VERSION 5.8 ;
BUSBITCHARS "[]" ;
DIVIDERCHAR "/" ;
UNITS
    DATABASE MICRONS 1000 ;
END UNITS

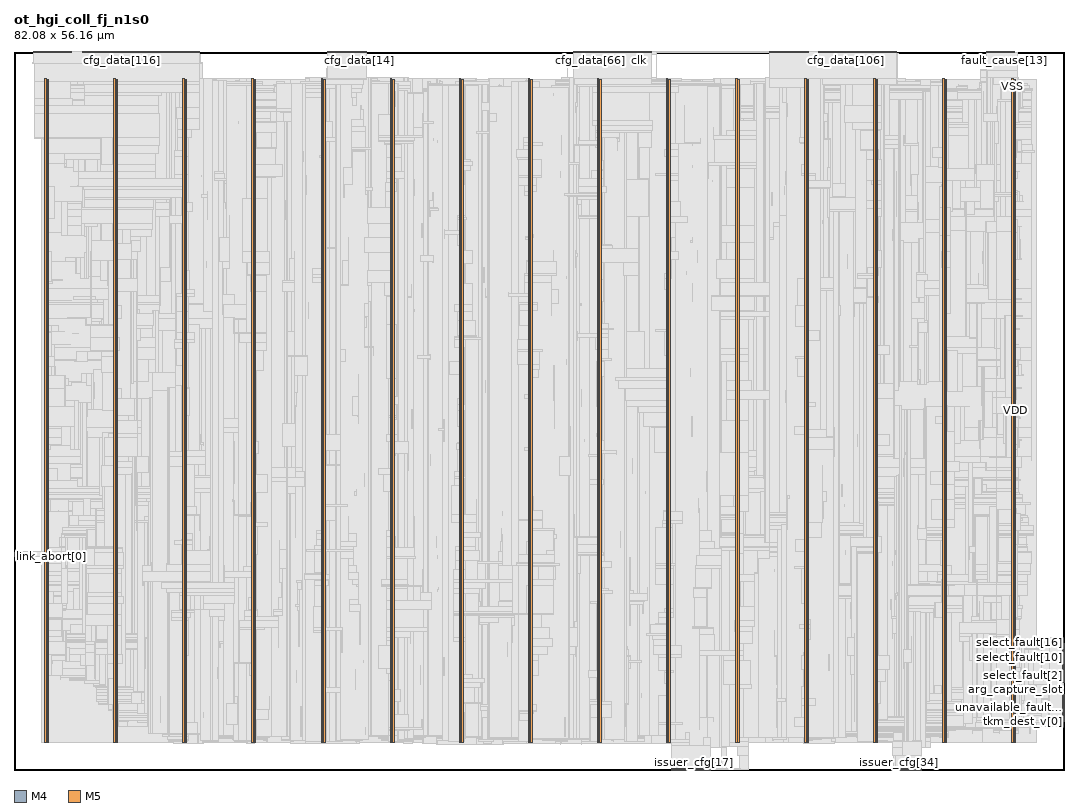
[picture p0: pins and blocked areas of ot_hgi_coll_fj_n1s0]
MACRO ot_hgi_coll_fj_n1s0
  FOREIGN ot_hgi_coll_fj_n1s0 0 0 ;
  CLASS BLOCK ;
  SIZE 82.08 BY 56.16 ;
  PIN arg_capture_slot
    DIRECTION INPUT ;
    USE SIGNAL ;
    PORT
      LAYER M4 ;
        RECT  81.996 6.864 82.08 6.888 ;
    END
  END arg_capture_slot
  PIN capture_fault[0]
    DIRECTION INPUT ;
    USE SIGNAL ;
    PORT
      LAYER M4 ;
        RECT  81.996 6.96 82.08 6.984 ;
    END
  END capture_fault[0]
  PIN capture_fault[1]
    DIRECTION INPUT ;
    USE SIGNAL ;
    PORT
      LAYER M4 ;
        RECT  81.996 7.056 82.08 7.08 ;
    END
  END capture_fault[1]
  PIN capture_fault[2]
    DIRECTION INPUT ;
    USE SIGNAL ;
    PORT
      LAYER M4 ;
        RECT  81.996 7.152 82.08 7.176 ;
    END
  END capture_fault[2]
  PIN capture_fault[3]
    DIRECTION INPUT ;
    USE SIGNAL ;
    PORT
      LAYER M4 ;
        RECT  81.996 7.248 82.08 7.272 ;
    END
  END capture_fault[3]
  PIN capture_fault[4]
    DIRECTION INPUT ;
    USE SIGNAL ;
    PORT
      LAYER M4 ;
        RECT  81.996 7.344 82.08 7.368 ;
    END
  END capture_fault[4]
  PIN capture_fault[5]
    DIRECTION INPUT ;
    USE SIGNAL ;
    PORT
      LAYER M4 ;
        RECT  81.996 7.44 82.08 7.464 ;
    END
  END capture_fault[5]
  PIN capture_fault[6]
    DIRECTION INPUT ;
    USE SIGNAL ;
    PORT
      LAYER M4 ;
        RECT  81.996 7.536 82.08 7.56 ;
    END
  END capture_fault[6]
  PIN capture_fault[7]
    DIRECTION INPUT ;
    USE SIGNAL ;
    PORT
      LAYER M4 ;
        RECT  81.996 7.632 82.08 7.656 ;
    END
  END capture_fault[7]
  PIN cfg_addr[0]
    DIRECTION INPUT ;
    USE SIGNAL ;
    PORT
      LAYER M5 ;
        RECT  24.528 56.076 24.552 56.16 ;
    END
  END cfg_addr[0]
  PIN cfg_addr[10]
    DIRECTION INPUT ;
    USE SIGNAL ;
    PORT
      LAYER M5 ;
        RECT  25.488 56.076 25.512 56.16 ;
    END
  END cfg_addr[10]
  PIN cfg_addr[11]
    DIRECTION INPUT ;
    USE SIGNAL ;
    PORT
      LAYER M5 ;
        RECT  25.584 56.076 25.608 56.16 ;
    END
  END cfg_addr[11]
  PIN cfg_addr[1]
    DIRECTION INPUT ;
    USE SIGNAL ;
    PORT
      LAYER M5 ;
        RECT  24.624 56.076 24.648 56.16 ;
    END
  END cfg_addr[1]
  PIN cfg_addr[2]
    DIRECTION INPUT ;
    USE SIGNAL ;
    PORT
      LAYER M5 ;
        RECT  24.72 56.076 24.744 56.16 ;
    END
  END cfg_addr[2]
  PIN cfg_addr[3]
    DIRECTION INPUT ;
    USE SIGNAL ;
    PORT
      LAYER M5 ;
        RECT  24.816 56.076 24.84 56.16 ;
    END
  END cfg_addr[3]
  PIN cfg_addr[4]
    DIRECTION INPUT ;
    USE SIGNAL ;
    PORT
      LAYER M5 ;
        RECT  24.912 56.076 24.936 56.16 ;
    END
  END cfg_addr[4]
  PIN cfg_addr[5]
    DIRECTION INPUT ;
    USE SIGNAL ;
    PORT
      LAYER M5 ;
        RECT  25.008 56.076 25.032 56.16 ;
    END
  END cfg_addr[5]
  PIN cfg_addr[6]
    DIRECTION INPUT ;
    USE SIGNAL ;
    PORT
      LAYER M5 ;
        RECT  25.104 56.076 25.128 56.16 ;
    END
  END cfg_addr[6]
  PIN cfg_addr[7]
    DIRECTION INPUT ;
    USE SIGNAL ;
    PORT
      LAYER M5 ;
        RECT  25.2 56.076 25.224 56.16 ;
    END
  END cfg_addr[7]
  PIN cfg_addr[8]
    DIRECTION INPUT ;
    USE SIGNAL ;
    PORT
      LAYER M5 ;
        RECT  25.296 56.076 25.32 56.16 ;
    END
  END cfg_addr[8]
  PIN cfg_addr[9]
    DIRECTION INPUT ;
    USE SIGNAL ;
    PORT
      LAYER M5 ;
        RECT  25.392 56.076 25.416 56.16 ;
    END
  END cfg_addr[9]
  PIN cfg_data[0]
    DIRECTION INPUT ;
    USE SIGNAL ;
    PORT
      LAYER M5 ;
        RECT  25.68 56.076 25.704 56.16 ;
    END
  END cfg_data[0]
  PIN cfg_data[100]
    DIRECTION INPUT ;
    USE SIGNAL ;
    PORT
      LAYER M5 ;
        RECT  64.464 56.076 64.488 56.16 ;
    END
  END cfg_data[100]
  PIN cfg_data[101]
    DIRECTION INPUT ;
    USE SIGNAL ;
    PORT
      LAYER M5 ;
        RECT  64.56 56.076 64.584 56.16 ;
    END
  END cfg_data[101]
  PIN cfg_data[102]
    DIRECTION INPUT ;
    USE SIGNAL ;
    PORT
      LAYER M5 ;
        RECT  64.656 56.076 64.68 56.16 ;
    END
  END cfg_data[102]
  PIN cfg_data[103]
    DIRECTION INPUT ;
    USE SIGNAL ;
    PORT
      LAYER M5 ;
        RECT  64.752 56.076 64.776 56.16 ;
    END
  END cfg_data[103]
  PIN cfg_data[104]
    DIRECTION INPUT ;
    USE SIGNAL ;
    PORT
      LAYER M5 ;
        RECT  64.848 56.076 64.872 56.16 ;
    END
  END cfg_data[104]
  PIN cfg_data[105]
    DIRECTION INPUT ;
    USE SIGNAL ;
    PORT
      LAYER M5 ;
        RECT  64.944 56.076 64.968 56.16 ;
    END
  END cfg_data[105]
  PIN cfg_data[106]
    DIRECTION INPUT ;
    USE SIGNAL ;
    PORT
      LAYER M5 ;
        RECT  65.04 56.076 65.064 56.16 ;
    END
  END cfg_data[106]
  PIN cfg_data[107]
    DIRECTION INPUT ;
    USE SIGNAL ;
    PORT
      LAYER M5 ;
        RECT  65.136 56.076 65.16 56.16 ;
    END
  END cfg_data[107]
  PIN cfg_data[108]
    DIRECTION INPUT ;
    USE SIGNAL ;
    PORT
      LAYER M5 ;
        RECT  65.232 56.076 65.256 56.16 ;
    END
  END cfg_data[108]
  PIN cfg_data[109]
    DIRECTION INPUT ;
    USE SIGNAL ;
    PORT
      LAYER M5 ;
        RECT  65.328 56.076 65.352 56.16 ;
    END
  END cfg_data[109]
  PIN cfg_data[10]
    DIRECTION INPUT ;
    USE SIGNAL ;
    PORT
      LAYER M5 ;
        RECT  26.64 56.076 26.664 56.16 ;
    END
  END cfg_data[10]
  PIN cfg_data[110]
    DIRECTION INPUT ;
    USE SIGNAL ;
    PORT
      LAYER M5 ;
        RECT  65.424 56.076 65.448 56.16 ;
    END
  END cfg_data[110]
  PIN cfg_data[111]
    DIRECTION INPUT ;
    USE SIGNAL ;
    PORT
      LAYER M5 ;
        RECT  65.52 56.076 65.544 56.16 ;
    END
  END cfg_data[111]
  PIN cfg_data[112]
    DIRECTION INPUT ;
    USE SIGNAL ;
    PORT
      LAYER M5 ;
        RECT  65.616 56.076 65.64 56.16 ;
    END
  END cfg_data[112]
  PIN cfg_data[113]
    DIRECTION INPUT ;
    USE SIGNAL ;
    PORT
      LAYER M5 ;
        RECT  65.712 56.076 65.736 56.16 ;
    END
  END cfg_data[113]
  PIN cfg_data[114]
    DIRECTION INPUT ;
    USE SIGNAL ;
    PORT
      LAYER M5 ;
        RECT  65.808 56.076 65.832 56.16 ;
    END
  END cfg_data[114]
  PIN cfg_data[115]
    DIRECTION INPUT ;
    USE SIGNAL ;
    PORT
      LAYER M5 ;
        RECT  65.904 56.076 65.928 56.16 ;
    END
  END cfg_data[115]
  PIN cfg_data[116]
    DIRECTION INPUT ;
    USE SIGNAL ;
    PORT
      LAYER M5 ;
        RECT  8.4 56.076 8.424 56.16 ;
    END
  END cfg_data[116]
  PIN cfg_data[117]
    DIRECTION INPUT ;
    USE SIGNAL ;
    PORT
      LAYER M5 ;
        RECT  8.496 56.076 8.52 56.16 ;
    END
  END cfg_data[117]
  PIN cfg_data[118]
    DIRECTION INPUT ;
    USE SIGNAL ;
    PORT
      LAYER M5 ;
        RECT  8.592 56.076 8.616 56.16 ;
    END
  END cfg_data[118]
  PIN cfg_data[119]
    DIRECTION INPUT ;
    USE SIGNAL ;
    PORT
      LAYER M5 ;
        RECT  8.688 56.076 8.712 56.16 ;
    END
  END cfg_data[119]
  PIN cfg_data[11]
    DIRECTION INPUT ;
    USE SIGNAL ;
    PORT
      LAYER M5 ;
        RECT  26.736 56.076 26.76 56.16 ;
    END
  END cfg_data[11]
  PIN cfg_data[120]
    DIRECTION INPUT ;
    USE SIGNAL ;
    PORT
      LAYER M5 ;
        RECT  8.784 56.076 8.808 56.16 ;
    END
  END cfg_data[120]
  PIN cfg_data[121]
    DIRECTION INPUT ;
    USE SIGNAL ;
    PORT
      LAYER M5 ;
        RECT  8.88 56.076 8.904 56.16 ;
    END
  END cfg_data[121]
  PIN cfg_data[122]
    DIRECTION INPUT ;
    USE SIGNAL ;
    PORT
      LAYER M5 ;
        RECT  8.976 56.076 9 56.16 ;
    END
  END cfg_data[122]
  PIN cfg_data[123]
    DIRECTION INPUT ;
    USE SIGNAL ;
    PORT
      LAYER M5 ;
        RECT  9.072 56.076 9.096 56.16 ;
    END
  END cfg_data[123]
  PIN cfg_data[124]
    DIRECTION INPUT ;
    USE SIGNAL ;
    PORT
      LAYER M5 ;
        RECT  9.168 56.076 9.192 56.16 ;
    END
  END cfg_data[124]
  PIN cfg_data[125]
    DIRECTION INPUT ;
    USE SIGNAL ;
    PORT
      LAYER M5 ;
        RECT  9.264 56.076 9.288 56.16 ;
    END
  END cfg_data[125]
  PIN cfg_data[126]
    DIRECTION INPUT ;
    USE SIGNAL ;
    PORT
      LAYER M5 ;
        RECT  9.36 56.076 9.384 56.16 ;
    END
  END cfg_data[126]
  PIN cfg_data[127]
    DIRECTION INPUT ;
    USE SIGNAL ;
    PORT
      LAYER M5 ;
        RECT  9.456 56.076 9.48 56.16 ;
    END
  END cfg_data[127]
  PIN cfg_data[128]
    DIRECTION INPUT ;
    USE SIGNAL ;
    PORT
      LAYER M5 ;
        RECT  9.552 56.076 9.576 56.16 ;
    END
  END cfg_data[128]
  PIN cfg_data[129]
    DIRECTION INPUT ;
    USE SIGNAL ;
    PORT
      LAYER M5 ;
        RECT  9.648 56.076 9.672 56.16 ;
    END
  END cfg_data[129]
  PIN cfg_data[12]
    DIRECTION INPUT ;
    USE SIGNAL ;
    PORT
      LAYER M5 ;
        RECT  26.832 56.076 26.856 56.16 ;
    END
  END cfg_data[12]
  PIN cfg_data[130]
    DIRECTION INPUT ;
    USE SIGNAL ;
    PORT
      LAYER M5 ;
        RECT  9.744 56.076 9.768 56.16 ;
    END
  END cfg_data[130]
  PIN cfg_data[131]
    DIRECTION INPUT ;
    USE SIGNAL ;
    PORT
      LAYER M5 ;
        RECT  9.84 56.076 9.864 56.16 ;
    END
  END cfg_data[131]
  PIN cfg_data[132]
    DIRECTION INPUT ;
    USE SIGNAL ;
    PORT
      LAYER M5 ;
        RECT  9.936 56.076 9.96 56.16 ;
    END
  END cfg_data[132]
  PIN cfg_data[133]
    DIRECTION INPUT ;
    USE SIGNAL ;
    PORT
      LAYER M5 ;
        RECT  10.032 56.076 10.056 56.16 ;
    END
  END cfg_data[133]
  PIN cfg_data[134]
    DIRECTION INPUT ;
    USE SIGNAL ;
    PORT
      LAYER M5 ;
        RECT  10.128 56.076 10.152 56.16 ;
    END
  END cfg_data[134]
  PIN cfg_data[135]
    DIRECTION INPUT ;
    USE SIGNAL ;
    PORT
      LAYER M5 ;
        RECT  10.224 56.076 10.248 56.16 ;
    END
  END cfg_data[135]
  PIN cfg_data[136]
    DIRECTION INPUT ;
    USE SIGNAL ;
    PORT
      LAYER M5 ;
        RECT  10.32 56.076 10.344 56.16 ;
    END
  END cfg_data[136]
  PIN cfg_data[137]
    DIRECTION INPUT ;
    USE SIGNAL ;
    PORT
      LAYER M5 ;
        RECT  10.416 56.076 10.44 56.16 ;
    END
  END cfg_data[137]
  PIN cfg_data[138]
    DIRECTION INPUT ;
    USE SIGNAL ;
    PORT
      LAYER M5 ;
        RECT  10.512 56.076 10.536 56.16 ;
    END
  END cfg_data[138]
  PIN cfg_data[139]
    DIRECTION INPUT ;
    USE SIGNAL ;
    PORT
      LAYER M5 ;
        RECT  10.608 56.076 10.632 56.16 ;
    END
  END cfg_data[139]
  PIN cfg_data[13]
    DIRECTION INPUT ;
    USE SIGNAL ;
    PORT
      LAYER M5 ;
        RECT  26.928 56.076 26.952 56.16 ;
    END
  END cfg_data[13]
  PIN cfg_data[140]
    DIRECTION INPUT ;
    USE SIGNAL ;
    PORT
      LAYER M5 ;
        RECT  10.704 56.076 10.728 56.16 ;
    END
  END cfg_data[140]
  PIN cfg_data[141]
    DIRECTION INPUT ;
    USE SIGNAL ;
    PORT
      LAYER M5 ;
        RECT  10.8 56.076 10.824 56.16 ;
    END
  END cfg_data[141]
  PIN cfg_data[142]
    DIRECTION INPUT ;
    USE SIGNAL ;
    PORT
      LAYER M5 ;
        RECT  10.896 56.076 10.92 56.16 ;
    END
  END cfg_data[142]
  PIN cfg_data[143]
    DIRECTION INPUT ;
    USE SIGNAL ;
    PORT
      LAYER M5 ;
        RECT  10.992 56.076 11.016 56.16 ;
    END
  END cfg_data[143]
  PIN cfg_data[144]
    DIRECTION INPUT ;
    USE SIGNAL ;
    PORT
      LAYER M5 ;
        RECT  11.088 56.076 11.112 56.16 ;
    END
  END cfg_data[144]
  PIN cfg_data[145]
    DIRECTION INPUT ;
    USE SIGNAL ;
    PORT
      LAYER M5 ;
        RECT  11.184 56.076 11.208 56.16 ;
    END
  END cfg_data[145]
  PIN cfg_data[146]
    DIRECTION INPUT ;
    USE SIGNAL ;
    PORT
      LAYER M5 ;
        RECT  11.28 56.076 11.304 56.16 ;
    END
  END cfg_data[146]
  PIN cfg_data[147]
    DIRECTION INPUT ;
    USE SIGNAL ;
    PORT
      LAYER M5 ;
        RECT  11.376 56.076 11.4 56.16 ;
    END
  END cfg_data[147]
  PIN cfg_data[148]
    DIRECTION INPUT ;
    USE SIGNAL ;
    PORT
      LAYER M5 ;
        RECT  1.488 56.076 1.512 56.16 ;
    END
  END cfg_data[148]
  PIN cfg_data[149]
    DIRECTION INPUT ;
    USE SIGNAL ;
    PORT
      LAYER M5 ;
        RECT  1.584 56.076 1.608 56.16 ;
    END
  END cfg_data[149]
  PIN cfg_data[14]
    DIRECTION INPUT ;
    USE SIGNAL ;
    PORT
      LAYER M5 ;
        RECT  27.024 56.076 27.048 56.16 ;
    END
  END cfg_data[14]
  PIN cfg_data[150]
    DIRECTION INPUT ;
    USE SIGNAL ;
    PORT
      LAYER M5 ;
        RECT  1.68 56.076 1.704 56.16 ;
    END
  END cfg_data[150]
  PIN cfg_data[151]
    DIRECTION INPUT ;
    USE SIGNAL ;
    PORT
      LAYER M5 ;
        RECT  1.776 56.076 1.8 56.16 ;
    END
  END cfg_data[151]
  PIN cfg_data[152]
    DIRECTION INPUT ;
    USE SIGNAL ;
    PORT
      LAYER M5 ;
        RECT  1.872 56.076 1.896 56.16 ;
    END
  END cfg_data[152]
  PIN cfg_data[153]
    DIRECTION INPUT ;
    USE SIGNAL ;
    PORT
      LAYER M5 ;
        RECT  1.968 56.076 1.992 56.16 ;
    END
  END cfg_data[153]
  PIN cfg_data[154]
    DIRECTION INPUT ;
    USE SIGNAL ;
    PORT
      LAYER M5 ;
        RECT  2.064 56.076 2.088 56.16 ;
    END
  END cfg_data[154]
  PIN cfg_data[155]
    DIRECTION INPUT ;
    USE SIGNAL ;
    PORT
      LAYER M5 ;
        RECT  2.16 56.076 2.184 56.16 ;
    END
  END cfg_data[155]
  PIN cfg_data[156]
    DIRECTION INPUT ;
    USE SIGNAL ;
    PORT
      LAYER M5 ;
        RECT  2.256 56.076 2.28 56.16 ;
    END
  END cfg_data[156]
  PIN cfg_data[157]
    DIRECTION INPUT ;
    USE SIGNAL ;
    PORT
      LAYER M5 ;
        RECT  2.352 56.076 2.376 56.16 ;
    END
  END cfg_data[157]
  PIN cfg_data[158]
    DIRECTION INPUT ;
    USE SIGNAL ;
    PORT
      LAYER M5 ;
        RECT  2.448 56.076 2.472 56.16 ;
    END
  END cfg_data[158]
  PIN cfg_data[159]
    DIRECTION INPUT ;
    USE SIGNAL ;
    PORT
      LAYER M5 ;
        RECT  2.544 56.076 2.568 56.16 ;
    END
  END cfg_data[159]
  PIN cfg_data[15]
    DIRECTION INPUT ;
    USE SIGNAL ;
    PORT
      LAYER M5 ;
        RECT  27.12 56.076 27.144 56.16 ;
    END
  END cfg_data[15]
  PIN cfg_data[160]
    DIRECTION INPUT ;
    USE SIGNAL ;
    PORT
      LAYER M5 ;
        RECT  2.64 56.076 2.664 56.16 ;
    END
  END cfg_data[160]
  PIN cfg_data[161]
    DIRECTION INPUT ;
    USE SIGNAL ;
    PORT
      LAYER M5 ;
        RECT  2.736 56.076 2.76 56.16 ;
    END
  END cfg_data[161]
  PIN cfg_data[162]
    DIRECTION INPUT ;
    USE SIGNAL ;
    PORT
      LAYER M5 ;
        RECT  2.832 56.076 2.856 56.16 ;
    END
  END cfg_data[162]
  PIN cfg_data[163]
    DIRECTION INPUT ;
    USE SIGNAL ;
    PORT
      LAYER M5 ;
        RECT  2.928 56.076 2.952 56.16 ;
    END
  END cfg_data[163]
  PIN cfg_data[164]
    DIRECTION INPUT ;
    USE SIGNAL ;
    PORT
      LAYER M5 ;
        RECT  3.024 56.076 3.048 56.16 ;
    END
  END cfg_data[164]
  PIN cfg_data[165]
    DIRECTION INPUT ;
    USE SIGNAL ;
    PORT
      LAYER M5 ;
        RECT  3.12 56.076 3.144 56.16 ;
    END
  END cfg_data[165]
  PIN cfg_data[166]
    DIRECTION INPUT ;
    USE SIGNAL ;
    PORT
      LAYER M5 ;
        RECT  3.216 56.076 3.24 56.16 ;
    END
  END cfg_data[166]
  PIN cfg_data[167]
    DIRECTION INPUT ;
    USE SIGNAL ;
    PORT
      LAYER M5 ;
        RECT  3.312 56.076 3.336 56.16 ;
    END
  END cfg_data[167]
  PIN cfg_data[168]
    DIRECTION INPUT ;
    USE SIGNAL ;
    PORT
      LAYER M5 ;
        RECT  3.408 56.076 3.432 56.16 ;
    END
  END cfg_data[168]
  PIN cfg_data[169]
    DIRECTION INPUT ;
    USE SIGNAL ;
    PORT
      LAYER M5 ;
        RECT  3.504 56.076 3.528 56.16 ;
    END
  END cfg_data[169]
  PIN cfg_data[16]
    DIRECTION INPUT ;
    USE SIGNAL ;
    PORT
      LAYER M5 ;
        RECT  27.216 56.076 27.24 56.16 ;
    END
  END cfg_data[16]
  PIN cfg_data[170]
    DIRECTION INPUT ;
    USE SIGNAL ;
    PORT
      LAYER M5 ;
        RECT  3.6 56.076 3.624 56.16 ;
    END
  END cfg_data[170]
  PIN cfg_data[171]
    DIRECTION INPUT ;
    USE SIGNAL ;
    PORT
      LAYER M5 ;
        RECT  3.696 56.076 3.72 56.16 ;
    END
  END cfg_data[171]
  PIN cfg_data[172]
    DIRECTION INPUT ;
    USE SIGNAL ;
    PORT
      LAYER M5 ;
        RECT  3.792 56.076 3.816 56.16 ;
    END
  END cfg_data[172]
  PIN cfg_data[173]
    DIRECTION INPUT ;
    USE SIGNAL ;
    PORT
      LAYER M5 ;
        RECT  3.888 56.076 3.912 56.16 ;
    END
  END cfg_data[173]
  PIN cfg_data[174]
    DIRECTION INPUT ;
    USE SIGNAL ;
    PORT
      LAYER M5 ;
        RECT  3.984 56.076 4.008 56.16 ;
    END
  END cfg_data[174]
  PIN cfg_data[175]
    DIRECTION INPUT ;
    USE SIGNAL ;
    PORT
      LAYER M5 ;
        RECT  4.08 56.076 4.104 56.16 ;
    END
  END cfg_data[175]
  PIN cfg_data[176]
    DIRECTION INPUT ;
    USE SIGNAL ;
    PORT
      LAYER M5 ;
        RECT  4.176 56.076 4.2 56.16 ;
    END
  END cfg_data[176]
  PIN cfg_data[177]
    DIRECTION INPUT ;
    USE SIGNAL ;
    PORT
      LAYER M5 ;
        RECT  4.272 56.076 4.296 56.16 ;
    END
  END cfg_data[177]
  PIN cfg_data[178]
    DIRECTION INPUT ;
    USE SIGNAL ;
    PORT
      LAYER M5 ;
        RECT  4.368 56.076 4.392 56.16 ;
    END
  END cfg_data[178]
  PIN cfg_data[179]
    DIRECTION INPUT ;
    USE SIGNAL ;
    PORT
      LAYER M5 ;
        RECT  4.464 56.076 4.488 56.16 ;
    END
  END cfg_data[179]
  PIN cfg_data[17]
    DIRECTION INPUT ;
    USE SIGNAL ;
    PORT
      LAYER M5 ;
        RECT  27.312 56.076 27.336 56.16 ;
    END
  END cfg_data[17]
  PIN cfg_data[180]
    DIRECTION INPUT ;
    USE SIGNAL ;
    PORT
      LAYER M5 ;
        RECT  59.088 56.076 59.112 56.16 ;
    END
  END cfg_data[180]
  PIN cfg_data[181]
    DIRECTION INPUT ;
    USE SIGNAL ;
    PORT
      LAYER M5 ;
        RECT  59.184 56.076 59.208 56.16 ;
    END
  END cfg_data[181]
  PIN cfg_data[182]
    DIRECTION INPUT ;
    USE SIGNAL ;
    PORT
      LAYER M5 ;
        RECT  59.28 56.076 59.304 56.16 ;
    END
  END cfg_data[182]
  PIN cfg_data[183]
    DIRECTION INPUT ;
    USE SIGNAL ;
    PORT
      LAYER M5 ;
        RECT  59.376 56.076 59.4 56.16 ;
    END
  END cfg_data[183]
  PIN cfg_data[184]
    DIRECTION INPUT ;
    USE SIGNAL ;
    PORT
      LAYER M5 ;
        RECT  59.472 56.076 59.496 56.16 ;
    END
  END cfg_data[184]
  PIN cfg_data[185]
    DIRECTION INPUT ;
    USE SIGNAL ;
    PORT
      LAYER M5 ;
        RECT  59.568 56.076 59.592 56.16 ;
    END
  END cfg_data[185]
  PIN cfg_data[186]
    DIRECTION INPUT ;
    USE SIGNAL ;
    PORT
      LAYER M5 ;
        RECT  59.664 56.076 59.688 56.16 ;
    END
  END cfg_data[186]
  PIN cfg_data[187]
    DIRECTION INPUT ;
    USE SIGNAL ;
    PORT
      LAYER M5 ;
        RECT  59.76 56.076 59.784 56.16 ;
    END
  END cfg_data[187]
  PIN cfg_data[188]
    DIRECTION INPUT ;
    USE SIGNAL ;
    PORT
      LAYER M5 ;
        RECT  59.856 56.076 59.88 56.16 ;
    END
  END cfg_data[188]
  PIN cfg_data[189]
    DIRECTION INPUT ;
    USE SIGNAL ;
    PORT
      LAYER M5 ;
        RECT  59.952 56.076 59.976 56.16 ;
    END
  END cfg_data[189]
  PIN cfg_data[18]
    DIRECTION INPUT ;
    USE SIGNAL ;
    PORT
      LAYER M5 ;
        RECT  27.408 56.076 27.432 56.16 ;
    END
  END cfg_data[18]
  PIN cfg_data[190]
    DIRECTION INPUT ;
    USE SIGNAL ;
    PORT
      LAYER M5 ;
        RECT  60.048 56.076 60.072 56.16 ;
    END
  END cfg_data[190]
  PIN cfg_data[191]
    DIRECTION INPUT ;
    USE SIGNAL ;
    PORT
      LAYER M5 ;
        RECT  60.144 56.076 60.168 56.16 ;
    END
  END cfg_data[191]
  PIN cfg_data[192]
    DIRECTION INPUT ;
    USE SIGNAL ;
    PORT
      LAYER M5 ;
        RECT  60.24 56.076 60.264 56.16 ;
    END
  END cfg_data[192]
  PIN cfg_data[193]
    DIRECTION INPUT ;
    USE SIGNAL ;
    PORT
      LAYER M5 ;
        RECT  60.336 56.076 60.36 56.16 ;
    END
  END cfg_data[193]
  PIN cfg_data[194]
    DIRECTION INPUT ;
    USE SIGNAL ;
    PORT
      LAYER M5 ;
        RECT  60.432 56.076 60.456 56.16 ;
    END
  END cfg_data[194]
  PIN cfg_data[195]
    DIRECTION INPUT ;
    USE SIGNAL ;
    PORT
      LAYER M5 ;
        RECT  60.528 56.076 60.552 56.16 ;
    END
  END cfg_data[195]
  PIN cfg_data[196]
    DIRECTION INPUT ;
    USE SIGNAL ;
    PORT
      LAYER M5 ;
        RECT  60.624 56.076 60.648 56.16 ;
    END
  END cfg_data[196]
  PIN cfg_data[197]
    DIRECTION INPUT ;
    USE SIGNAL ;
    PORT
      LAYER M5 ;
        RECT  60.72 56.076 60.744 56.16 ;
    END
  END cfg_data[197]
  PIN cfg_data[198]
    DIRECTION INPUT ;
    USE SIGNAL ;
    PORT
      LAYER M5 ;
        RECT  60.816 56.076 60.84 56.16 ;
    END
  END cfg_data[198]
  PIN cfg_data[199]
    DIRECTION INPUT ;
    USE SIGNAL ;
    PORT
      LAYER M5 ;
        RECT  60.912 56.076 60.936 56.16 ;
    END
  END cfg_data[199]
  PIN cfg_data[19]
    DIRECTION INPUT ;
    USE SIGNAL ;
    PORT
      LAYER M5 ;
        RECT  27.504 56.076 27.528 56.16 ;
    END
  END cfg_data[19]
  PIN cfg_data[1]
    DIRECTION INPUT ;
    USE SIGNAL ;
    PORT
      LAYER M5 ;
        RECT  25.776 56.076 25.8 56.16 ;
    END
  END cfg_data[1]
  PIN cfg_data[200]
    DIRECTION INPUT ;
    USE SIGNAL ;
    PORT
      LAYER M5 ;
        RECT  61.008 56.076 61.032 56.16 ;
    END
  END cfg_data[200]
  PIN cfg_data[201]
    DIRECTION INPUT ;
    USE SIGNAL ;
    PORT
      LAYER M5 ;
        RECT  61.104 56.076 61.128 56.16 ;
    END
  END cfg_data[201]
  PIN cfg_data[202]
    DIRECTION INPUT ;
    USE SIGNAL ;
    PORT
      LAYER M5 ;
        RECT  61.2 56.076 61.224 56.16 ;
    END
  END cfg_data[202]
  PIN cfg_data[203]
    DIRECTION INPUT ;
    USE SIGNAL ;
    PORT
      LAYER M5 ;
        RECT  61.296 56.076 61.32 56.16 ;
    END
  END cfg_data[203]
  PIN cfg_data[204]
    DIRECTION INPUT ;
    USE SIGNAL ;
    PORT
      LAYER M5 ;
        RECT  61.392 56.076 61.416 56.16 ;
    END
  END cfg_data[204]
  PIN cfg_data[205]
    DIRECTION INPUT ;
    USE SIGNAL ;
    PORT
      LAYER M5 ;
        RECT  61.488 56.076 61.512 56.16 ;
    END
  END cfg_data[205]
  PIN cfg_data[206]
    DIRECTION INPUT ;
    USE SIGNAL ;
    PORT
      LAYER M5 ;
        RECT  61.584 56.076 61.608 56.16 ;
    END
  END cfg_data[206]
  PIN cfg_data[207]
    DIRECTION INPUT ;
    USE SIGNAL ;
    PORT
      LAYER M5 ;
        RECT  61.68 56.076 61.704 56.16 ;
    END
  END cfg_data[207]
  PIN cfg_data[208]
    DIRECTION INPUT ;
    USE SIGNAL ;
    PORT
      LAYER M5 ;
        RECT  61.776 56.076 61.8 56.16 ;
    END
  END cfg_data[208]
  PIN cfg_data[209]
    DIRECTION INPUT ;
    USE SIGNAL ;
    PORT
      LAYER M5 ;
        RECT  61.872 56.076 61.896 56.16 ;
    END
  END cfg_data[209]
  PIN cfg_data[20]
    DIRECTION INPUT ;
    USE SIGNAL ;
    PORT
      LAYER M5 ;
        RECT  11.472 56.076 11.496 56.16 ;
    END
  END cfg_data[20]
  PIN cfg_data[210]
    DIRECTION INPUT ;
    USE SIGNAL ;
    PORT
      LAYER M5 ;
        RECT  61.968 56.076 61.992 56.16 ;
    END
  END cfg_data[210]
  PIN cfg_data[211]
    DIRECTION INPUT ;
    USE SIGNAL ;
    PORT
      LAYER M5 ;
        RECT  62.064 56.076 62.088 56.16 ;
    END
  END cfg_data[211]
  PIN cfg_data[212]
    DIRECTION INPUT ;
    USE SIGNAL ;
    PORT
      LAYER M5 ;
        RECT  66 56.076 66.024 56.16 ;
    END
  END cfg_data[212]
  PIN cfg_data[213]
    DIRECTION INPUT ;
    USE SIGNAL ;
    PORT
      LAYER M5 ;
        RECT  66.096 56.076 66.12 56.16 ;
    END
  END cfg_data[213]
  PIN cfg_data[214]
    DIRECTION INPUT ;
    USE SIGNAL ;
    PORT
      LAYER M5 ;
        RECT  66.192 56.076 66.216 56.16 ;
    END
  END cfg_data[214]
  PIN cfg_data[215]
    DIRECTION INPUT ;
    USE SIGNAL ;
    PORT
      LAYER M5 ;
        RECT  66.288 56.076 66.312 56.16 ;
    END
  END cfg_data[215]
  PIN cfg_data[216]
    DIRECTION INPUT ;
    USE SIGNAL ;
    PORT
      LAYER M5 ;
        RECT  66.384 56.076 66.408 56.16 ;
    END
  END cfg_data[216]
  PIN cfg_data[217]
    DIRECTION INPUT ;
    USE SIGNAL ;
    PORT
      LAYER M5 ;
        RECT  66.48 56.076 66.504 56.16 ;
    END
  END cfg_data[217]
  PIN cfg_data[218]
    DIRECTION INPUT ;
    USE SIGNAL ;
    PORT
      LAYER M5 ;
        RECT  66.576 56.076 66.6 56.16 ;
    END
  END cfg_data[218]
  PIN cfg_data[219]
    DIRECTION INPUT ;
    USE SIGNAL ;
    PORT
      LAYER M5 ;
        RECT  66.672 56.076 66.696 56.16 ;
    END
  END cfg_data[219]
  PIN cfg_data[21]
    DIRECTION INPUT ;
    USE SIGNAL ;
    PORT
      LAYER M5 ;
        RECT  11.568 56.076 11.592 56.16 ;
    END
  END cfg_data[21]
  PIN cfg_data[220]
    DIRECTION INPUT ;
    USE SIGNAL ;
    PORT
      LAYER M5 ;
        RECT  66.768 56.076 66.792 56.16 ;
    END
  END cfg_data[220]
  PIN cfg_data[221]
    DIRECTION INPUT ;
    USE SIGNAL ;
    PORT
      LAYER M5 ;
        RECT  66.864 56.076 66.888 56.16 ;
    END
  END cfg_data[221]
  PIN cfg_data[222]
    DIRECTION INPUT ;
    USE SIGNAL ;
    PORT
      LAYER M5 ;
        RECT  66.96 56.076 66.984 56.16 ;
    END
  END cfg_data[222]
  PIN cfg_data[223]
    DIRECTION INPUT ;
    USE SIGNAL ;
    PORT
      LAYER M5 ;
        RECT  67.056 56.076 67.08 56.16 ;
    END
  END cfg_data[223]
  PIN cfg_data[224]
    DIRECTION INPUT ;
    USE SIGNAL ;
    PORT
      LAYER M5 ;
        RECT  67.152 56.076 67.176 56.16 ;
    END
  END cfg_data[224]
  PIN cfg_data[225]
    DIRECTION INPUT ;
    USE SIGNAL ;
    PORT
      LAYER M5 ;
        RECT  67.248 56.076 67.272 56.16 ;
    END
  END cfg_data[225]
  PIN cfg_data[226]
    DIRECTION INPUT ;
    USE SIGNAL ;
    PORT
      LAYER M5 ;
        RECT  67.344 56.076 67.368 56.16 ;
    END
  END cfg_data[226]
  PIN cfg_data[227]
    DIRECTION INPUT ;
    USE SIGNAL ;
    PORT
      LAYER M5 ;
        RECT  67.44 56.076 67.464 56.16 ;
    END
  END cfg_data[227]
  PIN cfg_data[228]
    DIRECTION INPUT ;
    USE SIGNAL ;
    PORT
      LAYER M5 ;
        RECT  67.536 56.076 67.56 56.16 ;
    END
  END cfg_data[228]
  PIN cfg_data[229]
    DIRECTION INPUT ;
    USE SIGNAL ;
    PORT
      LAYER M5 ;
        RECT  67.632 56.076 67.656 56.16 ;
    END
  END cfg_data[229]
  PIN cfg_data[22]
    DIRECTION INPUT ;
    USE SIGNAL ;
    PORT
      LAYER M5 ;
        RECT  11.664 56.076 11.688 56.16 ;
    END
  END cfg_data[22]
  PIN cfg_data[230]
    DIRECTION INPUT ;
    USE SIGNAL ;
    PORT
      LAYER M5 ;
        RECT  67.728 56.076 67.752 56.16 ;
    END
  END cfg_data[230]
  PIN cfg_data[231]
    DIRECTION INPUT ;
    USE SIGNAL ;
    PORT
      LAYER M5 ;
        RECT  67.824 56.076 67.848 56.16 ;
    END
  END cfg_data[231]
  PIN cfg_data[232]
    DIRECTION INPUT ;
    USE SIGNAL ;
    PORT
      LAYER M5 ;
        RECT  67.92 56.076 67.944 56.16 ;
    END
  END cfg_data[232]
  PIN cfg_data[233]
    DIRECTION INPUT ;
    USE SIGNAL ;
    PORT
      LAYER M5 ;
        RECT  68.016 56.076 68.04 56.16 ;
    END
  END cfg_data[233]
  PIN cfg_data[234]
    DIRECTION INPUT ;
    USE SIGNAL ;
    PORT
      LAYER M5 ;
        RECT  68.112 56.076 68.136 56.16 ;
    END
  END cfg_data[234]
  PIN cfg_data[235]
    DIRECTION INPUT ;
    USE SIGNAL ;
    PORT
      LAYER M5 ;
        RECT  68.208 56.076 68.232 56.16 ;
    END
  END cfg_data[235]
  PIN cfg_data[236]
    DIRECTION INPUT ;
    USE SIGNAL ;
    PORT
      LAYER M5 ;
        RECT  68.304 56.076 68.328 56.16 ;
    END
  END cfg_data[236]
  PIN cfg_data[237]
    DIRECTION INPUT ;
    USE SIGNAL ;
    PORT
      LAYER M5 ;
        RECT  68.4 56.076 68.424 56.16 ;
    END
  END cfg_data[237]
  PIN cfg_data[238]
    DIRECTION INPUT ;
    USE SIGNAL ;
    PORT
      LAYER M5 ;
        RECT  68.496 56.076 68.52 56.16 ;
    END
  END cfg_data[238]
  PIN cfg_data[239]
    DIRECTION INPUT ;
    USE SIGNAL ;
    PORT
      LAYER M5 ;
        RECT  68.592 56.076 68.616 56.16 ;
    END
  END cfg_data[239]
  PIN cfg_data[23]
    DIRECTION INPUT ;
    USE SIGNAL ;
    PORT
      LAYER M5 ;
        RECT  11.76 56.076 11.784 56.16 ;
    END
  END cfg_data[23]
  PIN cfg_data[240]
    DIRECTION INPUT ;
    USE SIGNAL ;
    PORT
      LAYER M5 ;
        RECT  68.688 56.076 68.712 56.16 ;
    END
  END cfg_data[240]
  PIN cfg_data[241]
    DIRECTION INPUT ;
    USE SIGNAL ;
    PORT
      LAYER M5 ;
        RECT  68.784 56.076 68.808 56.16 ;
    END
  END cfg_data[241]
  PIN cfg_data[242]
    DIRECTION INPUT ;
    USE SIGNAL ;
    PORT
      LAYER M5 ;
        RECT  68.88 56.076 68.904 56.16 ;
    END
  END cfg_data[242]
  PIN cfg_data[243]
    DIRECTION INPUT ;
    USE SIGNAL ;
    PORT
      LAYER M5 ;
        RECT  68.976 56.076 69 56.16 ;
    END
  END cfg_data[243]
  PIN cfg_data[244]
    DIRECTION INPUT ;
    USE SIGNAL ;
    PORT
      LAYER M5 ;
        RECT  46.8 56.076 46.824 56.16 ;
    END
  END cfg_data[244]
  PIN cfg_data[245]
    DIRECTION INPUT ;
    USE SIGNAL ;
    PORT
      LAYER M5 ;
        RECT  46.896 56.076 46.92 56.16 ;
    END
  END cfg_data[245]
  PIN cfg_data[246]
    DIRECTION INPUT ;
    USE SIGNAL ;
    PORT
      LAYER M5 ;
        RECT  46.992 56.076 47.016 56.16 ;
    END
  END cfg_data[246]
  PIN cfg_data[247]
    DIRECTION INPUT ;
    USE SIGNAL ;
    PORT
      LAYER M5 ;
        RECT  47.088 56.076 47.112 56.16 ;
    END
  END cfg_data[247]
  PIN cfg_data[248]
    DIRECTION INPUT ;
    USE SIGNAL ;
    PORT
      LAYER M5 ;
        RECT  47.184 56.076 47.208 56.16 ;
    END
  END cfg_data[248]
  PIN cfg_data[249]
    DIRECTION INPUT ;
    USE SIGNAL ;
    PORT
      LAYER M5 ;
        RECT  47.28 56.076 47.304 56.16 ;
    END
  END cfg_data[249]
  PIN cfg_data[24]
    DIRECTION INPUT ;
    USE SIGNAL ;
    PORT
      LAYER M5 ;
        RECT  11.856 56.076 11.88 56.16 ;
    END
  END cfg_data[24]
  PIN cfg_data[250]
    DIRECTION INPUT ;
    USE SIGNAL ;
    PORT
      LAYER M5 ;
        RECT  47.376 56.076 47.4 56.16 ;
    END
  END cfg_data[250]
  PIN cfg_data[251]
    DIRECTION INPUT ;
    USE SIGNAL ;
    PORT
      LAYER M5 ;
        RECT  47.472 56.076 47.496 56.16 ;
    END
  END cfg_data[251]
  PIN cfg_data[252]
    DIRECTION INPUT ;
    USE SIGNAL ;
    PORT
      LAYER M5 ;
        RECT  47.568 56.076 47.592 56.16 ;
    END
  END cfg_data[252]
  PIN cfg_data[253]
    DIRECTION INPUT ;
    USE SIGNAL ;
    PORT
      LAYER M5 ;
        RECT  47.664 56.076 47.688 56.16 ;
    END
  END cfg_data[253]
  PIN cfg_data[254]
    DIRECTION INPUT ;
    USE SIGNAL ;
    PORT
      LAYER M5 ;
        RECT  47.76 56.076 47.784 56.16 ;
    END
  END cfg_data[254]
  PIN cfg_data[255]
    DIRECTION INPUT ;
    USE SIGNAL ;
    PORT
      LAYER M5 ;
        RECT  47.856 56.076 47.88 56.16 ;
    END
  END cfg_data[255]
  PIN cfg_data[25]
    DIRECTION INPUT ;
    USE SIGNAL ;
    PORT
      LAYER M5 ;
        RECT  11.952 56.076 11.976 56.16 ;
    END
  END cfg_data[25]
  PIN cfg_data[26]
    DIRECTION INPUT ;
    USE SIGNAL ;
    PORT
      LAYER M5 ;
        RECT  12.048 56.076 12.072 56.16 ;
    END
  END cfg_data[26]
  PIN cfg_data[27]
    DIRECTION INPUT ;
    USE SIGNAL ;
    PORT
      LAYER M5 ;
        RECT  12.144 56.076 12.168 56.16 ;
    END
  END cfg_data[27]
  PIN cfg_data[28]
    DIRECTION INPUT ;
    USE SIGNAL ;
    PORT
      LAYER M5 ;
        RECT  12.24 56.076 12.264 56.16 ;
    END
  END cfg_data[28]
  PIN cfg_data[29]
    DIRECTION INPUT ;
    USE SIGNAL ;
    PORT
      LAYER M5 ;
        RECT  12.336 56.076 12.36 56.16 ;
    END
  END cfg_data[29]
  PIN cfg_data[2]
    DIRECTION INPUT ;
    USE SIGNAL ;
    PORT
      LAYER M5 ;
        RECT  25.872 56.076 25.896 56.16 ;
    END
  END cfg_data[2]
  PIN cfg_data[30]
    DIRECTION INPUT ;
    USE SIGNAL ;
    PORT
      LAYER M5 ;
        RECT  12.432 56.076 12.456 56.16 ;
    END
  END cfg_data[30]
  PIN cfg_data[31]
    DIRECTION INPUT ;
    USE SIGNAL ;
    PORT
      LAYER M5 ;
        RECT  12.528 56.076 12.552 56.16 ;
    END
  END cfg_data[31]
  PIN cfg_data[32]
    DIRECTION INPUT ;
    USE SIGNAL ;
    PORT
      LAYER M5 ;
        RECT  12.624 56.076 12.648 56.16 ;
    END
  END cfg_data[32]
  PIN cfg_data[33]
    DIRECTION INPUT ;
    USE SIGNAL ;
    PORT
      LAYER M5 ;
        RECT  12.72 56.076 12.744 56.16 ;
    END
  END cfg_data[33]
  PIN cfg_data[34]
    DIRECTION INPUT ;
    USE SIGNAL ;
    PORT
      LAYER M5 ;
        RECT  12.816 56.076 12.84 56.16 ;
    END
  END cfg_data[34]
  PIN cfg_data[35]
    DIRECTION INPUT ;
    USE SIGNAL ;
    PORT
      LAYER M5 ;
        RECT  12.912 56.076 12.936 56.16 ;
    END
  END cfg_data[35]
  PIN cfg_data[36]
    DIRECTION INPUT ;
    USE SIGNAL ;
    PORT
      LAYER M5 ;
        RECT  13.008 56.076 13.032 56.16 ;
    END
  END cfg_data[36]
  PIN cfg_data[37]
    DIRECTION INPUT ;
    USE SIGNAL ;
    PORT
      LAYER M5 ;
        RECT  13.104 56.076 13.128 56.16 ;
    END
  END cfg_data[37]
  PIN cfg_data[38]
    DIRECTION INPUT ;
    USE SIGNAL ;
    PORT
      LAYER M5 ;
        RECT  13.2 56.076 13.224 56.16 ;
    END
  END cfg_data[38]
  PIN cfg_data[39]
    DIRECTION INPUT ;
    USE SIGNAL ;
    PORT
      LAYER M5 ;
        RECT  13.296 56.076 13.32 56.16 ;
    END
  END cfg_data[39]
  PIN cfg_data[3]
    DIRECTION INPUT ;
    USE SIGNAL ;
    PORT
      LAYER M5 ;
        RECT  25.968 56.076 25.992 56.16 ;
    END
  END cfg_data[3]
  PIN cfg_data[40]
    DIRECTION INPUT ;
    USE SIGNAL ;
    PORT
      LAYER M5 ;
        RECT  13.392 56.076 13.416 56.16 ;
    END
  END cfg_data[40]
  PIN cfg_data[41]
    DIRECTION INPUT ;
    USE SIGNAL ;
    PORT
      LAYER M5 ;
        RECT  13.488 56.076 13.512 56.16 ;
    END
  END cfg_data[41]
  PIN cfg_data[42]
    DIRECTION INPUT ;
    USE SIGNAL ;
    PORT
      LAYER M5 ;
        RECT  13.584 56.076 13.608 56.16 ;
    END
  END cfg_data[42]
  PIN cfg_data[43]
    DIRECTION INPUT ;
    USE SIGNAL ;
    PORT
      LAYER M5 ;
        RECT  13.68 56.076 13.704 56.16 ;
    END
  END cfg_data[43]
  PIN cfg_data[44]
    DIRECTION INPUT ;
    USE SIGNAL ;
    PORT
      LAYER M5 ;
        RECT  13.776 56.076 13.8 56.16 ;
    END
  END cfg_data[44]
  PIN cfg_data[45]
    DIRECTION INPUT ;
    USE SIGNAL ;
    PORT
      LAYER M5 ;
        RECT  13.872 56.076 13.896 56.16 ;
    END
  END cfg_data[45]
  PIN cfg_data[46]
    DIRECTION INPUT ;
    USE SIGNAL ;
    PORT
      LAYER M5 ;
        RECT  13.968 56.076 13.992 56.16 ;
    END
  END cfg_data[46]
  PIN cfg_data[47]
    DIRECTION INPUT ;
    USE SIGNAL ;
    PORT
      LAYER M5 ;
        RECT  14.064 56.076 14.088 56.16 ;
    END
  END cfg_data[47]
  PIN cfg_data[48]
    DIRECTION INPUT ;
    USE SIGNAL ;
    PORT
      LAYER M5 ;
        RECT  14.16 56.076 14.184 56.16 ;
    END
  END cfg_data[48]
  PIN cfg_data[49]
    DIRECTION INPUT ;
    USE SIGNAL ;
    PORT
      LAYER M5 ;
        RECT  14.256 56.076 14.28 56.16 ;
    END
  END cfg_data[49]
  PIN cfg_data[4]
    DIRECTION INPUT ;
    USE SIGNAL ;
    PORT
      LAYER M5 ;
        RECT  26.064 56.076 26.088 56.16 ;
    END
  END cfg_data[4]
  PIN cfg_data[50]
    DIRECTION INPUT ;
    USE SIGNAL ;
    PORT
      LAYER M5 ;
        RECT  14.352 56.076 14.376 56.16 ;
    END
  END cfg_data[50]
  PIN cfg_data[51]
    DIRECTION INPUT ;
    USE SIGNAL ;
    PORT
      LAYER M5 ;
        RECT  14.448 56.076 14.472 56.16 ;
    END
  END cfg_data[51]
  PIN cfg_data[52]
    DIRECTION INPUT ;
    USE SIGNAL ;
    PORT
      LAYER M5 ;
        RECT  43.728 56.076 43.752 56.16 ;
    END
  END cfg_data[52]
  PIN cfg_data[53]
    DIRECTION INPUT ;
    USE SIGNAL ;
    PORT
      LAYER M5 ;
        RECT  43.824 56.076 43.848 56.16 ;
    END
  END cfg_data[53]
  PIN cfg_data[54]
    DIRECTION INPUT ;
    USE SIGNAL ;
    PORT
      LAYER M5 ;
        RECT  43.92 56.076 43.944 56.16 ;
    END
  END cfg_data[54]
  PIN cfg_data[55]
    DIRECTION INPUT ;
    USE SIGNAL ;
    PORT
      LAYER M5 ;
        RECT  44.016 56.076 44.04 56.16 ;
    END
  END cfg_data[55]
  PIN cfg_data[56]
    DIRECTION INPUT ;
    USE SIGNAL ;
    PORT
      LAYER M5 ;
        RECT  44.112 56.076 44.136 56.16 ;
    END
  END cfg_data[56]
  PIN cfg_data[57]
    DIRECTION INPUT ;
    USE SIGNAL ;
    PORT
      LAYER M5 ;
        RECT  44.208 56.076 44.232 56.16 ;
    END
  END cfg_data[57]
  PIN cfg_data[58]
    DIRECTION INPUT ;
    USE SIGNAL ;
    PORT
      LAYER M5 ;
        RECT  44.304 56.076 44.328 56.16 ;
    END
  END cfg_data[58]
  PIN cfg_data[59]
    DIRECTION INPUT ;
    USE SIGNAL ;
    PORT
      LAYER M5 ;
        RECT  44.4 56.076 44.424 56.16 ;
    END
  END cfg_data[59]
  PIN cfg_data[5]
    DIRECTION INPUT ;
    USE SIGNAL ;
    PORT
      LAYER M5 ;
        RECT  26.16 56.076 26.184 56.16 ;
    END
  END cfg_data[5]
  PIN cfg_data[60]
    DIRECTION INPUT ;
    USE SIGNAL ;
    PORT
      LAYER M5 ;
        RECT  44.496 56.076 44.52 56.16 ;
    END
  END cfg_data[60]
  PIN cfg_data[61]
    DIRECTION INPUT ;
    USE SIGNAL ;
    PORT
      LAYER M5 ;
        RECT  44.592 56.076 44.616 56.16 ;
    END
  END cfg_data[61]
  PIN cfg_data[62]
    DIRECTION INPUT ;
    USE SIGNAL ;
    PORT
      LAYER M5 ;
        RECT  44.688 56.076 44.712 56.16 ;
    END
  END cfg_data[62]
  PIN cfg_data[63]
    DIRECTION INPUT ;
    USE SIGNAL ;
    PORT
      LAYER M5 ;
        RECT  44.784 56.076 44.808 56.16 ;
    END
  END cfg_data[63]
  PIN cfg_data[64]
    DIRECTION INPUT ;
    USE SIGNAL ;
    PORT
      LAYER M5 ;
        RECT  44.88 56.076 44.904 56.16 ;
    END
  END cfg_data[64]
  PIN cfg_data[65]
    DIRECTION INPUT ;
    USE SIGNAL ;
    PORT
      LAYER M5 ;
        RECT  44.976 56.076 45 56.16 ;
    END
  END cfg_data[65]
  PIN cfg_data[66]
    DIRECTION INPUT ;
    USE SIGNAL ;
    PORT
      LAYER M5 ;
        RECT  45.072 56.076 45.096 56.16 ;
    END
  END cfg_data[66]
  PIN cfg_data[67]
    DIRECTION INPUT ;
    USE SIGNAL ;
    PORT
      LAYER M5 ;
        RECT  45.168 56.076 45.192 56.16 ;
    END
  END cfg_data[67]
  PIN cfg_data[68]
    DIRECTION INPUT ;
    USE SIGNAL ;
    PORT
      LAYER M5 ;
        RECT  45.264 56.076 45.288 56.16 ;
    END
  END cfg_data[68]
  PIN cfg_data[69]
    DIRECTION INPUT ;
    USE SIGNAL ;
    PORT
      LAYER M5 ;
        RECT  45.36 56.076 45.384 56.16 ;
    END
  END cfg_data[69]
  PIN cfg_data[6]
    DIRECTION INPUT ;
    USE SIGNAL ;
    PORT
      LAYER M5 ;
        RECT  26.256 56.076 26.28 56.16 ;
    END
  END cfg_data[6]
  PIN cfg_data[70]
    DIRECTION INPUT ;
    USE SIGNAL ;
    PORT
      LAYER M5 ;
        RECT  45.456 56.076 45.48 56.16 ;
    END
  END cfg_data[70]
  PIN cfg_data[71]
    DIRECTION INPUT ;
    USE SIGNAL ;
    PORT
      LAYER M5 ;
        RECT  45.552 56.076 45.576 56.16 ;
    END
  END cfg_data[71]
  PIN cfg_data[72]
    DIRECTION INPUT ;
    USE SIGNAL ;
    PORT
      LAYER M5 ;
        RECT  45.648 56.076 45.672 56.16 ;
    END
  END cfg_data[72]
  PIN cfg_data[73]
    DIRECTION INPUT ;
    USE SIGNAL ;
    PORT
      LAYER M5 ;
        RECT  45.744 56.076 45.768 56.16 ;
    END
  END cfg_data[73]
  PIN cfg_data[74]
    DIRECTION INPUT ;
    USE SIGNAL ;
    PORT
      LAYER M5 ;
        RECT  45.84 56.076 45.864 56.16 ;
    END
  END cfg_data[74]
  PIN cfg_data[75]
    DIRECTION INPUT ;
    USE SIGNAL ;
    PORT
      LAYER M5 ;
        RECT  45.936 56.076 45.96 56.16 ;
    END
  END cfg_data[75]
  PIN cfg_data[76]
    DIRECTION INPUT ;
    USE SIGNAL ;
    PORT
      LAYER M5 ;
        RECT  46.032 56.076 46.056 56.16 ;
    END
  END cfg_data[76]
  PIN cfg_data[77]
    DIRECTION INPUT ;
    USE SIGNAL ;
    PORT
      LAYER M5 ;
        RECT  46.128 56.076 46.152 56.16 ;
    END
  END cfg_data[77]
  PIN cfg_data[78]
    DIRECTION INPUT ;
    USE SIGNAL ;
    PORT
      LAYER M5 ;
        RECT  46.224 56.076 46.248 56.16 ;
    END
  END cfg_data[78]
  PIN cfg_data[79]
    DIRECTION INPUT ;
    USE SIGNAL ;
    PORT
      LAYER M5 ;
        RECT  46.32 56.076 46.344 56.16 ;
    END
  END cfg_data[79]
  PIN cfg_data[7]
    DIRECTION INPUT ;
    USE SIGNAL ;
    PORT
      LAYER M5 ;
        RECT  26.352 56.076 26.376 56.16 ;
    END
  END cfg_data[7]
  PIN cfg_data[80]
    DIRECTION INPUT ;
    USE SIGNAL ;
    PORT
      LAYER M5 ;
        RECT  46.416 56.076 46.44 56.16 ;
    END
  END cfg_data[80]
  PIN cfg_data[81]
    DIRECTION INPUT ;
    USE SIGNAL ;
    PORT
      LAYER M5 ;
        RECT  46.512 56.076 46.536 56.16 ;
    END
  END cfg_data[81]
  PIN cfg_data[82]
    DIRECTION INPUT ;
    USE SIGNAL ;
    PORT
      LAYER M5 ;
        RECT  46.608 56.076 46.632 56.16 ;
    END
  END cfg_data[82]
  PIN cfg_data[83]
    DIRECTION INPUT ;
    USE SIGNAL ;
    PORT
      LAYER M5 ;
        RECT  46.704 56.076 46.728 56.16 ;
    END
  END cfg_data[83]
  PIN cfg_data[84]
    DIRECTION INPUT ;
    USE SIGNAL ;
    PORT
      LAYER M5 ;
        RECT  62.928 56.076 62.952 56.16 ;
    END
  END cfg_data[84]
  PIN cfg_data[85]
    DIRECTION INPUT ;
    USE SIGNAL ;
    PORT
      LAYER M5 ;
        RECT  63.024 56.076 63.048 56.16 ;
    END
  END cfg_data[85]
  PIN cfg_data[86]
    DIRECTION INPUT ;
    USE SIGNAL ;
    PORT
      LAYER M5 ;
        RECT  63.12 56.076 63.144 56.16 ;
    END
  END cfg_data[86]
  PIN cfg_data[87]
    DIRECTION INPUT ;
    USE SIGNAL ;
    PORT
      LAYER M5 ;
        RECT  63.216 56.076 63.24 56.16 ;
    END
  END cfg_data[87]
  PIN cfg_data[88]
    DIRECTION INPUT ;
    USE SIGNAL ;
    PORT
      LAYER M5 ;
        RECT  63.312 56.076 63.336 56.16 ;
    END
  END cfg_data[88]
  PIN cfg_data[89]
    DIRECTION INPUT ;
    USE SIGNAL ;
    PORT
      LAYER M5 ;
        RECT  63.408 56.076 63.432 56.16 ;
    END
  END cfg_data[89]
  PIN cfg_data[8]
    DIRECTION INPUT ;
    USE SIGNAL ;
    PORT
      LAYER M5 ;
        RECT  26.448 56.076 26.472 56.16 ;
    END
  END cfg_data[8]
  PIN cfg_data[90]
    DIRECTION INPUT ;
    USE SIGNAL ;
    PORT
      LAYER M5 ;
        RECT  63.504 56.076 63.528 56.16 ;
    END
  END cfg_data[90]
  PIN cfg_data[91]
    DIRECTION INPUT ;
    USE SIGNAL ;
    PORT
      LAYER M5 ;
        RECT  63.6 56.076 63.624 56.16 ;
    END
  END cfg_data[91]
  PIN cfg_data[92]
    DIRECTION INPUT ;
    USE SIGNAL ;
    PORT
      LAYER M5 ;
        RECT  63.696 56.076 63.72 56.16 ;
    END
  END cfg_data[92]
  PIN cfg_data[93]
    DIRECTION INPUT ;
    USE SIGNAL ;
    PORT
      LAYER M5 ;
        RECT  63.792 56.076 63.816 56.16 ;
    END
  END cfg_data[93]
  PIN cfg_data[94]
    DIRECTION INPUT ;
    USE SIGNAL ;
    PORT
      LAYER M5 ;
        RECT  63.888 56.076 63.912 56.16 ;
    END
  END cfg_data[94]
  PIN cfg_data[95]
    DIRECTION INPUT ;
    USE SIGNAL ;
    PORT
      LAYER M5 ;
        RECT  63.984 56.076 64.008 56.16 ;
    END
  END cfg_data[95]
  PIN cfg_data[96]
    DIRECTION INPUT ;
    USE SIGNAL ;
    PORT
      LAYER M5 ;
        RECT  64.08 56.076 64.104 56.16 ;
    END
  END cfg_data[96]
  PIN cfg_data[97]
    DIRECTION INPUT ;
    USE SIGNAL ;
    PORT
      LAYER M5 ;
        RECT  64.176 56.076 64.2 56.16 ;
    END
  END cfg_data[97]
  PIN cfg_data[98]
    DIRECTION INPUT ;
    USE SIGNAL ;
    PORT
      LAYER M5 ;
        RECT  64.272 56.076 64.296 56.16 ;
    END
  END cfg_data[98]
  PIN cfg_data[99]
    DIRECTION INPUT ;
    USE SIGNAL ;
    PORT
      LAYER M5 ;
        RECT  64.368 56.076 64.392 56.16 ;
    END
  END cfg_data[99]
  PIN cfg_data[9]
    DIRECTION INPUT ;
    USE SIGNAL ;
    PORT
      LAYER M5 ;
        RECT  26.544 56.076 26.568 56.16 ;
    END
  END cfg_data[9]
  PIN cfg_target[0]
    DIRECTION INPUT ;
    USE SIGNAL ;
    PORT
      LAYER M5 ;
        RECT  47.952 56.076 47.976 56.16 ;
    END
  END cfg_target[0]
  PIN cfg_target[1]
    DIRECTION INPUT ;
    USE SIGNAL ;
    PORT
      LAYER M5 ;
        RECT  48.048 56.076 48.072 56.16 ;
    END
  END cfg_target[1]
  PIN cfg_target[2]
    DIRECTION INPUT ;
    USE SIGNAL ;
    PORT
      LAYER M5 ;
        RECT  48.144 56.076 48.168 56.16 ;
    END
  END cfg_target[2]
  PIN cfg_target[3]
    DIRECTION INPUT ;
    USE SIGNAL ;
    PORT
      LAYER M5 ;
        RECT  48.24 56.076 48.264 56.16 ;
    END
  END cfg_target[3]
  PIN cfg_target[4]
    DIRECTION INPUT ;
    USE SIGNAL ;
    PORT
      LAYER M5 ;
        RECT  48.336 56.076 48.36 56.16 ;
    END
  END cfg_target[4]
  PIN cfg_target[5]
    DIRECTION INPUT ;
    USE SIGNAL ;
    PORT
      LAYER M5 ;
        RECT  48.432 56.076 48.456 56.16 ;
    END
  END cfg_target[5]
  PIN cfg_target[6]
    DIRECTION INPUT ;
    USE SIGNAL ;
    PORT
      LAYER M5 ;
        RECT  48.528 56.076 48.552 56.16 ;
    END
  END cfg_target[6]
  PIN cfg_target[7]
    DIRECTION INPUT ;
    USE SIGNAL ;
    PORT
      LAYER M5 ;
        RECT  48.624 56.076 48.648 56.16 ;
    END
  END cfg_target[7]
  PIN cfg_v
    DIRECTION INPUT ;
    USE SIGNAL ;
    PORT
      LAYER M5 ;
        RECT  48.72 56.076 48.744 56.16 ;
    END
  END cfg_v
  PIN clk
    DIRECTION INPUT ;
    USE SIGNAL ;
    PORT
      LAYER M5 ;
        RECT  48.816 56.076 48.84 56.16 ;
    END
  END clk
  PIN configured
    DIRECTION OUTPUT ;
    USE SIGNAL ;
    PORT
      LAYER M5 ;
        RECT  48.912 56.076 48.936 56.16 ;
    END
  END configured
  PIN desc_base[0]
    DIRECTION INPUT ;
    USE SIGNAL ;
    PORT
      LAYER M5 ;
        RECT  49.008 56.076 49.032 56.16 ;
    END
  END desc_base[0]
  PIN desc_base[10]
    DIRECTION INPUT ;
    USE SIGNAL ;
    PORT
      LAYER M5 ;
        RECT  5.424 56.076 5.448 56.16 ;
    END
  END desc_base[10]
  PIN desc_base[11]
    DIRECTION INPUT ;
    USE SIGNAL ;
    PORT
      LAYER M5 ;
        RECT  5.52 56.076 5.544 56.16 ;
    END
  END desc_base[11]
  PIN desc_base[1]
    DIRECTION INPUT ;
    USE SIGNAL ;
    PORT
      LAYER M5 ;
        RECT  49.104 56.076 49.128 56.16 ;
    END
  END desc_base[1]
  PIN desc_base[2]
    DIRECTION INPUT ;
    USE SIGNAL ;
    PORT
      LAYER M5 ;
        RECT  49.2 56.076 49.224 56.16 ;
    END
  END desc_base[2]
  PIN desc_base[3]
    DIRECTION INPUT ;
    USE SIGNAL ;
    PORT
      LAYER M5 ;
        RECT  49.296 56.076 49.32 56.16 ;
    END
  END desc_base[3]
  PIN desc_base[4]
    DIRECTION INPUT ;
    USE SIGNAL ;
    PORT
      LAYER M5 ;
        RECT  49.392 56.076 49.416 56.16 ;
    END
  END desc_base[4]
  PIN desc_base[5]
    DIRECTION INPUT ;
    USE SIGNAL ;
    PORT
      LAYER M5 ;
        RECT  49.488 56.076 49.512 56.16 ;
    END
  END desc_base[5]
  PIN desc_base[6]
    DIRECTION INPUT ;
    USE SIGNAL ;
    PORT
      LAYER M5 ;
        RECT  49.584 56.076 49.608 56.16 ;
    END
  END desc_base[6]
  PIN desc_base[7]
    DIRECTION INPUT ;
    USE SIGNAL ;
    PORT
      LAYER M5 ;
        RECT  49.68 56.076 49.704 56.16 ;
    END
  END desc_base[7]
  PIN desc_base[8]
    DIRECTION INPUT ;
    USE SIGNAL ;
    PORT
      LAYER M5 ;
        RECT  49.776 56.076 49.8 56.16 ;
    END
  END desc_base[8]
  PIN desc_base[9]
    DIRECTION INPUT ;
    USE SIGNAL ;
    PORT
      LAYER M5 ;
        RECT  5.328 56.076 5.352 56.16 ;
    END
  END desc_base[9]
  PIN desc_limit[0]
    DIRECTION INPUT ;
    USE SIGNAL ;
    PORT
      LAYER M5 ;
        RECT  5.616 56.076 5.64 56.16 ;
    END
  END desc_limit[0]
  PIN desc_limit[10]
    DIRECTION INPUT ;
    USE SIGNAL ;
    PORT
      LAYER M5 ;
        RECT  6.576 56.076 6.6 56.16 ;
    END
  END desc_limit[10]
  PIN desc_limit[11]
    DIRECTION INPUT ;
    USE SIGNAL ;
    PORT
      LAYER M5 ;
        RECT  6.672 56.076 6.696 56.16 ;
    END
  END desc_limit[11]
  PIN desc_limit[12]
    DIRECTION INPUT ;
    USE SIGNAL ;
    PORT
      LAYER M5 ;
        RECT  6.768 56.076 6.792 56.16 ;
    END
  END desc_limit[12]
  PIN desc_limit[1]
    DIRECTION INPUT ;
    USE SIGNAL ;
    PORT
      LAYER M5 ;
        RECT  5.712 56.076 5.736 56.16 ;
    END
  END desc_limit[1]
  PIN desc_limit[2]
    DIRECTION INPUT ;
    USE SIGNAL ;
    PORT
      LAYER M5 ;
        RECT  5.808 56.076 5.832 56.16 ;
    END
  END desc_limit[2]
  PIN desc_limit[3]
    DIRECTION INPUT ;
    USE SIGNAL ;
    PORT
      LAYER M5 ;
        RECT  5.904 56.076 5.928 56.16 ;
    END
  END desc_limit[3]
  PIN desc_limit[4]
    DIRECTION INPUT ;
    USE SIGNAL ;
    PORT
      LAYER M5 ;
        RECT  6 56.076 6.024 56.16 ;
    END
  END desc_limit[4]
  PIN desc_limit[5]
    DIRECTION INPUT ;
    USE SIGNAL ;
    PORT
      LAYER M5 ;
        RECT  6.096 56.076 6.12 56.16 ;
    END
  END desc_limit[5]
  PIN desc_limit[6]
    DIRECTION INPUT ;
    USE SIGNAL ;
    PORT
      LAYER M5 ;
        RECT  6.192 56.076 6.216 56.16 ;
    END
  END desc_limit[6]
  PIN desc_limit[7]
    DIRECTION INPUT ;
    USE SIGNAL ;
    PORT
      LAYER M5 ;
        RECT  6.288 56.076 6.312 56.16 ;
    END
  END desc_limit[7]
  PIN desc_limit[8]
    DIRECTION INPUT ;
    USE SIGNAL ;
    PORT
      LAYER M5 ;
        RECT  6.384 56.076 6.408 56.16 ;
    END
  END desc_limit[8]
  PIN desc_limit[9]
    DIRECTION INPUT ;
    USE SIGNAL ;
    PORT
      LAYER M5 ;
        RECT  6.48 56.076 6.504 56.16 ;
    END
  END desc_limit[9]
  PIN desc_loops[0]
    DIRECTION INPUT ;
    USE SIGNAL ;
    PORT
      LAYER M5 ;
        RECT  6.864 56.076 6.888 56.16 ;
    END
  END desc_loops[0]
  PIN desc_loops[10]
    DIRECTION INPUT ;
    USE SIGNAL ;
    PORT
      LAYER M5 ;
        RECT  7.824 56.076 7.848 56.16 ;
    END
  END desc_loops[10]
  PIN desc_loops[11]
    DIRECTION INPUT ;
    USE SIGNAL ;
    PORT
      LAYER M5 ;
        RECT  7.92 56.076 7.944 56.16 ;
    END
  END desc_loops[11]
  PIN desc_loops[12]
    DIRECTION INPUT ;
    USE SIGNAL ;
    PORT
      LAYER M5 ;
        RECT  8.016 56.076 8.04 56.16 ;
    END
  END desc_loops[12]
  PIN desc_loops[13]
    DIRECTION INPUT ;
    USE SIGNAL ;
    PORT
      LAYER M5 ;
        RECT  8.112 56.076 8.136 56.16 ;
    END
  END desc_loops[13]
  PIN desc_loops[14]
    DIRECTION INPUT ;
    USE SIGNAL ;
    PORT
      LAYER M5 ;
        RECT  8.208 56.076 8.232 56.16 ;
    END
  END desc_loops[14]
  PIN desc_loops[15]
    DIRECTION INPUT ;
    USE SIGNAL ;
    PORT
      LAYER M5 ;
        RECT  8.304 56.076 8.328 56.16 ;
    END
  END desc_loops[15]
  PIN desc_loops[1]
    DIRECTION INPUT ;
    USE SIGNAL ;
    PORT
      LAYER M5 ;
        RECT  6.96 56.076 6.984 56.16 ;
    END
  END desc_loops[1]
  PIN desc_loops[2]
    DIRECTION INPUT ;
    USE SIGNAL ;
    PORT
      LAYER M5 ;
        RECT  7.056 56.076 7.08 56.16 ;
    END
  END desc_loops[2]
  PIN desc_loops[3]
    DIRECTION INPUT ;
    USE SIGNAL ;
    PORT
      LAYER M5 ;
        RECT  7.152 56.076 7.176 56.16 ;
    END
  END desc_loops[3]
  PIN desc_loops[4]
    DIRECTION INPUT ;
    USE SIGNAL ;
    PORT
      LAYER M5 ;
        RECT  7.248 56.076 7.272 56.16 ;
    END
  END desc_loops[4]
  PIN desc_loops[5]
    DIRECTION INPUT ;
    USE SIGNAL ;
    PORT
      LAYER M5 ;
        RECT  7.344 56.076 7.368 56.16 ;
    END
  END desc_loops[5]
  PIN desc_loops[6]
    DIRECTION INPUT ;
    USE SIGNAL ;
    PORT
      LAYER M5 ;
        RECT  7.44 56.076 7.464 56.16 ;
    END
  END desc_loops[6]
  PIN desc_loops[7]
    DIRECTION INPUT ;
    USE SIGNAL ;
    PORT
      LAYER M5 ;
        RECT  7.536 56.076 7.56 56.16 ;
    END
  END desc_loops[7]
  PIN desc_loops[8]
    DIRECTION INPUT ;
    USE SIGNAL ;
    PORT
      LAYER M5 ;
        RECT  7.632 56.076 7.656 56.16 ;
    END
  END desc_loops[8]
  PIN desc_loops[9]
    DIRECTION INPUT ;
    USE SIGNAL ;
    PORT
      LAYER M5 ;
        RECT  7.728 56.076 7.752 56.16 ;
    END
  END desc_loops[9]
  PIN desc_v
    DIRECTION INPUT ;
    USE SIGNAL ;
    PORT
      LAYER M5 ;
        RECT  75.984 56.076 76.008 56.16 ;
    END
  END desc_v
  PIN fault
    DIRECTION OUTPUT ;
    USE SIGNAL ;
    PORT
      LAYER M5 ;
        RECT  76.08 56.076 76.104 56.16 ;
    END
  END fault
  PIN fault_cause[0]
    DIRECTION OUTPUT ;
    USE SIGNAL ;
    PORT
      LAYER M5 ;
        RECT  76.176 56.076 76.2 56.16 ;
    END
  END fault_cause[0]
  PIN fault_cause[10]
    DIRECTION OUTPUT ;
    USE SIGNAL ;
    PORT
      LAYER M5 ;
        RECT  77.136 56.076 77.16 56.16 ;
    END
  END fault_cause[10]
  PIN fault_cause[11]
    DIRECTION OUTPUT ;
    USE SIGNAL ;
    PORT
      LAYER M5 ;
        RECT  77.232 56.076 77.256 56.16 ;
    END
  END fault_cause[11]
  PIN fault_cause[12]
    DIRECTION OUTPUT ;
    USE SIGNAL ;
    PORT
      LAYER M5 ;
        RECT  77.328 56.076 77.352 56.16 ;
    END
  END fault_cause[12]
  PIN fault_cause[13]
    DIRECTION OUTPUT ;
    USE SIGNAL ;
    PORT
      LAYER M5 ;
        RECT  77.424 56.076 77.448 56.16 ;
    END
  END fault_cause[13]
  PIN fault_cause[14]
    DIRECTION OUTPUT ;
    USE SIGNAL ;
    PORT
      LAYER M5 ;
        RECT  77.52 56.076 77.544 56.16 ;
    END
  END fault_cause[14]
  PIN fault_cause[15]
    DIRECTION OUTPUT ;
    USE SIGNAL ;
    PORT
      LAYER M5 ;
        RECT  77.616 56.076 77.64 56.16 ;
    END
  END fault_cause[15]
  PIN fault_cause[1]
    DIRECTION OUTPUT ;
    USE SIGNAL ;
    PORT
      LAYER M5 ;
        RECT  76.272 56.076 76.296 56.16 ;
    END
  END fault_cause[1]
  PIN fault_cause[2]
    DIRECTION OUTPUT ;
    USE SIGNAL ;
    PORT
      LAYER M5 ;
        RECT  76.368 56.076 76.392 56.16 ;
    END
  END fault_cause[2]
  PIN fault_cause[3]
    DIRECTION OUTPUT ;
    USE SIGNAL ;
    PORT
      LAYER M5 ;
        RECT  76.464 56.076 76.488 56.16 ;
    END
  END fault_cause[3]
  PIN fault_cause[4]
    DIRECTION OUTPUT ;
    USE SIGNAL ;
    PORT
      LAYER M5 ;
        RECT  76.56 56.076 76.584 56.16 ;
    END
  END fault_cause[4]
  PIN fault_cause[5]
    DIRECTION OUTPUT ;
    USE SIGNAL ;
    PORT
      LAYER M5 ;
        RECT  76.656 56.076 76.68 56.16 ;
    END
  END fault_cause[5]
  PIN fault_cause[6]
    DIRECTION OUTPUT ;
    USE SIGNAL ;
    PORT
      LAYER M5 ;
        RECT  76.752 56.076 76.776 56.16 ;
    END
  END fault_cause[6]
  PIN fault_cause[7]
    DIRECTION OUTPUT ;
    USE SIGNAL ;
    PORT
      LAYER M5 ;
        RECT  76.848 56.076 76.872 56.16 ;
    END
  END fault_cause[7]
  PIN fault_cause[8]
    DIRECTION OUTPUT ;
    USE SIGNAL ;
    PORT
      LAYER M5 ;
        RECT  76.944 56.076 76.968 56.16 ;
    END
  END fault_cause[8]
  PIN fault_cause[9]
    DIRECTION OUTPUT ;
    USE SIGNAL ;
    PORT
      LAYER M5 ;
        RECT  77.04 56.076 77.064 56.16 ;
    END
  END fault_cause[9]
  PIN init_busy
    DIRECTION OUTPUT ;
    USE SIGNAL ;
    PORT
      LAYER M5 ;
        RECT  77.712 56.076 77.736 56.16 ;
    END
  END init_busy
  PIN issuer_busy
    DIRECTION INPUT ;
    USE SIGNAL ;
    PORT
      LAYER M5 ;
        RECT  51.408 0 51.432 0.084 ;
    END
  END issuer_busy
  PIN issuer_cfg[0]
    DIRECTION OUTPUT ;
    USE SIGNAL ;
    PORT
      LAYER M5 ;
        RECT  51.504 0 51.528 0.084 ;
    END
  END issuer_cfg[0]
  PIN issuer_cfg[10]
    DIRECTION OUTPUT ;
    USE SIGNAL ;
    PORT
      LAYER M5 ;
        RECT  52.464 0 52.488 0.084 ;
    END
  END issuer_cfg[10]
  PIN issuer_cfg[11]
    DIRECTION OUTPUT ;
    USE SIGNAL ;
    PORT
      LAYER M5 ;
        RECT  52.56 0 52.584 0.084 ;
    END
  END issuer_cfg[11]
  PIN issuer_cfg[12]
    DIRECTION OUTPUT ;
    USE SIGNAL ;
    PORT
      LAYER M5 ;
        RECT  52.656 0 52.68 0.084 ;
    END
  END issuer_cfg[12]
  PIN issuer_cfg[13]
    DIRECTION OUTPUT ;
    USE SIGNAL ;
    PORT
      LAYER M5 ;
        RECT  52.752 0 52.776 0.084 ;
    END
  END issuer_cfg[13]
  PIN issuer_cfg[14]
    DIRECTION OUTPUT ;
    USE SIGNAL ;
    PORT
      LAYER M5 ;
        RECT  52.848 0 52.872 0.084 ;
    END
  END issuer_cfg[14]
  PIN issuer_cfg[15]
    DIRECTION OUTPUT ;
    USE SIGNAL ;
    PORT
      LAYER M5 ;
        RECT  52.944 0 52.968 0.084 ;
    END
  END issuer_cfg[15]
  PIN issuer_cfg[16]
    DIRECTION OUTPUT ;
    USE SIGNAL ;
    PORT
      LAYER M5 ;
        RECT  53.04 0 53.064 0.084 ;
    END
  END issuer_cfg[16]
  PIN issuer_cfg[17]
    DIRECTION OUTPUT ;
    USE SIGNAL ;
    PORT
      LAYER M5 ;
        RECT  53.136 0 53.16 0.084 ;
    END
  END issuer_cfg[17]
  PIN issuer_cfg[18]
    DIRECTION OUTPUT ;
    USE SIGNAL ;
    PORT
      LAYER M5 ;
        RECT  53.232 0 53.256 0.084 ;
    END
  END issuer_cfg[18]
  PIN issuer_cfg[19]
    DIRECTION OUTPUT ;
    USE SIGNAL ;
    PORT
      LAYER M5 ;
        RECT  53.328 0 53.352 0.084 ;
    END
  END issuer_cfg[19]
  PIN issuer_cfg[1]
    DIRECTION OUTPUT ;
    USE SIGNAL ;
    PORT
      LAYER M5 ;
        RECT  51.6 0 51.624 0.084 ;
    END
  END issuer_cfg[1]
  PIN issuer_cfg[20]
    DIRECTION OUTPUT ;
    USE SIGNAL ;
    PORT
      LAYER M5 ;
        RECT  53.424 0 53.448 0.084 ;
    END
  END issuer_cfg[20]
  PIN issuer_cfg[21]
    DIRECTION OUTPUT ;
    USE SIGNAL ;
    PORT
      LAYER M5 ;
        RECT  53.52 0 53.544 0.084 ;
    END
  END issuer_cfg[21]
  PIN issuer_cfg[22]
    DIRECTION OUTPUT ;
    USE SIGNAL ;
    PORT
      LAYER M5 ;
        RECT  53.616 0 53.64 0.084 ;
    END
  END issuer_cfg[22]
  PIN issuer_cfg[23]
    DIRECTION OUTPUT ;
    USE SIGNAL ;
    PORT
      LAYER M5 ;
        RECT  53.712 0 53.736 0.084 ;
    END
  END issuer_cfg[23]
  PIN issuer_cfg[24]
    DIRECTION OUTPUT ;
    USE SIGNAL ;
    PORT
      LAYER M5 ;
        RECT  53.808 0 53.832 0.084 ;
    END
  END issuer_cfg[24]
  PIN issuer_cfg[25]
    DIRECTION OUTPUT ;
    USE SIGNAL ;
    PORT
      LAYER M5 ;
        RECT  53.904 0 53.928 0.084 ;
    END
  END issuer_cfg[25]
  PIN issuer_cfg[26]
    DIRECTION OUTPUT ;
    USE SIGNAL ;
    PORT
      LAYER M5 ;
        RECT  54 0 54.024 0.084 ;
    END
  END issuer_cfg[26]
  PIN issuer_cfg[27]
    DIRECTION OUTPUT ;
    USE SIGNAL ;
    PORT
      LAYER M5 ;
        RECT  54.096 0 54.12 0.084 ;
    END
  END issuer_cfg[27]
  PIN issuer_cfg[28]
    DIRECTION OUTPUT ;
    USE SIGNAL ;
    PORT
      LAYER M5 ;
        RECT  54.192 0 54.216 0.084 ;
    END
  END issuer_cfg[28]
  PIN issuer_cfg[29]
    DIRECTION OUTPUT ;
    USE SIGNAL ;
    PORT
      LAYER M5 ;
        RECT  54.288 0 54.312 0.084 ;
    END
  END issuer_cfg[29]
  PIN issuer_cfg[2]
    DIRECTION OUTPUT ;
    USE SIGNAL ;
    PORT
      LAYER M5 ;
        RECT  51.696 0 51.72 0.084 ;
    END
  END issuer_cfg[2]
  PIN issuer_cfg[30]
    DIRECTION OUTPUT ;
    USE SIGNAL ;
    PORT
      LAYER M5 ;
        RECT  54.384 0 54.408 0.084 ;
    END
  END issuer_cfg[30]
  PIN issuer_cfg[31]
    DIRECTION OUTPUT ;
    USE SIGNAL ;
    PORT
      LAYER M5 ;
        RECT  68.88 0 68.904 0.084 ;
    END
  END issuer_cfg[31]
  PIN issuer_cfg[32]
    DIRECTION OUTPUT ;
    USE SIGNAL ;
    PORT
      LAYER M5 ;
        RECT  68.976 0 69 0.084 ;
    END
  END issuer_cfg[32]
  PIN issuer_cfg[33]
    DIRECTION OUTPUT ;
    USE SIGNAL ;
    PORT
      LAYER M5 ;
        RECT  69.072 0 69.096 0.084 ;
    END
  END issuer_cfg[33]
  PIN issuer_cfg[34]
    DIRECTION OUTPUT ;
    USE SIGNAL ;
    PORT
      LAYER M5 ;
        RECT  69.168 0 69.192 0.084 ;
    END
  END issuer_cfg[34]
  PIN issuer_cfg[35]
    DIRECTION OUTPUT ;
    USE SIGNAL ;
    PORT
      LAYER M5 ;
        RECT  69.264 0 69.288 0.084 ;
    END
  END issuer_cfg[35]
  PIN issuer_cfg[36]
    DIRECTION OUTPUT ;
    USE SIGNAL ;
    PORT
      LAYER M5 ;
        RECT  69.36 0 69.384 0.084 ;
    END
  END issuer_cfg[36]
  PIN issuer_cfg[3]
    DIRECTION OUTPUT ;
    USE SIGNAL ;
    PORT
      LAYER M5 ;
        RECT  51.792 0 51.816 0.084 ;
    END
  END issuer_cfg[3]
  PIN issuer_cfg[4]
    DIRECTION OUTPUT ;
    USE SIGNAL ;
    PORT
      LAYER M5 ;
        RECT  51.888 0 51.912 0.084 ;
    END
  END issuer_cfg[4]
  PIN issuer_cfg[5]
    DIRECTION OUTPUT ;
    USE SIGNAL ;
    PORT
      LAYER M5 ;
        RECT  51.984 0 52.008 0.084 ;
    END
  END issuer_cfg[5]
  PIN issuer_cfg[6]
    DIRECTION OUTPUT ;
    USE SIGNAL ;
    PORT
      LAYER M5 ;
        RECT  52.08 0 52.104 0.084 ;
    END
  END issuer_cfg[6]
  PIN issuer_cfg[7]
    DIRECTION OUTPUT ;
    USE SIGNAL ;
    PORT
      LAYER M5 ;
        RECT  52.176 0 52.2 0.084 ;
    END
  END issuer_cfg[7]
  PIN issuer_cfg[8]
    DIRECTION OUTPUT ;
    USE SIGNAL ;
    PORT
      LAYER M5 ;
        RECT  52.272 0 52.296 0.084 ;
    END
  END issuer_cfg[8]
  PIN issuer_cfg[9]
    DIRECTION OUTPUT ;
    USE SIGNAL ;
    PORT
      LAYER M5 ;
        RECT  52.368 0 52.392 0.084 ;
    END
  END issuer_cfg[9]
  PIN issuer_fault
    DIRECTION INPUT ;
    USE SIGNAL ;
    PORT
      LAYER M5 ;
        RECT  69.456 0 69.48 0.084 ;
    END
  END issuer_fault
  PIN issuer_start
    DIRECTION OUTPUT ;
    USE SIGNAL ;
    PORT
      LAYER M5 ;
        RECT  69.552 0 69.576 0.084 ;
    END
  END issuer_start
  PIN issuer_start_pc[0]
    DIRECTION OUTPUT ;
    USE SIGNAL ;
    PORT
      LAYER M5 ;
        RECT  69.648 0 69.672 0.084 ;
    END
  END issuer_start_pc[0]
  PIN issuer_start_pc[1]
    DIRECTION OUTPUT ;
    USE SIGNAL ;
    PORT
      LAYER M5 ;
        RECT  69.744 0 69.768 0.084 ;
    END
  END issuer_start_pc[1]
  PIN issuer_start_pc[2]
    DIRECTION OUTPUT ;
    USE SIGNAL ;
    PORT
      LAYER M5 ;
        RECT  69.84 0 69.864 0.084 ;
    END
  END issuer_start_pc[2]
  PIN issuer_start_pc[3]
    DIRECTION OUTPUT ;
    USE SIGNAL ;
    PORT
      LAYER M5 ;
        RECT  69.936 0 69.96 0.084 ;
    END
  END issuer_start_pc[3]
  PIN issuer_start_pc[4]
    DIRECTION OUTPUT ;
    USE SIGNAL ;
    PORT
      LAYER M5 ;
        RECT  70.032 0 70.056 0.084 ;
    END
  END issuer_start_pc[4]
  PIN issuer_start_pc[5]
    DIRECTION OUTPUT ;
    USE SIGNAL ;
    PORT
      LAYER M5 ;
        RECT  70.128 0 70.152 0.084 ;
    END
  END issuer_start_pc[5]
  PIN issuer_uop_pc[0]
    DIRECTION INPUT ;
    USE SIGNAL ;
    PORT
      LAYER M5 ;
        RECT  70.224 0 70.248 0.084 ;
    END
  END issuer_uop_pc[0]
  PIN issuer_uop_pc[1]
    DIRECTION INPUT ;
    USE SIGNAL ;
    PORT
      LAYER M5 ;
        RECT  70.32 0 70.344 0.084 ;
    END
  END issuer_uop_pc[1]
  PIN issuer_uop_pc[2]
    DIRECTION INPUT ;
    USE SIGNAL ;
    PORT
      LAYER M5 ;
        RECT  70.416 0 70.44 0.084 ;
    END
  END issuer_uop_pc[2]
  PIN issuer_uop_pc[3]
    DIRECTION INPUT ;
    USE SIGNAL ;
    PORT
      LAYER M5 ;
        RECT  70.512 0 70.536 0.084 ;
    END
  END issuer_uop_pc[3]
  PIN issuer_uop_pc[4]
    DIRECTION INPUT ;
    USE SIGNAL ;
    PORT
      LAYER M5 ;
        RECT  70.608 0 70.632 0.084 ;
    END
  END issuer_uop_pc[4]
  PIN issuer_uop_pc[5]
    DIRECTION INPUT ;
    USE SIGNAL ;
    PORT
      LAYER M5 ;
        RECT  70.704 0 70.728 0.084 ;
    END
  END issuer_uop_pc[5]
  PIN issuer_uop_v
    DIRECTION INPUT ;
    USE SIGNAL ;
    PORT
      LAYER M5 ;
        RECT  70.8 0 70.824 0.084 ;
    END
  END issuer_uop_v
  PIN launch_v
    DIRECTION INPUT ;
    USE SIGNAL ;
    PORT
      LAYER M5 ;
        RECT  77.808 56.076 77.832 56.16 ;
    END
  END launch_v
  PIN link_abort[0]
    DIRECTION INPUT ;
    USE SIGNAL ;
    PORT
      LAYER M4 ;
        RECT  0 16.656 0.084 16.68 ;
    END
  END link_abort[0]
  PIN program_active
    DIRECTION INPUT ;
    USE SIGNAL ;
    PORT
      LAYER M5 ;
        RECT  70.896 0 70.92 0.084 ;
    END
  END program_active
  PIN program_fault
    DIRECTION OUTPUT ;
    USE SIGNAL ;
    PORT
      LAYER M5 ;
        RECT  77.904 56.076 77.928 56.16 ;
    END
  END program_fault
  PIN protocol_fault
    DIRECTION INPUT ;
    USE SIGNAL ;
    PORT
      LAYER M4 ;
        RECT  81.996 7.728 82.08 7.752 ;
    END
  END protocol_fault
  PIN qid[0]
    DIRECTION INPUT ;
    USE SIGNAL ;
    PORT
      LAYER M5 ;
        RECT  78 56.076 78.024 56.16 ;
    END
  END qid[0]
  PIN qid[1]
    DIRECTION INPUT ;
    USE SIGNAL ;
    PORT
      LAYER M5 ;
        RECT  78.096 56.076 78.12 56.16 ;
    END
  END qid[1]
  PIN reduce_fault
    DIRECTION INPUT ;
    USE SIGNAL ;
    PORT
      LAYER M4 ;
        RECT  0 16.752 0.084 16.776 ;
    END
  END reduce_fault
  PIN ring_fault
    DIRECTION INPUT ;
    USE SIGNAL ;
    PORT
      LAYER M4 ;
        RECT  0 16.848 0.084 16.872 ;
    END
  END ring_fault
  PIN rst_n
    DIRECTION INPUT ;
    USE SIGNAL ;
    PORT
      LAYER M5 ;
        RECT  78.192 56.076 78.216 56.16 ;
    END
  END rst_n
  PIN select_fault[0]
    DIRECTION INPUT ;
    USE SIGNAL ;
    PORT
      LAYER M4 ;
        RECT  81.996 7.824 82.08 7.848 ;
    END
  END select_fault[0]
  PIN select_fault[10]
    DIRECTION INPUT ;
    USE SIGNAL ;
    PORT
      LAYER M4 ;
        RECT  81.996 8.784 82.08 8.808 ;
    END
  END select_fault[10]
  PIN select_fault[11]
    DIRECTION INPUT ;
    USE SIGNAL ;
    PORT
      LAYER M4 ;
        RECT  81.996 8.88 82.08 8.904 ;
    END
  END select_fault[11]
  PIN select_fault[12]
    DIRECTION INPUT ;
    USE SIGNAL ;
    PORT
      LAYER M4 ;
        RECT  81.996 8.976 82.08 9 ;
    END
  END select_fault[12]
  PIN select_fault[13]
    DIRECTION INPUT ;
    USE SIGNAL ;
    PORT
      LAYER M4 ;
        RECT  81.996 9.072 82.08 9.096 ;
    END
  END select_fault[13]
  PIN select_fault[14]
    DIRECTION INPUT ;
    USE SIGNAL ;
    PORT
      LAYER M4 ;
        RECT  81.996 9.168 82.08 9.192 ;
    END
  END select_fault[14]
  PIN select_fault[15]
    DIRECTION INPUT ;
    USE SIGNAL ;
    PORT
      LAYER M4 ;
        RECT  81.996 9.264 82.08 9.288 ;
    END
  END select_fault[15]
  PIN select_fault[16]
    DIRECTION INPUT ;
    USE SIGNAL ;
    PORT
      LAYER M4 ;
        RECT  81.996 9.36 82.08 9.384 ;
    END
  END select_fault[16]
  PIN select_fault[17]
    DIRECTION INPUT ;
    USE SIGNAL ;
    PORT
      LAYER M4 ;
        RECT  81.996 9.456 82.08 9.48 ;
    END
  END select_fault[17]
  PIN select_fault[1]
    DIRECTION INPUT ;
    USE SIGNAL ;
    PORT
      LAYER M4 ;
        RECT  81.996 7.92 82.08 7.944 ;
    END
  END select_fault[1]
  PIN select_fault[2]
    DIRECTION INPUT ;
    USE SIGNAL ;
    PORT
      LAYER M4 ;
        RECT  81.996 8.016 82.08 8.04 ;
    END
  END select_fault[2]
  PIN select_fault[3]
    DIRECTION INPUT ;
    USE SIGNAL ;
    PORT
      LAYER M4 ;
        RECT  81.996 8.112 82.08 8.136 ;
    END
  END select_fault[3]
  PIN select_fault[4]
    DIRECTION INPUT ;
    USE SIGNAL ;
    PORT
      LAYER M4 ;
        RECT  81.996 8.208 82.08 8.232 ;
    END
  END select_fault[4]
  PIN select_fault[5]
    DIRECTION INPUT ;
    USE SIGNAL ;
    PORT
      LAYER M4 ;
        RECT  81.996 8.304 82.08 8.328 ;
    END
  END select_fault[5]
  PIN select_fault[6]
    DIRECTION INPUT ;
    USE SIGNAL ;
    PORT
      LAYER M4 ;
        RECT  81.996 8.4 82.08 8.424 ;
    END
  END select_fault[6]
  PIN select_fault[7]
    DIRECTION INPUT ;
    USE SIGNAL ;
    PORT
      LAYER M4 ;
        RECT  81.996 8.496 82.08 8.52 ;
    END
  END select_fault[7]
  PIN select_fault[8]
    DIRECTION INPUT ;
    USE SIGNAL ;
    PORT
      LAYER M4 ;
        RECT  81.996 8.592 82.08 8.616 ;
    END
  END select_fault[8]
  PIN select_fault[9]
    DIRECTION INPUT ;
    USE SIGNAL ;
    PORT
      LAYER M4 ;
        RECT  81.996 8.688 82.08 8.712 ;
    END
  END select_fault[9]
  PIN tkm_del_slot[0]
    DIRECTION INPUT ;
    USE SIGNAL ;
    PORT
      LAYER M4 ;
        RECT  81.996 9.552 82.08 9.576 ;
    END
  END tkm_del_slot[0]
  PIN tkm_del_slot[1]
    DIRECTION INPUT ;
    USE SIGNAL ;
    PORT
      LAYER M4 ;
        RECT  81.996 9.648 82.08 9.672 ;
    END
  END tkm_del_slot[1]
  PIN tkm_del_slot[2]
    DIRECTION INPUT ;
    USE SIGNAL ;
    PORT
      LAYER M4 ;
        RECT  81.996 9.744 82.08 9.768 ;
    END
  END tkm_del_slot[2]
  PIN tkm_del_slot[3]
    DIRECTION INPUT ;
    USE SIGNAL ;
    PORT
      LAYER M4 ;
        RECT  81.996 9.84 82.08 9.864 ;
    END
  END tkm_del_slot[3]
  PIN tkm_dest_v[0]
    DIRECTION INPUT ;
    USE SIGNAL ;
    PORT
      LAYER M4 ;
        RECT  81.996 3.792 82.08 3.816 ;
    END
  END tkm_dest_v[0]
  PIN tkm_dest_v[1]
    DIRECTION INPUT ;
    USE SIGNAL ;
    PORT
      LAYER M4 ;
        RECT  81.996 3.888 82.08 3.912 ;
    END
  END tkm_dest_v[1]
  PIN tkm_dest_v[2]
    DIRECTION INPUT ;
    USE SIGNAL ;
    PORT
      LAYER M4 ;
        RECT  81.996 3.984 82.08 4.008 ;
    END
  END tkm_dest_v[2]
  PIN tkm_dest_v[3]
    DIRECTION INPUT ;
    USE SIGNAL ;
    PORT
      LAYER M4 ;
        RECT  81.996 4.08 82.08 4.104 ;
    END
  END tkm_dest_v[3]
  PIN tkm_start
    DIRECTION INPUT ;
    USE SIGNAL ;
    PORT
      LAYER M4 ;
        RECT  81.996 4.176 82.08 4.2 ;
    END
  END tkm_start
  PIN unavailable_fault[0]
    DIRECTION INPUT ;
    USE SIGNAL ;
    PORT
      LAYER M4 ;
        RECT  81.996 4.272 82.08 4.296 ;
    END
  END unavailable_fault[0]
  PIN unavailable_fault[10]
    DIRECTION INPUT ;
    USE SIGNAL ;
    PORT
      LAYER M4 ;
        RECT  81.996 5.232 82.08 5.256 ;
    END
  END unavailable_fault[10]
  PIN unavailable_fault[11]
    DIRECTION INPUT ;
    USE SIGNAL ;
    PORT
      LAYER M4 ;
        RECT  81.996 5.328 82.08 5.352 ;
    END
  END unavailable_fault[11]
  PIN unavailable_fault[12]
    DIRECTION INPUT ;
    USE SIGNAL ;
    PORT
      LAYER M4 ;
        RECT  81.996 5.424 82.08 5.448 ;
    END
  END unavailable_fault[12]
  PIN unavailable_fault[13]
    DIRECTION INPUT ;
    USE SIGNAL ;
    PORT
      LAYER M4 ;
        RECT  81.996 5.52 82.08 5.544 ;
    END
  END unavailable_fault[13]
  PIN unavailable_fault[14]
    DIRECTION INPUT ;
    USE SIGNAL ;
    PORT
      LAYER M4 ;
        RECT  81.996 5.616 82.08 5.64 ;
    END
  END unavailable_fault[14]
  PIN unavailable_fault[15]
    DIRECTION INPUT ;
    USE SIGNAL ;
    PORT
      LAYER M4 ;
        RECT  81.996 5.712 82.08 5.736 ;
    END
  END unavailable_fault[15]
  PIN unavailable_fault[16]
    DIRECTION INPUT ;
    USE SIGNAL ;
    PORT
      LAYER M4 ;
        RECT  81.996 5.808 82.08 5.832 ;
    END
  END unavailable_fault[16]
  PIN unavailable_fault[17]
    DIRECTION INPUT ;
    USE SIGNAL ;
    PORT
      LAYER M4 ;
        RECT  81.996 5.904 82.08 5.928 ;
    END
  END unavailable_fault[17]
  PIN unavailable_fault[1]
    DIRECTION INPUT ;
    USE SIGNAL ;
    PORT
      LAYER M4 ;
        RECT  81.996 4.368 82.08 4.392 ;
    END
  END unavailable_fault[1]
  PIN unavailable_fault[2]
    DIRECTION INPUT ;
    USE SIGNAL ;
    PORT
      LAYER M4 ;
        RECT  81.996 4.464 82.08 4.488 ;
    END
  END unavailable_fault[2]
  PIN unavailable_fault[3]
    DIRECTION INPUT ;
    USE SIGNAL ;
    PORT
      LAYER M4 ;
        RECT  81.996 4.56 82.08 4.584 ;
    END
  END unavailable_fault[3]
  PIN unavailable_fault[4]
    DIRECTION INPUT ;
    USE SIGNAL ;
    PORT
      LAYER M4 ;
        RECT  81.996 4.656 82.08 4.68 ;
    END
  END unavailable_fault[4]
  PIN unavailable_fault[5]
    DIRECTION INPUT ;
    USE SIGNAL ;
    PORT
      LAYER M4 ;
        RECT  81.996 4.752 82.08 4.776 ;
    END
  END unavailable_fault[5]
  PIN unavailable_fault[6]
    DIRECTION INPUT ;
    USE SIGNAL ;
    PORT
      LAYER M4 ;
        RECT  81.996 4.848 82.08 4.872 ;
    END
  END unavailable_fault[6]
  PIN unavailable_fault[7]
    DIRECTION INPUT ;
    USE SIGNAL ;
    PORT
      LAYER M4 ;
        RECT  81.996 4.944 82.08 4.968 ;
    END
  END unavailable_fault[7]
  PIN unavailable_fault[8]
    DIRECTION INPUT ;
    USE SIGNAL ;
    PORT
      LAYER M4 ;
        RECT  81.996 5.04 82.08 5.064 ;
    END
  END unavailable_fault[8]
  PIN unavailable_fault[9]
    DIRECTION INPUT ;
    USE SIGNAL ;
    PORT
      LAYER M4 ;
        RECT  81.996 5.136 82.08 5.16 ;
    END
  END unavailable_fault[9]
  PIN writer_fault
    DIRECTION INPUT ;
    USE SIGNAL ;
    PORT
      LAYER M4 ;
        RECT  0 16.944 0.084 16.968 ;
    END
  END writer_fault
  PIN VDD
    DIRECTION INOUT ;
    USE POWER ;
    PORT
      LAYER M5 ;
        RECT  78.192 2.151 78.312 54.009 ;
        RECT  72.792 2.151 72.912 54.009 ;
        RECT  67.392 2.151 67.512 54.009 ;
        RECT  61.992 2.151 62.112 54.009 ;
        RECT  56.592 2.151 56.712 54.009 ;
        RECT  51.192 2.151 51.312 54.009 ;
        RECT  45.792 2.151 45.912 54.009 ;
        RECT  40.392 2.151 40.512 54.009 ;
        RECT  34.992 2.151 35.112 54.009 ;
        RECT  29.592 2.151 29.712 54.009 ;
        RECT  24.192 2.151 24.312 54.009 ;
        RECT  18.792 2.151 18.912 54.009 ;
        RECT  13.392 2.151 13.512 54.009 ;
        RECT  7.992 2.151 8.112 54.009 ;
        RECT  2.592 2.151 2.712 54.009 ;
    END
  END VDD
  PIN VSS
    DIRECTION INOUT ;
    USE GROUND ;
    PORT
      LAYER M5 ;
        RECT  78 2.137 78.12 54.023 ;
        RECT  72.6 2.137 72.72 54.023 ;
        RECT  67.2 2.137 67.32 54.023 ;
        RECT  61.8 2.137 61.92 54.023 ;
        RECT  56.4 2.137 56.52 54.023 ;
        RECT  51 2.137 51.12 54.023 ;
        RECT  45.6 2.137 45.72 54.023 ;
        RECT  40.2 2.137 40.32 54.023 ;
        RECT  34.8 2.137 34.92 54.023 ;
        RECT  29.4 2.137 29.52 54.023 ;
        RECT  24 2.137 24.12 54.023 ;
        RECT  18.6 2.137 18.72 54.023 ;
        RECT  13.2 2.137 13.32 54.023 ;
        RECT  7.8 2.137 7.92 54.023 ;
        RECT  2.4 2.137 2.52 54.023 ;
    END
  END VSS
  OBS
    LAYER RVTN ;
     RECT  2.16 2.16 79.92 2.295 ;
     RECT  2.16 2.565 79.92 2.835 ;
     RECT  2.16 3.105 79.92 3.375 ;
     RECT  2.16 3.645 79.92 3.915 ;
     RECT  2.16 4.185 79.92 4.455 ;
     RECT  2.16 4.725 79.92 4.995 ;
     RECT  2.16 5.265 79.92 5.535 ;
     RECT  2.16 5.805 79.92 6.075 ;
     RECT  2.16 6.345 79.92 6.615 ;
     RECT  2.16 6.885 79.92 7.155 ;
     RECT  2.16 7.425 79.92 7.695 ;
     RECT  2.16 7.965 79.92 8.235 ;
     RECT  2.16 8.505 79.92 8.775 ;
     RECT  2.16 9.045 79.92 9.315 ;
     RECT  2.16 9.585 79.92 9.855 ;
     RECT  2.16 10.125 79.92 10.395 ;
     RECT  2.16 10.665 79.92 10.935 ;
     RECT  2.16 11.205 79.92 11.475 ;
     RECT  2.16 11.745 79.92 12.015 ;
     RECT  2.16 12.285 79.92 12.555 ;
     RECT  2.16 12.825 79.92 13.095 ;
     RECT  2.16 13.365 79.92 13.635 ;
     RECT  2.16 13.905 79.92 14.175 ;
     RECT  2.16 14.445 79.92 14.715 ;
     RECT  2.16 14.985 79.92 15.255 ;
     RECT  2.16 15.525 79.92 15.795 ;
     RECT  2.16 16.065 79.92 16.335 ;
     RECT  2.16 16.605 79.92 16.875 ;
     RECT  2.16 17.145 79.92 17.415 ;
     RECT  2.16 17.685 79.92 17.955 ;
     RECT  2.16 18.225 79.92 18.495 ;
     RECT  2.16 18.765 79.92 19.035 ;
     RECT  2.16 19.305 79.92 19.575 ;
     RECT  2.16 19.845 79.92 20.115 ;
     RECT  2.16 20.385 79.92 20.655 ;
     RECT  2.16 20.925 79.92 21.195 ;
     RECT  2.16 21.465 79.92 21.735 ;
     RECT  2.16 22.005 79.92 22.275 ;
     RECT  2.16 22.545 79.92 22.815 ;
     RECT  2.16 23.085 79.92 23.355 ;
     RECT  2.16 23.625 79.92 23.895 ;
     RECT  2.16 24.165 79.92 24.435 ;
     RECT  2.16 24.705 79.92 24.975 ;
     RECT  2.16 25.245 79.92 25.515 ;
     RECT  2.16 25.785 79.92 26.055 ;
     RECT  2.16 26.325 79.92 26.595 ;
     RECT  2.16 26.865 79.92 27.135 ;
     RECT  2.16 27.405 79.92 27.675 ;
     RECT  2.16 27.945 79.92 28.215 ;
     RECT  2.16 28.485 79.92 28.755 ;
     RECT  2.16 29.025 79.92 29.295 ;
     RECT  2.16 29.565 79.92 29.835 ;
     RECT  2.16 30.105 79.92 30.375 ;
     RECT  2.16 30.645 79.92 30.915 ;
     RECT  2.16 31.185 79.92 31.455 ;
     RECT  2.16 31.725 79.92 31.995 ;
     RECT  2.16 32.265 79.92 32.535 ;
     RECT  2.16 32.805 79.92 33.075 ;
     RECT  2.16 33.345 79.92 33.615 ;
     RECT  2.16 33.885 79.92 34.155 ;
     RECT  2.16 34.425 79.92 34.695 ;
     RECT  2.16 34.965 79.92 35.235 ;
     RECT  2.16 35.505 79.92 35.775 ;
     RECT  2.16 36.045 79.92 36.315 ;
     RECT  2.16 36.585 79.92 36.855 ;
     RECT  2.16 37.125 79.92 37.395 ;
     RECT  2.16 37.665 79.92 37.935 ;
     RECT  2.16 38.205 79.92 38.475 ;
     RECT  2.16 38.745 79.92 39.015 ;
     RECT  2.16 39.285 79.92 39.555 ;
     RECT  2.16 39.825 79.92 40.095 ;
     RECT  2.16 40.365 79.92 40.635 ;
     RECT  2.16 40.905 79.92 41.175 ;
     RECT  2.16 41.445 79.92 41.715 ;
     RECT  2.16 41.985 79.92 42.255 ;
     RECT  2.16 42.525 79.92 42.795 ;
     RECT  2.16 43.065 79.92 43.335 ;
     RECT  2.16 43.605 79.92 43.875 ;
     RECT  2.16 44.145 79.92 44.415 ;
     RECT  2.16 44.685 79.92 44.955 ;
     RECT  2.16 45.225 79.92 45.495 ;
     RECT  2.16 45.765 79.92 46.035 ;
     RECT  2.16 46.305 79.92 46.575 ;
     RECT  2.16 46.845 79.92 47.115 ;
     RECT  2.16 47.385 79.92 47.655 ;
     RECT  2.16 47.925 79.92 48.195 ;
     RECT  2.16 48.465 79.92 48.735 ;
     RECT  2.16 49.005 79.92 49.275 ;
     RECT  2.16 49.545 79.92 49.815 ;
     RECT  2.16 50.085 79.92 50.355 ;
     RECT  2.16 50.625 79.92 50.895 ;
     RECT  2.16 51.165 79.92 51.435 ;
     RECT  2.16 51.705 79.92 51.975 ;
     RECT  2.16 52.245 79.92 52.515 ;
     RECT  2.16 52.785 79.92 53.055 ;
     RECT  2.16 53.325 79.92 53.595 ;
     RECT  2.16 53.865 79.92 54 ;
    LAYER RVTP ;
     RECT  2.16 2.295 79.92 2.565 ;
     RECT  2.16 2.835 79.92 3.105 ;
     RECT  2.16 3.375 79.92 3.645 ;
     RECT  2.16 3.915 79.92 4.185 ;
     RECT  2.16 4.455 79.92 4.725 ;
     RECT  2.16 4.995 79.92 5.265 ;
     RECT  2.16 5.535 79.92 5.805 ;
     RECT  2.16 6.075 79.92 6.345 ;
     RECT  2.16 6.615 79.92 6.885 ;
     RECT  2.16 7.155 79.92 7.425 ;
     RECT  2.16 7.695 79.92 7.965 ;
     RECT  2.16 8.235 79.92 8.505 ;
     RECT  2.16 8.775 79.92 9.045 ;
     RECT  2.16 9.315 79.92 9.585 ;
     RECT  2.16 9.855 79.92 10.125 ;
     RECT  2.16 10.395 79.92 10.665 ;
     RECT  2.16 10.935 79.92 11.205 ;
     RECT  2.16 11.475 79.92 11.745 ;
     RECT  2.16 12.015 79.92 12.285 ;
     RECT  2.16 12.555 79.92 12.825 ;
     RECT  2.16 13.095 79.92 13.365 ;
     RECT  2.16 13.635 79.92 13.905 ;
     RECT  2.16 14.175 79.92 14.445 ;
     RECT  2.16 14.715 79.92 14.985 ;
     RECT  2.16 15.255 79.92 15.525 ;
     RECT  2.16 15.795 79.92 16.065 ;
     RECT  2.16 16.335 79.92 16.605 ;
     RECT  2.16 16.875 79.92 17.145 ;
     RECT  2.16 17.415 79.92 17.685 ;
     RECT  2.16 17.955 79.92 18.225 ;
     RECT  2.16 18.495 79.92 18.765 ;
     RECT  2.16 19.035 79.92 19.305 ;
     RECT  2.16 19.575 79.92 19.845 ;
     RECT  2.16 20.115 79.92 20.385 ;
     RECT  2.16 20.655 79.92 20.925 ;
     RECT  2.16 21.195 79.92 21.465 ;
     RECT  2.16 21.735 79.92 22.005 ;
     RECT  2.16 22.275 79.92 22.545 ;
     RECT  2.16 22.815 79.92 23.085 ;
     RECT  2.16 23.355 79.92 23.625 ;
     RECT  2.16 23.895 79.92 24.165 ;
     RECT  2.16 24.435 79.92 24.705 ;
     RECT  2.16 24.975 79.92 25.245 ;
     RECT  2.16 25.515 79.92 25.785 ;
     RECT  2.16 26.055 79.92 26.325 ;
     RECT  2.16 26.595 79.92 26.865 ;
     RECT  2.16 27.135 79.92 27.405 ;
     RECT  2.16 27.675 79.92 27.945 ;
     RECT  2.16 28.215 79.92 28.485 ;
     RECT  2.16 28.755 79.92 29.025 ;
     RECT  2.16 29.295 79.92 29.565 ;
     RECT  2.16 29.835 79.92 30.105 ;
     RECT  2.16 30.375 79.92 30.645 ;
     RECT  2.16 30.915 79.92 31.185 ;
     RECT  2.16 31.455 79.92 31.725 ;
     RECT  2.16 31.995 79.92 32.265 ;
     RECT  2.16 32.535 79.92 32.805 ;
     RECT  2.16 33.075 79.92 33.345 ;
     RECT  2.16 33.615 79.92 33.885 ;
     RECT  2.16 34.155 79.92 34.425 ;
     RECT  2.16 34.695 79.92 34.965 ;
     RECT  2.16 35.235 79.92 35.505 ;
     RECT  2.16 35.775 79.92 36.045 ;
     RECT  2.16 36.315 79.92 36.585 ;
     RECT  2.16 36.855 79.92 37.125 ;
     RECT  2.16 37.395 79.92 37.665 ;
     RECT  2.16 37.935 79.92 38.205 ;
     RECT  2.16 38.475 79.92 38.745 ;
     RECT  2.16 39.015 79.92 39.285 ;
     RECT  2.16 39.555 79.92 39.825 ;
     RECT  2.16 40.095 79.92 40.365 ;
     RECT  2.16 40.635 79.92 40.905 ;
     RECT  2.16 41.175 79.92 41.445 ;
     RECT  2.16 41.715 79.92 41.985 ;
     RECT  2.16 42.255 79.92 42.525 ;
     RECT  2.16 42.795 79.92 43.065 ;
     RECT  2.16 43.335 79.92 43.605 ;
     RECT  2.16 43.875 79.92 44.145 ;
     RECT  2.16 44.415 79.92 44.685 ;
     RECT  2.16 44.955 79.92 45.225 ;
     RECT  2.16 45.495 79.92 45.765 ;
     RECT  2.16 46.035 79.92 46.305 ;
     RECT  2.16 46.575 79.92 46.845 ;
     RECT  2.16 47.115 79.92 47.385 ;
     RECT  2.16 47.655 79.92 47.925 ;
     RECT  2.16 48.195 79.92 48.465 ;
     RECT  2.16 48.735 79.92 49.005 ;
     RECT  2.16 49.275 79.92 49.545 ;
     RECT  2.16 49.815 79.92 50.085 ;
     RECT  2.16 50.355 79.92 50.625 ;
     RECT  2.16 50.895 79.92 51.165 ;
     RECT  2.16 51.435 79.92 51.705 ;
     RECT  2.16 51.975 79.92 52.245 ;
     RECT  2.16 52.515 79.92 52.785 ;
     RECT  2.16 53.055 79.92 53.325 ;
     RECT  2.16 53.595 79.92 53.865 ;
    LAYER M1 ;
     RECT  2.16 2.151 79.92 54.009 ;
    LAYER M2 ;
     RECT  2.16 2.151 12.451 54.009 ;
     RECT  12.451 2.106 13.351 54.009 ;
     RECT  13.351 2.106 14.359 54.054 ;
     RECT  14.359 2.106 14.459 54.702 ;
     RECT  14.459 2.106 14.783 54.054 ;
     RECT  14.783 2.151 18.211 54.054 ;
     RECT  18.211 2.106 18.563 54.054 ;
     RECT  18.563 2.106 18.779 54.009 ;
     RECT  18.779 2.151 21.595 54.009 ;
     RECT  21.595 2.106 22.819 54.009 ;
     RECT  22.819 2.106 27.023 54.126 ;
     RECT  27.023 2.151 30.451 54.126 ;
     RECT  30.451 2.106 30.803 54.126 ;
     RECT  30.803 2.106 31.163 54.054 ;
     RECT  31.163 2.151 31.963 54.054 ;
     RECT  31.963 2.106 33.043 54.054 ;
     RECT  33.043 2.034 33.079 54.054 ;
     RECT  33.079 1.962 36.131 54.054 ;
     RECT  36.131 1.962 37.111 54.009 ;
     RECT  37.111 1.962 38.291 54.054 ;
     RECT  38.291 2.034 40.091 54.054 ;
     RECT  40.091 2.034 42.719 54.009 ;
     RECT  42.719 2.07 42.763 54.009 ;
     RECT  42.763 2.07 44.347 54.126 ;
     RECT  44.347 2.034 49.847 54.126 ;
     RECT  49.847 2.034 52.187 54.054 ;
     RECT  53.635 0.036 53.743 0.054 ;
     RECT  52.187 2.034 53.843 54.009 ;
     RECT  53.843 2.07 54.715 54.009 ;
     RECT  54.715 2.07 55.247 54.054 ;
     RECT  53.743 0.036 55.715 0.549 ;
     RECT  55.247 2.106 56.615 54.054 ;
     RECT  55.715 0.036 56.759 0.054 ;
     RECT  56.551 1.152 56.759 1.17 ;
     RECT  56.615 2.151 58.711 54.054 ;
     RECT  58.711 2.151 60.179 54.126 ;
     RECT  60.179 2.151 60.539 54.054 ;
     RECT  60.539 2.151 61.735 54.009 ;
     RECT  61.735 2.106 64.139 54.009 ;
     RECT  64.139 2.151 68.575 54.009 ;
     RECT  68.575 2.151 69.683 54.054 ;
     RECT  69.683 2.151 75.703 54.009 ;
     RECT  75.703 2.151 78.179 54.054 ;
     RECT  78.179 2.151 79.92 54.009 ;
     RECT  79.92 3.384 80.915 10.35 ;
     RECT  80.915 7.902 80.951 10.35 ;
     RECT  80.915 3.384 80.987 7.146 ;
     RECT  80.987 3.384 81.491 6.102 ;
     RECT  80.987 7.128 81.491 7.146 ;
     RECT  80.951 8.046 81.491 10.35 ;
     RECT  81.491 3.96 81.527 6.102 ;
     RECT  81.491 8.046 81.527 8.298 ;
     RECT  81.491 9.09 81.527 10.35 ;
     RECT  81.527 4.122 81.563 5.562 ;
     RECT  81.527 8.046 81.563 8.064 ;
     RECT  81.563 4.122 81.599 4.14 ;
     RECT  81.563 5.004 81.995 5.562 ;
     RECT  81.527 10.332 81.995 10.35 ;
    LAYER M3 ;
     RECT  56.736 0.031 56.754 0.043 ;
     RECT  53.64 0.031 53.658 0.091 ;
     RECT  53.316 0.091 53.73 0.139 ;
     RECT  69.012 0.091 69.858 0.139 ;
     RECT  70.776 0.091 70.794 0.139 ;
     RECT  53.316 0.139 54.054 0.203 ;
     RECT  52.02 0.091 52.506 0.523 ;
     RECT  55.296 0.175 55.314 0.526 ;
     RECT  68.796 0.139 69.966 1.099 ;
     RECT  51.588 0.523 52.506 1.147 ;
     RECT  56.736 0.043 57.402 1.147 ;
     RECT  51.408 1.147 52.506 1.723 ;
     RECT  53.316 0.203 53.802 1.723 ;
     RECT  55.296 0.526 55.71 1.723 ;
     RECT  70.776 0.139 70.938 1.723 ;
     RECT  51.408 1.723 53.802 1.771 ;
     RECT  68.688 1.099 69.966 1.771 ;
     RECT  70.776 1.723 71.622 1.771 ;
     RECT  55.26 1.723 55.71 1.819 ;
     RECT  55.152 1.819 55.71 1.867 ;
     RECT  56.556 1.147 57.402 1.867 ;
     RECT  33.084 1.957 33.102 2.029 ;
     RECT  36.828 2.029 37.314 2.065 ;
     RECT  38.268 1.957 38.286 2.065 ;
     RECT  42.696 2.029 42.714 2.065 ;
     RECT  51.408 1.771 54.126 2.143 ;
     RECT  61.74 2.101 61.758 2.143 ;
     RECT  12.456 2.101 12.474 2.191 ;
     RECT  13.215 2.143 13.305 2.191 ;
     RECT  24.015 2.143 24.105 2.191 ;
     RECT  34.815 2.143 34.905 2.191 ;
     RECT  38.196 2.065 38.286 2.191 ;
     RECT  44.352 2.029 44.37 2.191 ;
     RECT  45.615 2.143 45.705 2.191 ;
     RECT  51.015 2.143 54.126 2.191 ;
     RECT  55.152 1.867 57.402 2.191 ;
     RECT  64.116 2.101 64.134 2.191 ;
     RECT  67.215 2.143 67.305 2.191 ;
     RECT  12.456 2.191 13.305 2.227 ;
     RECT  14.76 2.101 14.778 2.227 ;
     RECT  15.948 2.191 15.966 2.227 ;
     RECT  29.415 2.143 29.505 2.227 ;
     RECT  30.456 2.101 31.158 2.227 ;
     RECT  34.488 2.191 34.905 2.227 ;
     RECT  36.684 2.065 37.314 2.227 ;
     RECT  40.215 2.143 40.305 2.227 ;
     RECT  42.336 2.065 42.714 2.227 ;
     RECT  44.352 2.191 45.705 2.227 ;
     RECT  49.032 2.191 49.05 2.227 ;
     RECT  63.936 2.191 64.134 2.227 ;
     RECT  66.24 2.191 66.258 2.227 ;
     RECT  67.215 2.191 67.95 2.227 ;
     RECT  34.488 2.227 34.974 2.251 ;
     RECT  38.196 2.191 38.79 2.251 ;
     RECT  39.996 2.227 40.305 2.251 ;
     RECT  49.032 2.227 49.302 2.251 ;
     RECT  66.24 2.227 67.95 2.251 ;
     RECT  68.688 1.771 71.622 2.251 ;
     RECT  17.244 2.227 17.262 2.263 ;
     RECT  18.216 2.101 18.774 2.263 ;
     RECT  21.6 2.101 21.618 2.263 ;
     RECT  26.784 2.101 27.018 2.263 ;
     RECT  36.324 2.227 37.314 2.263 ;
     RECT  42.336 2.227 43.074 2.263 ;
     RECT  61.74 2.143 61.905 2.263 ;
     RECT  12.06 2.227 13.554 2.299 ;
     RECT  14.76 2.227 15.966 2.299 ;
     RECT  17.244 2.263 18.774 2.299 ;
     RECT  21.6 2.263 21.834 2.299 ;
     RECT  22.824 2.251 22.842 2.299 ;
     RECT  26.712 2.263 27.018 2.299 ;
     RECT  29.415 2.227 31.23 2.299 ;
     RECT  33.048 2.029 33.102 2.299 ;
     RECT  33.984 2.251 34.974 2.299 ;
     RECT  42.336 2.263 43.29 2.299 ;
     RECT  19.764 2.191 19.782 2.335 ;
     RECT  24.015 2.191 25.65 2.335 ;
     RECT  26.712 2.299 27.27 2.335 ;
     RECT  33.048 2.299 35.118 2.335 ;
     RECT  46.836 2.263 46.854 2.335 ;
     RECT  61.74 2.263 61.974 2.335 ;
     RECT  20.916 2.299 23.094 2.347 ;
     RECT  24.015 2.335 27.27 2.347 ;
     RECT  44.352 2.227 45.774 2.347 ;
     RECT  46.692 2.335 46.854 2.347 ;
     RECT  12.06 2.299 13.626 2.371 ;
     RECT  17.136 2.299 18.774 2.371 ;
     RECT  28.728 2.299 31.23 2.371 ;
     RECT  31.968 2.101 31.986 2.371 ;
     RECT  36.324 2.263 37.458 2.371 ;
     RECT  38.196 2.251 40.305 2.371 ;
     RECT  41.292 2.299 43.29 2.371 ;
     RECT  44.352 2.347 46.854 2.371 ;
     RECT  47.736 2.251 47.754 2.371 ;
     RECT  59.328 2.335 59.346 2.371 ;
     RECT  61.74 2.335 62.442 2.371 ;
     RECT  2.415 2.143 2.505 2.413 ;
     RECT  7.815 2.143 7.905 2.413 ;
     RECT  17.064 2.371 18.774 2.413 ;
     RECT  19.512 2.335 19.782 2.413 ;
     RECT  72.615 2.143 72.705 2.413 ;
     RECT  78.015 2.143 78.105 2.413 ;
     RECT  14.616 2.299 16.002 2.461 ;
     RECT  17.064 2.413 19.782 2.461 ;
     RECT  33.048 2.335 35.19 2.461 ;
     RECT  36.324 2.371 47.754 2.461 ;
     RECT  48.672 2.251 49.302 2.461 ;
     RECT  61.704 2.371 63.09 2.461 ;
     RECT  63.936 2.227 64.206 2.461 ;
     RECT  28.728 2.371 31.986 2.497 ;
     RECT  61.704 2.461 64.206 2.533 ;
     RECT  14.616 2.461 19.782 2.569 ;
     RECT  28.476 2.497 31.986 2.569 ;
     RECT  33.048 2.461 35.262 2.569 ;
     RECT  36.216 2.461 49.302 2.569 ;
     RECT  61.704 2.533 65.07 2.569 ;
     RECT  65.952 2.251 71.622 2.569 ;
     RECT  72.615 2.413 72.897 2.569 ;
     RECT  20.916 2.347 27.738 2.587 ;
     RECT  11.988 2.371 13.626 2.605 ;
     RECT  61.56 2.569 65.07 2.605 ;
     RECT  14.616 2.569 19.962 2.641 ;
     RECT  20.772 2.587 27.738 2.641 ;
     RECT  28.476 2.569 32.202 2.641 ;
     RECT  33.048 2.569 49.302 2.641 ;
     RECT  59.328 2.371 60.354 2.641 ;
     RECT  61.236 2.605 65.07 2.641 ;
     RECT  65.88 2.569 71.622 2.641 ;
     RECT  72.36 2.569 73.062 2.641 ;
     RECT  14.616 2.641 20.034 2.683 ;
     RECT  20.772 2.641 49.302 2.683 ;
     RECT  59.328 2.641 73.062 2.731 ;
     RECT  11.592 2.605 13.626 2.803 ;
     RECT  14.616 2.683 49.302 2.803 ;
     RECT  58.464 2.731 58.482 2.803 ;
     RECT  59.22 2.731 73.062 2.803 ;
     RECT  11.592 2.803 49.302 2.839 ;
     RECT  58.464 2.803 73.062 2.839 ;
     RECT  51.015 2.191 57.402 2.875 ;
     RECT  58.32 2.839 73.062 2.875 ;
     RECT  78.015 2.413 78.297 2.875 ;
     RECT  77.04 2.875 77.058 2.911 ;
     RECT  51.015 2.875 73.062 3.001 ;
     RECT  50.976 3.001 73.062 3.073 ;
     RECT  11.592 2.839 49.41 3.109 ;
     RECT  74.916 2.839 74.934 3.109 ;
     RECT  76.572 2.911 77.058 3.109 ;
     RECT  78.015 2.875 78.498 3.109 ;
     RECT  50.976 3.073 73.566 3.145 ;
     RECT  10.512 2.827 10.53 3.181 ;
     RECT  11.304 3.109 49.41 3.181 ;
     RECT  50.976 3.145 73.746 3.181 ;
     RECT  74.916 3.109 75.726 3.181 ;
     RECT  76.572 3.109 78.498 3.181 ;
     RECT  50.256 3.181 75.726 3.271 ;
     RECT  76.536 3.181 78.498 3.271 ;
     RECT  50.256 3.271 78.498 3.299 ;
     RECT  10.512 3.181 49.482 3.307 ;
     RECT  50.256 3.299 74.358 3.307 ;
     RECT  75.132 3.299 78.498 3.307 ;
     RECT  79.416 2.839 79.434 3.307 ;
     RECT  7.815 2.413 8.097 3.403 ;
     RECT  7.815 3.403 8.766 3.415 ;
     RECT  10.512 3.307 74.358 3.436 ;
     RECT  81.468 3.379 81.486 3.577 ;
     RECT  80.964 3.577 81.486 3.649 ;
     RECT  75.132 3.307 79.434 3.713 ;
     RECT  10.476 3.436 74.358 3.721 ;
     RECT  75.276 3.713 79.434 3.721 ;
     RECT  80.352 3.649 81.486 3.721 ;
     RECT  7.815 3.415 8.91 3.811 ;
     RECT  7.815 3.811 8.946 3.883 ;
     RECT  9.684 3.721 74.358 3.883 ;
     RECT  75.276 3.721 81.486 3.883 ;
     RECT  75.276 3.883 81.522 4.075 ;
     RECT  7.815 3.883 74.358 4.117 ;
     RECT  7.815 4.117 74.466 4.225 ;
     RECT  75.276 4.075 81.918 4.379 ;
     RECT  79.704 4.379 81.918 4.397 ;
     RECT  7.74 4.225 74.466 4.507 ;
     RECT  7.74 4.507 74.538 4.531 ;
     RECT  75.276 4.379 78.75 4.531 ;
     RECT  7.74 4.531 78.75 4.657 ;
     RECT  7.416 4.657 78.75 4.721 ;
     RECT  79.704 4.397 80.37 4.757 ;
     RECT  81.432 4.397 81.918 4.843 ;
     RECT  80.352 4.757 80.37 5.131 ;
     RECT  81.432 4.843 81.99 5.131 ;
     RECT  6.588 5.131 6.606 5.161 ;
     RECT  7.416 4.721 9.162 5.161 ;
     RECT  9.972 4.721 78.75 5.161 ;
     RECT  6.588 5.161 9.162 5.341 ;
     RECT  9.972 5.161 78.894 5.431 ;
     RECT  6.444 5.341 9.162 5.495 ;
     RECT  80.352 5.131 81.99 5.503 ;
     RECT  80.316 5.503 81.99 5.549 ;
     RECT  80.352 5.549 81.99 5.567 ;
     RECT  80.352 5.567 81.918 5.603 ;
     RECT  80.892 5.603 81.918 5.645 ;
     RECT  6.48 5.495 9.162 5.845 ;
     RECT  6.48 5.845 9.198 6.043 ;
     RECT  9.972 5.431 78.966 6.043 ;
     RECT  80.892 5.645 81.522 6.107 ;
     RECT  6.48 6.043 79.326 6.269 ;
     RECT  6.48 6.269 78.75 6.421 ;
     RECT  6.408 6.421 78.75 6.511 ;
     RECT  6.228 6.511 78.75 6.583 ;
     RECT  79.704 6.583 79.866 6.691 ;
     RECT  80.892 6.107 80.982 6.691 ;
     RECT  6.192 6.583 78.75 6.781 ;
     RECT  5.508 6.781 78.75 7.051 ;
     RECT  79.704 6.691 80.982 7.051 ;
     RECT  4.356 7.003 4.374 7.087 ;
     RECT  5.508 7.051 80.982 7.087 ;
     RECT  4.356 7.087 80.982 7.123 ;
     RECT  3.6 7.087 3.618 7.195 ;
     RECT  4.356 7.123 81.486 7.195 ;
     RECT  3.6 7.195 81.486 7.421 ;
     RECT  3.78 7.421 81.486 7.949 ;
     RECT  80.892 7.949 81.486 8.041 ;
     RECT  2.415 2.413 2.697 8.155 ;
     RECT  2.415 8.155 2.862 8.311 ;
     RECT  80.892 8.041 81.558 8.429 ;
     RECT  2.415 8.311 3.006 8.581 ;
     RECT  3.78 7.949 79.866 8.581 ;
     RECT  80.892 8.429 81.522 8.683 ;
     RECT  2.415 8.581 79.866 8.971 ;
     RECT  80.676 8.683 81.522 8.971 ;
     RECT  2.415 8.971 81.522 9.509 ;
     RECT  79.848 9.509 81.522 9.547 ;
     RECT  79.848 9.547 81.99 9.815 ;
     RECT  79.848 9.815 80.37 9.869 ;
     RECT  2.415 9.509 78.966 9.959 ;
     RECT  2.415 9.959 78.786 10.049 ;
     RECT  79.848 9.869 79.866 10.049 ;
     RECT  2.415 10.049 78.75 10.157 ;
     RECT  2.415 10.157 78.714 10.193 ;
     RECT  81.504 9.815 81.99 10.193 ;
     RECT  2.415 10.193 78.606 10.201 ;
     RECT  2.376 10.201 78.606 10.319 ;
     RECT  81.972 10.193 81.99 10.355 ;
     RECT  2.376 10.319 78.57 10.589 ;
     RECT  2.415 10.589 78.57 11.785 ;
     RECT  2.415 11.785 78.678 11.821 ;
     RECT  2.415 11.821 78.75 12.631 ;
     RECT  2.415 12.631 78.858 12.821 ;
     RECT  2.415 12.821 78.606 13.559 ;
     RECT  2.415 13.559 73.206 13.661 ;
     RECT  74.268 13.559 78.606 13.675 ;
     RECT  2.415 13.661 73.062 14.413 ;
     RECT  2.415 14.413 73.494 14.485 ;
     RECT  74.268 13.675 79.254 14.485 ;
     RECT  2.415 14.485 79.254 14.717 ;
     RECT  72.18 14.717 79.254 15.259 ;
     RECT  2.415 14.717 71.442 15.493 ;
     RECT  72.18 15.259 79.47 15.493 ;
     RECT  2.415 15.493 79.47 16.141 ;
     RECT  0.324 16.747 0.342 16.843 ;
     RECT  0.108 16.843 0.342 16.877 ;
     RECT  2.415 16.141 79.578 17.035 ;
     RECT  0.108 16.877 0.126 17.069 ;
     RECT  2.304 17.035 79.578 17.069 ;
     RECT  2.304 17.069 79.254 17.105 ;
     RECT  2.415 17.105 79.254 17.375 ;
     RECT  3.528 17.375 79.254 17.447 ;
     RECT  3.528 17.447 79.182 18.149 ;
     RECT  3.708 18.149 79.182 18.301 ;
     RECT  3.708 18.301 79.722 18.419 ;
     RECT  3.708 18.419 79.686 18.455 ;
     RECT  3.816 18.455 79.686 18.725 ;
     RECT  3.816 18.725 15.246 18.959 ;
     RECT  4.284 18.959 15.246 19.103 ;
     RECT  16.056 18.725 79.686 19.103 ;
     RECT  16.056 19.103 79.326 19.337 ;
     RECT  5.076 19.103 15.246 19.471 ;
     RECT  16.056 19.337 16.146 19.471 ;
     RECT  5.076 19.471 16.146 19.499 ;
     RECT  17.1 19.337 79.326 19.769 ;
     RECT  10.188 19.499 16.146 19.841 ;
     RECT  17.1 19.769 79.218 19.913 ;
     RECT  4.284 19.103 4.302 19.915 ;
     RECT  5.076 19.499 9.378 19.915 ;
     RECT  17.1 19.913 79.074 19.949 ;
     RECT  17.1 19.949 37.278 20.155 ;
     RECT  2.415 17.375 2.697 20.191 ;
     RECT  2.415 20.191 3.51 20.237 ;
     RECT  10.476 19.841 16.146 20.251 ;
     RECT  4.284 19.915 9.378 20.281 ;
     RECT  3.492 20.237 3.51 20.309 ;
     RECT  17.064 20.155 37.278 20.381 ;
     RECT  10.476 20.251 16.29 20.395 ;
     RECT  17.064 20.381 19.098 20.395 ;
     RECT  10.476 20.395 19.098 20.453 ;
     RECT  19.836 20.381 37.278 20.489 ;
     RECT  10.476 20.453 13.914 20.731 ;
     RECT  29.232 20.489 37.278 20.731 ;
     RECT  38.16 19.949 79.074 20.731 ;
     RECT  29.232 20.731 79.47 20.921 ;
     RECT  4.284 20.281 9.45 20.971 ;
     RECT  10.404 20.731 13.914 21.001 ;
     RECT  2.415 20.237 2.697 21.115 ;
     RECT  2.415 21.115 2.826 21.127 ;
     RECT  4.284 20.971 9.558 21.127 ;
     RECT  29.232 20.921 78.822 21.211 ;
     RECT  2.415 21.127 9.558 21.235 ;
     RECT  10.368 21.001 13.914 21.235 ;
     RECT  19.836 20.489 28.278 21.235 ;
     RECT  29.088 21.211 78.822 21.235 ;
     RECT  14.652 20.453 19.098 21.271 ;
     RECT  19.836 21.235 78.822 21.271 ;
     RECT  2.415 21.235 13.914 21.505 ;
     RECT  14.652 21.271 78.822 21.505 ;
     RECT  2.415 21.505 78.822 21.569 ;
     RECT  2.415 21.569 78.57 21.695 ;
     RECT  2.415 21.695 78.534 22.001 ;
     RECT  61.668 22.001 78.534 22.621 ;
     RECT  61.668 22.621 78.642 22.739 ;
     RECT  61.668 22.739 78.534 22.883 ;
     RECT  2.415 22.001 60.822 22.891 ;
     RECT  61.668 22.883 78.498 22.891 ;
     RECT  2.415 22.891 78.498 23.665 ;
     RECT  2.415 23.665 78.786 24.511 ;
     RECT  79.524 24.205 79.542 24.511 ;
     RECT  2.415 24.511 79.542 25.979 ;
     RECT  2.415 25.979 69.93 26.779 ;
     RECT  70.668 25.979 79.542 26.779 ;
     RECT  2.415 26.779 79.542 32.027 ;
     RECT  2.415 32.027 78.678 32.099 ;
     RECT  2.415 32.099 78.642 33.043 ;
     RECT  79.524 32.027 79.542 33.043 ;
     RECT  2.415 33.043 79.542 35.303 ;
     RECT  2.415 35.303 51.297 36.391 ;
     RECT  2.376 36.391 51.297 36.553 ;
     RECT  52.164 35.303 79.542 36.553 ;
     RECT  2.376 36.553 79.542 37.625 ;
     RECT  2.415 37.625 79.542 43.303 ;
     RECT  2.376 43.303 79.542 43.799 ;
     RECT  2.415 43.799 79.542 47.417 ;
     RECT  2.415 47.417 78.75 48.271 ;
     RECT  79.524 47.417 79.542 48.271 ;
     RECT  2.415 48.271 79.794 48.389 ;
     RECT  2.415 48.389 79.614 48.929 ;
     RECT  2.415 48.929 79.542 49.315 ;
     RECT  2.34 49.315 79.542 50.251 ;
     RECT  2.304 50.251 79.542 50.431 ;
     RECT  2.304 50.431 79.578 50.657 ;
     RECT  21.06 50.657 79.578 50.693 ;
     RECT  2.304 50.657 20.07 50.935 ;
     RECT  21.06 50.693 79.542 51.359 ;
     RECT  21.06 51.359 79.506 51.403 ;
     RECT  2.268 50.935 20.07 51.475 ;
     RECT  20.808 51.403 79.506 51.475 ;
     RECT  2.268 51.475 79.506 51.739 ;
     RECT  2.232 51.739 79.506 51.899 ;
     RECT  2.304 51.899 79.506 52.321 ;
     RECT  2.304 52.321 79.578 52.439 ;
     RECT  2.34 52.439 79.578 52.979 ;
     RECT  31.896 52.979 79.578 53.131 ;
     RECT  31.896 53.131 79.614 53.159 ;
     RECT  2.34 52.979 31.014 53.249 ;
     RECT  31.896 53.159 74.538 53.249 ;
     RECT  75.312 53.159 79.614 53.249 ;
     RECT  31.896 53.249 37.134 53.285 ;
     RECT  42.048 53.249 74.538 53.285 ;
     RECT  75.312 53.249 79.398 53.285 ;
     RECT  2.34 53.249 21.15 53.293 ;
     RECT  73.656 53.285 74.538 53.429 ;
     RECT  2.268 53.293 21.15 53.519 ;
     RECT  22.212 53.249 31.014 53.519 ;
     RECT  37.872 53.249 38.07 53.519 ;
     RECT  42.048 53.285 72.897 53.519 ;
     RECT  73.836 53.429 74.538 53.519 ;
     RECT  75.456 53.285 79.398 53.519 ;
     RECT  2.268 53.519 19.422 53.527 ;
     RECT  32.4 53.285 37.134 53.549 ;
     RECT  20.268 53.519 21.15 53.555 ;
     RECT  37.944 53.519 37.962 53.555 ;
     RECT  42.3 53.519 70.83 53.555 ;
     RECT  73.836 53.519 73.854 53.555 ;
     RECT  56.415 53.555 70.83 53.597 ;
     RECT  42.3 53.555 55.278 53.627 ;
     RECT  42.3 53.627 55.242 53.663 ;
     RECT  2.232 53.527 19.422 53.693 ;
     RECT  32.4 53.549 33.462 53.699 ;
     RECT  75.492 53.519 79.254 53.699 ;
     RECT  75.492 53.699 78.858 53.741 ;
     RECT  56.415 53.597 56.697 53.747 ;
     RECT  71.64 53.519 72.897 53.747 ;
     RECT  2.304 53.693 19.422 53.789 ;
     RECT  20.52 53.555 21.15 53.789 ;
     RECT  22.392 53.519 30.978 53.789 ;
     RECT  32.4 53.699 32.562 53.789 ;
     RECT  33.3 53.699 33.462 53.789 ;
     RECT  34.488 53.549 37.134 53.789 ;
     RECT  38.88 53.249 41.058 53.789 ;
     RECT  42.3 53.663 54.738 53.789 ;
     RECT  75.528 53.741 78.858 53.789 ;
     RECT  11.34 53.789 15.822 53.795 ;
     RECT  32.4 53.789 32.418 53.795 ;
     RECT  38.88 53.789 38.898 53.795 ;
     RECT  17.352 53.789 19.062 53.825 ;
     RECT  20.52 53.789 20.646 53.825 ;
     RECT  29.415 53.789 30.798 53.825 ;
     RECT  34.488 53.789 36.126 53.825 ;
     RECT  39.924 53.789 40.305 53.825 ;
     RECT  42.3 53.789 53.658 53.825 ;
     RECT  57.564 53.597 70.83 53.825 ;
     RECT  71.64 53.747 72.705 53.825 ;
     RECT  75.528 53.789 78.642 53.825 ;
     RECT  42.3 53.825 52.182 53.861 ;
     RECT  56.415 53.747 56.574 53.861 ;
     RECT  2.304 53.789 3.438 53.897 ;
     RECT  11.592 53.795 15.822 53.897 ;
     RECT  42.768 53.861 52.182 53.897 ;
     RECT  52.992 53.825 53.658 53.897 ;
     RECT  57.564 53.825 57.582 53.897 ;
     RECT  70.452 53.825 70.83 53.897 ;
     RECT  71.64 53.825 71.658 53.897 ;
     RECT  72.396 53.825 72.705 53.897 ;
     RECT  12.708 53.897 15.822 53.933 ;
     RECT  16.56 53.789 16.578 53.933 ;
     RECT  17.352 53.825 17.622 53.933 ;
     RECT  24.015 53.789 28.566 53.933 ;
     RECT  29.415 53.825 29.79 53.933 ;
     RECT  33.3 53.789 33.318 53.933 ;
     RECT  34.815 53.825 36.126 53.933 ;
     RECT  39.996 53.825 40.305 53.933 ;
     RECT  48.924 53.897 52.182 53.933 ;
     RECT  52.992 53.897 53.01 53.933 ;
     RECT  15.48 53.933 15.822 53.939 ;
     RECT  17.604 53.933 17.622 53.969 ;
     RECT  29.415 53.933 29.574 53.969 ;
     RECT  42.768 53.897 48.006 53.969 ;
     RECT  48.924 53.933 51.105 53.969 ;
     RECT  70.632 53.897 70.65 53.969 ;
     RECT  4.212 53.789 10.386 53.981 ;
     RECT  12.708 53.933 14.706 53.981 ;
     RECT  18.54 53.825 18.705 54.017 ;
     RECT  24.015 53.933 28.422 54.017 ;
     RECT  29.415 53.969 29.505 54.017 ;
     RECT  34.815 53.933 34.905 54.017 ;
     RECT  40.068 53.933 40.305 54.017 ;
     RECT  51.015 53.969 51.105 54.017 ;
     RECT  56.415 53.861 56.505 54.017 ;
     RECT  72.615 53.897 72.705 54.017 ;
     RECT  15.48 53.939 15.498 54.029 ;
     RECT  12.708 53.981 13.374 54.059 ;
     RECT  18.54 54.017 18.558 54.059 ;
     RECT  22.824 53.789 23.094 54.059 ;
     RECT  24.444 54.017 28.422 54.059 ;
     RECT  36.108 53.933 36.126 54.059 ;
     RECT  37.116 53.789 37.134 54.059 ;
     RECT  40.068 54.017 40.086 54.059 ;
     RECT  52.164 53.933 52.182 54.059 ;
     RECT  54.72 53.789 54.738 54.059 ;
     RECT  58.716 53.825 69.678 54.059 ;
     RECT  5.004 53.981 9.45 54.077 ;
     RECT  44.244 53.969 47.61 54.095 ;
     RECT  5.652 54.077 5.886 54.125 ;
     RECT  6.768 54.077 9.45 54.125 ;
     RECT  24.444 54.059 27.882 54.125 ;
     RECT  42.768 53.969 43.47 54.125 ;
     RECT  58.716 54.059 69.102 54.125 ;
     RECT  75.564 53.825 78.534 54.125 ;
     RECT  22.824 54.059 22.842 54.131 ;
     RECT  30.564 53.825 30.798 54.131 ;
     RECT  42.768 54.125 43.254 54.131 ;
     RECT  48.924 53.969 50.238 54.131 ;
     RECT  58.716 54.125 60.174 54.131 ;
     RECT  7.668 54.125 7.758 54.173 ;
     RECT  48.924 54.131 49.338 54.173 ;
     RECT  67.356 54.125 68.202 54.173 ;
     RECT  6.768 54.125 6.786 54.221 ;
     RECT  12.708 54.059 12.978 54.221 ;
     RECT  44.244 54.095 46.17 54.221 ;
     RECT  67.536 54.173 68.202 54.221 ;
     RECT  7.74 54.173 7.758 54.701 ;
     RECT  67.968 54.221 68.202 54.701 ;
     RECT  11.592 53.897 11.97 54.749 ;
     RECT  24.444 54.125 26.982 54.749 ;
     RECT  75.564 54.125 77.958 54.749 ;
     RECT  75.996 54.749 77.958 54.797 ;
     RECT  24.444 54.749 24.462 54.845 ;
     RECT  2.304 53.897 3.366 55.277 ;
     RECT  14.364 53.981 14.706 55.277 ;
     RECT  25.632 54.749 26.982 55.277 ;
     RECT  46.908 54.095 47.61 55.277 ;
     RECT  68.04 54.701 68.202 55.277 ;
     RECT  76.176 54.797 77.958 55.277 ;
     RECT  2.916 55.277 3.366 55.325 ;
     RECT  5.652 54.125 5.67 55.325 ;
     RECT  8.496 54.125 9.306 55.325 ;
     RECT  10.368 53.981 10.386 55.325 ;
     RECT  12.708 54.221 12.726 55.325 ;
     RECT  44.244 54.221 45.234 55.325 ;
     RECT  46.152 54.221 46.17 55.325 ;
     RECT  59.076 54.131 59.814 55.325 ;
     RECT  61.092 54.125 62.478 55.325 ;
     RECT  63.576 54.125 66.618 55.325 ;
     RECT  76.176 55.277 77.346 55.325 ;
     RECT  43.236 54.131 43.254 55.373 ;
     RECT  59.4 55.325 59.814 55.373 ;
     RECT  61.416 55.325 61.542 55.373 ;
     RECT  59.4 55.373 59.418 55.421 ;
     RECT  61.524 55.373 61.542 55.421 ;
     RECT  4.212 53.981 4.23 55.901 ;
     RECT  14.364 55.277 14.598 55.901 ;
     RECT  49.32 54.173 49.338 55.915 ;
     RECT  50.22 54.131 50.238 55.915 ;
     RECT  8.784 55.325 9.306 55.997 ;
     RECT  11.592 54.749 11.79 55.997 ;
     RECT  48.924 55.915 50.238 55.997 ;
     RECT  64.224 55.325 66.618 55.997 ;
     RECT  68.04 55.277 68.166 55.997 ;
     RECT  3.348 55.325 3.366 56.045 ;
     RECT  6.228 55.915 6.246 56.045 ;
     RECT  9.288 55.997 9.306 56.045 ;
     RECT  11.772 55.997 11.79 56.045 ;
     RECT  14.364 55.901 14.382 56.045 ;
     RECT  26.244 55.277 26.982 56.045 ;
     RECT  45.216 55.325 45.234 56.045 ;
     RECT  47.592 55.277 47.61 56.045 ;
     RECT  48.924 55.997 49.626 56.045 ;
     RECT  64.224 55.997 64.242 56.045 ;
     RECT  65.88 55.997 66.33 56.045 ;
     RECT  68.04 55.997 68.058 56.045 ;
     RECT  69.084 54.125 69.102 56.045 ;
     RECT  76.464 55.325 76.482 56.045 ;
     RECT  48.924 56.045 48.942 56.141 ;
     RECT  62.46 55.325 62.478 56.141 ;
    LAYER M4 ;
     RECT  0.06 16.656 0.097 16.968 ;
     RECT  1.573 49.344 1.765 49.368 ;
     RECT  1.861 53.568 1.957 53.592 ;
     RECT  1.765 49.344 2.053 50.136 ;
     RECT  1.669 51.12 2.053 51.144 ;
     RECT  2.053 49.344 2.149 51.144 ;
     RECT  1.957 53.568 2.204 53.64 ;
     RECT  2.149 49.344 2.221 51.336 ;
     RECT  1.477 55.248 2.293 55.272 ;
     RECT  2.204 53.568 2.341 53.688 ;
     RECT  0.097 16.656 2.408 17.064 ;
     RECT  2.221 49.344 2.408 51.768 ;
     RECT  2.341 53.568 2.408 54.168 ;
     RECT  2.408 2.148 2.512 54.168 ;
     RECT  2.512 2.418 2.704 54.168 ;
     RECT  2.704 53.568 2.725 54.168 ;
     RECT  2.293 55.248 2.725 55.992 ;
     RECT  2.704 48.24 2.837 52.296 ;
     RECT  2.704 20.208 2.867 21.144 ;
     RECT  2.704 25.056 2.867 25.464 ;
     RECT  2.704 30.816 2.915 34.776 ;
     RECT  2.704 7.392 2.917 9.048 ;
     RECT  2.704 39.312 2.945 40.488 ;
     RECT  2.945 39.312 2.953 39.768 ;
     RECT  2.704 38.064 3.011 38.328 ;
     RECT  2.725 53.568 3.013 55.992 ;
     RECT  2.704 11.952 3.059 13.944 ;
     RECT  3.059 12.48 3.1 13.944 ;
     RECT  2.704 45.6 3.169 45.624 ;
     RECT  2.915 30.816 3.203 33.288 ;
     RECT  3.203 30.816 3.244 31.56 ;
     RECT  3.013 53.568 3.251 56.04 ;
     RECT  3.251 55.872 3.377 56.04 ;
     RECT  2.915 34.272 3.449 34.776 ;
     RECT  2.837 48.24 3.593 52.2 ;
     RECT  2.917 7.392 3.629 7.416 ;
     RECT  3.251 53.568 3.635 54.696 ;
     RECT  2.704 15.216 3.695 15.24 ;
     RECT  2.704 16.368 3.695 17.112 ;
     RECT  2.867 25.392 3.697 25.464 ;
     RECT  2.704 26.688 3.697 26.856 ;
     RECT  3.685 18.384 3.733 18.408 ;
     RECT  2.704 42 3.733 44.472 ;
     RECT  3.011 38.304 3.773 38.328 ;
     RECT  2.917 9.024 3.877 9.048 ;
     RECT  2.704 10.032 3.877 10.872 ;
     RECT  3.449 34.272 3.917 34.296 ;
     RECT  2.704 28.416 3.949 29.784 ;
     RECT  3.244 30.816 3.949 30.84 ;
     RECT  3.733 18.144 3.953 18.408 ;
     RECT  3.949 28.416 4.019 30.84 ;
     RECT  3.877 9.024 4.021 10.872 ;
     RECT  3.695 15.216 4.057 17.112 ;
     RECT  3.953 18.144 4.057 18.168 ;
     RECT  2.953 39.744 4.057 39.768 ;
     RECT  3.1 12.48 4.061 12.552 ;
     RECT  4.021 8.496 4.067 10.872 ;
     RECT  4.061 12.528 4.101 12.552 ;
     RECT  3.1 13.92 4.101 13.944 ;
     RECT  3.925 47.136 4.124 47.16 ;
     RECT  3.593 48.24 4.124 51.336 ;
     RECT  4.057 15.216 4.163 18.168 ;
     RECT  3.377 55.872 4.163 55.992 ;
     RECT  3.733 41.76 4.205 44.472 ;
     RECT  4.163 55.872 4.241 55.896 ;
     RECT  4.019 30.048 4.277 30.6 ;
     RECT  4.067 8.496 4.349 9.576 ;
     RECT  4.067 10.656 4.381 10.872 ;
     RECT  2.704 22.656 4.385 23.928 ;
     RECT  3.203 33.264 4.421 33.288 ;
     RECT  3.697 25.392 4.453 26.856 ;
     RECT  4.277 30.048 4.493 30.408 ;
     RECT  2.704 36.672 4.493 36.696 ;
     RECT  4.381 52.464 4.547 52.488 ;
     RECT  2.867 20.208 4.561 20.232 ;
     RECT  4.101 12.528 4.669 13.944 ;
     RECT  4.124 47.136 4.669 51.336 ;
     RECT  4.453 25.056 4.705 26.856 ;
     RECT  4.019 28.416 4.705 28.872 ;
     RECT  4.057 39.744 4.837 40.056 ;
     RECT  4.741 31.968 4.885 31.992 ;
     RECT  4.385 22.656 4.957 22.824 ;
     RECT  4.453 45.6 4.991 45.624 ;
     RECT  3.635 53.568 4.993 54.024 ;
     RECT  4.705 25.056 5.069 28.872 ;
     RECT  4.561 34.128 5.069 34.152 ;
     RECT  4.669 12.528 5.137 14.184 ;
     RECT  4.163 15.744 5.137 18.168 ;
     RECT  4.349 8.496 5.209 9.048 ;
     RECT  4.385 23.856 5.209 23.928 ;
     RECT  5.069 25.056 5.209 28.728 ;
     RECT  4.837 38.832 5.209 40.056 ;
     RECT  4.493 30.288 5.245 30.408 ;
     RECT  4.205 41.76 5.269 42.6 ;
     RECT  4.205 44.256 5.269 44.472 ;
     RECT  4.381 10.656 5.317 11.4 ;
     RECT  5.137 12.528 5.317 18.168 ;
     RECT  5.269 43.92 5.317 44.472 ;
     RECT  4.991 45.6 5.317 45.672 ;
     RECT  4.957 22.176 5.353 22.824 ;
     RECT  5.209 23.856 5.353 28.728 ;
     RECT  4.561 19.92 5.425 20.952 ;
     RECT  4.669 46.752 5.461 51.336 ;
     RECT  5.209 38.4 5.497 40.056 ;
     RECT  5.317 43.92 5.497 45.672 ;
     RECT  5.269 41.76 5.533 42.744 ;
     RECT  5.209 8.208 5.557 9.048 ;
     RECT  5.317 10.656 5.557 18.168 ;
     RECT  5.461 46.752 5.557 51.96 ;
     RECT  4.345 7.008 5.605 7.032 ;
     RECT  5.557 8.208 5.605 18.168 ;
     RECT  4.201 35.328 5.605 35.352 ;
     RECT  5.245 30.288 5.641 30.984 ;
     RECT  5.497 38.4 5.677 40.488 ;
     RECT  5.533 41.712 5.677 42.744 ;
     RECT  5.353 22.176 5.681 28.728 ;
     RECT  5.605 34.752 5.699 35.352 ;
     RECT  5.605 7.008 5.701 18.168 ;
     RECT  5.641 55.296 5.701 55.32 ;
     RECT  5.681 22.176 5.717 26.424 ;
     RECT  4.885 31.968 5.717 32.712 ;
     RECT  5.699 35.04 5.717 35.352 ;
     RECT  5.681 27.6 5.753 28.728 ;
     RECT  5.677 38.4 5.797 42.744 ;
     RECT  5.497 43.92 5.797 45.72 ;
     RECT  5.797 38.4 5.825 45.72 ;
     RECT  4.993 53.568 5.857 54.072 ;
     RECT  5.701 55.296 5.939 55.992 ;
     RECT  4.633 36.768 5.948 37.032 ;
     RECT  5.425 19.92 5.969 21.192 ;
     RECT  5.717 32.688 5.989 32.712 ;
     RECT  5.948 36.768 6.035 37.272 ;
     RECT  5.825 38.544 6.035 45.72 ;
     RECT  5.753 28.176 6.037 28.728 ;
     RECT  5.641 30.048 6.037 30.984 ;
     RECT  5.939 55.92 6.178 55.992 ;
     RECT  6.037 28.176 6.181 30.984 ;
     RECT  5.989 32.688 6.253 33.048 ;
     RECT  5.857 53.568 6.253 54.12 ;
     RECT  5.701 7.008 6.397 18.792 ;
     RECT  5.969 19.92 6.397 20.472 ;
     RECT  6.397 7.008 6.401 20.472 ;
     RECT  6.035 36.768 6.401 37.032 ;
     RECT  6.178 55.92 6.419 56.04 ;
     RECT  6.419 55.92 6.467 55.944 ;
     RECT  6.401 10.176 6.473 20.472 ;
     RECT  5.557 46.752 6.505 52.488 ;
     RECT  6.401 36.768 6.541 36.792 ;
     RECT  5.717 22.176 6.649 25.992 ;
     RECT  6.401 7.008 6.721 9.048 ;
     RECT  6.253 32.688 6.721 33.912 ;
     RECT  5.717 35.04 6.721 35.064 ;
     RECT  6.035 38.544 6.725 39.864 ;
     RECT  6.253 53.52 6.757 54.12 ;
     RECT  6.725 38.544 6.793 39.816 ;
     RECT  6.035 41.424 6.793 45.72 ;
     RECT  6.505 46.752 6.793 52.536 ;
     RECT  6.721 32.688 6.805 35.064 ;
     RECT  6.805 32.352 6.829 35.064 ;
     RECT  6.793 41.424 6.853 52.536 ;
     RECT  6.757 53.52 6.853 54.216 ;
     RECT  6.473 20.448 6.937 20.472 ;
     RECT  6.649 21.456 6.937 25.992 ;
     RECT  6.181 28.176 6.937 31.32 ;
     RECT  6.829 32.352 7.009 35.208 ;
     RECT  6.541 36.528 7.009 36.792 ;
     RECT  6.721 6.672 7.117 9.048 ;
     RECT  6.793 38.304 7.297 39.816 ;
     RECT  6.577 5.136 7.34 5.16 ;
     RECT  7.117 6.528 7.34 9.048 ;
     RECT  7.009 32.352 7.369 36.792 ;
     RECT  7.297 37.872 7.369 39.816 ;
     RECT  6.473 10.176 7.513 19.368 ;
     RECT  6.937 20.448 7.513 26.376 ;
     RECT  7.34 5.136 7.669 9.048 ;
     RECT  6.853 41.424 7.729 54.216 ;
     RECT  7.669 3.936 7.808 9.048 ;
     RECT  7.513 10.176 7.808 26.376 ;
     RECT  6.937 28.128 7.808 31.32 ;
     RECT  7.369 32.352 7.808 39.816 ;
     RECT  7.729 41.424 7.808 54.696 ;
     RECT  7.808 2.148 7.912 54.696 ;
     RECT  7.477 55.968 8.101 55.992 ;
     RECT  7.912 2.418 8.104 54.696 ;
     RECT  8.104 3.408 8.165 5.16 ;
     RECT  8.104 41.184 8.485 54.696 ;
     RECT  8.101 55.872 8.485 55.992 ;
     RECT  8.104 6.528 8.705 23.112 ;
     RECT  8.104 24.144 8.921 27.72 ;
     RECT  8.485 41.184 9.107 56.04 ;
     RECT  8.705 6.528 9.133 9.384 ;
     RECT  8.104 29.04 9.137 39.912 ;
     RECT  9.137 30.192 9.157 39.912 ;
     RECT  9.107 41.184 9.157 54.696 ;
     RECT  8.705 10.656 9.208 23.112 ;
     RECT  9.208 10.656 9.241 23.16 ;
     RECT  8.921 24.144 9.241 26.28 ;
     RECT  9.133 6.48 9.313 9.384 ;
     RECT  9.157 30.192 9.317 54.696 ;
     RECT  9.107 56.016 9.317 56.04 ;
     RECT  8.921 27.312 9.385 27.72 ;
     RECT  9.137 29.04 9.385 29.064 ;
     RECT  9.241 10.656 9.389 26.28 ;
     RECT  9.389 20.688 9.533 26.28 ;
     RECT  9.317 30.384 9.641 54.696 ;
     RECT  8.165 4.656 9.673 5.16 ;
     RECT  9.313 6.144 9.673 9.384 ;
     RECT  9.389 10.656 9.673 19.368 ;
     RECT  9.641 30.384 9.677 36.024 ;
     RECT  9.641 37.056 9.683 54.696 ;
     RECT  9.677 33.6 9.785 36.024 ;
     RECT  9.785 33.6 9.875 35.688 ;
     RECT  9.533 22.176 9.997 26.28 ;
     RECT  9.385 27.312 9.997 29.064 ;
     RECT  9.673 4.416 10.213 5.16 ;
     RECT  9.673 6.144 10.213 19.368 ;
     RECT  9.683 37.056 10.355 54.12 ;
     RECT  8.165 3.408 10.465 3.432 ;
     RECT  10.213 4.416 10.465 19.368 ;
     RECT  10.465 3.408 10.501 19.368 ;
     RECT  9.533 20.688 10.501 21 ;
     RECT  9.677 30.384 10.505 32.088 ;
     RECT  9.997 22.176 10.609 29.064 ;
     RECT  10.357 55.296 10.643 55.32 ;
     RECT  10.501 2.832 10.681 21 ;
     RECT  10.609 22.176 10.681 29.112 ;
     RECT  10.681 2.832 10.789 29.112 ;
     RECT  9.875 33.792 10.789 35.688 ;
     RECT  10.789 33.792 10.837 35.736 ;
     RECT  10.505 31.056 11.041 32.088 ;
     RECT  10.837 33.792 11.041 35.928 ;
     RECT  10.355 37.056 11.081 53.784 ;
     RECT  11.041 31.056 11.297 35.928 ;
     RECT  11.297 35.664 11.365 35.928 ;
     RECT  11.081 37.056 11.365 43.272 ;
     RECT  11.297 31.056 11.621 34.392 ;
     RECT  11.269 55.968 11.621 56.04 ;
     RECT  11.621 56.016 11.801 56.04 ;
     RECT  11.081 44.4 11.941 53.784 ;
     RECT  10.789 2.832 11.977 29.64 ;
     RECT  11.977 2.832 12.049 29.88 ;
     RECT  12.049 2.736 12.161 29.88 ;
     RECT  11.941 44.4 12.179 54.744 ;
     RECT  11.365 35.664 12.301 43.272 ;
     RECT  12.179 44.4 12.301 54.216 ;
     RECT  12.161 24.864 12.613 29.88 ;
     RECT  11.621 31.104 12.625 34.392 ;
     RECT  12.301 35.664 12.625 54.216 ;
     RECT  12.613 24.864 13.093 30.072 ;
     RECT  12.625 31.104 13.093 54.216 ;
     RECT  12.161 2.88 13.208 23.688 ;
     RECT  13.093 24.864 13.208 54.216 ;
     RECT  13.208 2.148 13.235 54.216 ;
     RECT  12.697 55.296 13.285 55.32 ;
     RECT  13.235 2.148 13.312 54.024 ;
     RECT  13.285 55.296 13.381 55.992 ;
     RECT  13.312 2.418 13.504 54.024 ;
     RECT  13.504 25.008 13.645 54.024 ;
     RECT  13.645 25.008 13.673 34.92 ;
     RECT  13.381 55.248 14.053 55.992 ;
     RECT  13.504 2.88 14.105 23.88 ;
     RECT  14.053 55.248 14.393 56.04 ;
     RECT  14.105 22.992 14.429 23.88 ;
     RECT  13.673 25.008 14.501 34.824 ;
     RECT  14.105 2.88 14.605 21.72 ;
     RECT  14.393 55.248 14.609 55.896 ;
     RECT  14.501 25.008 14.641 34.488 ;
     RECT  14.609 55.248 14.717 55.272 ;
     RECT  13.645 36.48 14.785 54.024 ;
     RECT  14.429 23.04 15.001 23.88 ;
     RECT  14.641 24.96 15.001 34.488 ;
     RECT  14.605 2.304 15.397 21.72 ;
     RECT  15.001 23.04 15.397 34.488 ;
     RECT  14.785 35.856 15.509 54.024 ;
     RECT  15.397 2.304 15.541 34.488 ;
     RECT  15.509 35.856 15.541 53.928 ;
     RECT  15.541 2.304 16.013 53.928 ;
     RECT  16.013 2.736 16.373 53.928 ;
     RECT  16.373 2.736 16.409 35.352 ;
     RECT  16.373 36.384 16.589 53.928 ;
     RECT  16.409 2.736 17.125 26.376 ;
     RECT  16.409 27.456 17.237 35.352 ;
     RECT  17.125 2.304 17.521 26.376 ;
     RECT  17.237 27.456 17.521 35.208 ;
     RECT  17.521 2.304 18.205 35.208 ;
     RECT  16.589 36.384 18.205 53.544 ;
     RECT  18.205 2.304 18.608 53.544 ;
     RECT  18.608 2.148 18.712 54.012 ;
     RECT  18.712 2.418 18.904 53.742 ;
     RECT  18.904 2.544 18.965 50.664 ;
     RECT  18.965 2.592 20.117 50.664 ;
     RECT  18.904 53.088 20.257 53.304 ;
     RECT  20.257 52.992 20.329 53.304 ;
     RECT  20.329 52.992 20.485 53.448 ;
     RECT  18.904 51.744 20.509 51.768 ;
     RECT  20.485 52.992 20.509 53.64 ;
     RECT  20.117 23.664 21.121 50.664 ;
     RECT  20.117 2.592 21.329 22.584 ;
     RECT  21.121 23.616 21.329 50.664 ;
     RECT  21.329 2.592 21.413 50.664 ;
     RECT  21.413 2.592 21.553 22.584 ;
     RECT  21.553 2.4 21.625 22.584 ;
     RECT  21.413 23.616 21.697 50.664 ;
     RECT  20.509 51.744 21.697 53.64 ;
     RECT  21.625 2.304 22.561 22.584 ;
     RECT  21.697 23.616 22.561 53.64 ;
     RECT  22.561 2.304 22.781 53.64 ;
     RECT  22.781 2.304 22.811 52.536 ;
     RECT  22.811 2.256 24.001 52.536 ;
     RECT  22.781 53.52 24.001 53.64 ;
     RECT  24.001 2.256 24.008 53.64 ;
     RECT  24.008 2.148 24.112 54.012 ;
     RECT  24.112 2.256 24.433 54.012 ;
     RECT  24.433 2.256 24.659 54.84 ;
     RECT  24.659 2.256 25.121 54.744 ;
     RECT  25.121 2.304 25.235 54.744 ;
     RECT  25.235 2.304 25.517 54.12 ;
     RECT  25.477 56.016 25.621 56.04 ;
     RECT  25.621 55.248 25.715 56.04 ;
     RECT  25.715 56.016 26.993 56.04 ;
     RECT  25.517 2.352 27.749 54.12 ;
     RECT  27.749 2.688 27.893 54.12 ;
     RECT  27.893 2.688 27.929 54.024 ;
     RECT  27.929 2.688 29.269 53.64 ;
     RECT  29.269 2.256 29.408 53.64 ;
     RECT  29.408 2.148 29.512 54.012 ;
     RECT  29.512 2.256 29.704 53.742 ;
     RECT  29.704 2.256 29.981 53.64 ;
     RECT  29.981 2.352 30.089 53.64 ;
     RECT  30.089 2.352 30.521 53.112 ;
     RECT  30.521 2.496 30.737 53.112 ;
     RECT  30.737 2.496 31.205 52.872 ;
     RECT  31.205 2.736 31.993 52.872 ;
     RECT  31.993 2.736 32.348 53.016 ;
     RECT  32.348 2.736 32.435 53.784 ;
     RECT  32.435 2.736 33.469 53.544 ;
     RECT  33.469 2.304 33.973 53.544 ;
     RECT  33.973 2.256 34.808 53.544 ;
     RECT  34.808 2.148 34.912 54.012 ;
     RECT  34.912 2.256 35.104 53.742 ;
     RECT  35.104 2.256 35.219 53.544 ;
     RECT  35.219 2.496 35.273 53.544 ;
     RECT  35.273 2.64 36.349 53.544 ;
     RECT  36.349 2.64 36.529 53.592 ;
     RECT  36.529 2.448 36.637 53.592 ;
     RECT  36.637 2.352 37.001 53.592 ;
     RECT  37.001 2.496 37.073 53.592 ;
     RECT  37.073 2.544 37.187 53.592 ;
     RECT  37.187 2.544 38.869 53.4 ;
     RECT  38.869 2.544 39.409 53.784 ;
     RECT  39.409 2.256 40.208 53.784 ;
     RECT  40.208 2.148 40.312 54.012 ;
     RECT  40.312 2.418 40.504 53.742 ;
     RECT  40.504 2.496 43.369 53.352 ;
     RECT  43.369 2.448 43.441 53.352 ;
     RECT  43.441 2.448 43.763 54.12 ;
     RECT  43.763 2.448 43.955 53.928 ;
     RECT  43.225 55.344 44.233 55.368 ;
     RECT  43.955 2.448 44.237 53.832 ;
     RECT  44.233 55.296 44.531 55.368 ;
     RECT  44.237 2.448 45.025 53.784 ;
     RECT  45.061 55.968 45.245 56.04 ;
     RECT  45.025 2.256 45.608 53.784 ;
     RECT  45.608 2.148 45.637 54.012 ;
     RECT  45.637 2.148 45.712 54.168 ;
     RECT  45.712 2.352 45.733 54.168 ;
     RECT  45.245 55.968 45.925 55.992 ;
     RECT  45.733 2.352 45.965 54.216 ;
     RECT  45.965 2.352 46.001 54.12 ;
     RECT  46.001 2.352 46.163 54.072 ;
     RECT  45.925 55.248 46.937 55.992 ;
     RECT  46.937 55.968 46.981 55.992 ;
     RECT  46.163 2.352 47.693 53.832 ;
     RECT  47.693 2.352 47.725 53.784 ;
     RECT  47.725 2.256 47.891 53.784 ;
     RECT  47.891 2.256 48.701 53.688 ;
     RECT  46.981 55.968 48.869 56.04 ;
     RECT  48.701 2.736 48.913 53.688 ;
     RECT  48.869 55.92 48.913 56.04 ;
     RECT  48.913 55.92 49.667 56.136 ;
     RECT  48.913 2.736 49.715 54.168 ;
     RECT  49.667 55.968 50.249 56.136 ;
     RECT  49.715 2.736 51.008 53.64 ;
     RECT  51.008 2.148 51.112 54.012 ;
     RECT  51.112 2.148 51.304 53.742 ;
     RECT  51.397 1.152 51.481 1.176 ;
     RECT  51.548 0.528 51.635 0.552 ;
     RECT  51.304 2.148 51.721 53.544 ;
     RECT  51.965 0.096 53.221 0.12 ;
     RECT  53.221 0.096 53.585 0.168 ;
     RECT  53.585 0.096 53.693 0.216 ;
     RECT  53.693 0.096 53.777 0.552 ;
     RECT  51.721 1.728 54.173 53.544 ;
     RECT  53.777 0.096 54.469 0.168 ;
     RECT  54.469 0.048 54.515 0.168 ;
     RECT  54.173 1.728 55.145 53.4 ;
     RECT  55.145 18.288 55.253 53.4 ;
     RECT  55.145 1.728 55.283 17.304 ;
     RECT  55.283 1.728 55.289 17.16 ;
     RECT  55.253 18.288 55.325 19.608 ;
     RECT  55.253 24.336 55.325 53.4 ;
     RECT  55.289 1.872 55.901 17.16 ;
     RECT  55.253 20.592 56.221 23.16 ;
     RECT  55.325 24.336 56.221 53.304 ;
     RECT  56.221 20.592 56.365 53.304 ;
     RECT  55.901 2.148 56.408 17.16 ;
     RECT  55.325 18.576 56.408 19.608 ;
     RECT  56.365 20.592 56.408 53.544 ;
     RECT  56.408 2.148 56.512 54.012 ;
     RECT  56.512 2.418 56.704 53.742 ;
     RECT  54.515 0.048 56.801 0.12 ;
     RECT  56.704 24.672 56.801 53.592 ;
     RECT  56.801 24.672 57.053 50.952 ;
     RECT  56.704 2.544 57.059 23.304 ;
     RECT  57.059 18.432 57.197 23.304 ;
     RECT  56.801 0.048 57.413 0.072 ;
     RECT  57.053 24.96 57.769 50.952 ;
     RECT  56.801 51.936 57.769 53.592 ;
     RECT  57.769 24.96 57.829 53.592 ;
     RECT  57.197 22.992 57.913 23.304 ;
     RECT  57.913 22.992 58.021 23.448 ;
     RECT  57.829 24.96 58.021 53.64 ;
     RECT  57.059 2.544 58.163 17.16 ;
     RECT  57.197 18.432 58.345 21.672 ;
     RECT  58.021 22.992 58.561 53.64 ;
     RECT  58.345 18.432 58.705 21.768 ;
     RECT  58.561 22.8 58.705 53.64 ;
     RECT  58.705 17.808 58.745 53.64 ;
     RECT  58.745 51.888 58.777 53.64 ;
     RECT  58.745 17.808 59.033 50.904 ;
     RECT  50.249 56.112 59.065 56.136 ;
     RECT  58.163 2.544 59.677 16.68 ;
     RECT  59.033 17.808 59.677 18.792 ;
     RECT  59.033 20.16 59.821 50.904 ;
     RECT  58.777 51.888 59.821 54.12 ;
     RECT  59.677 2.544 60.001 18.792 ;
     RECT  60.001 2.544 60.421 19.176 ;
     RECT  59.821 20.16 60.421 54.12 ;
     RECT  59.065 55.296 61.669 56.136 ;
     RECT  60.421 2.544 61.765 54.12 ;
     RECT  61.765 2.544 61.808 54.168 ;
     RECT  61.669 55.248 61.811 56.136 ;
     RECT  61.808 2.148 61.912 54.168 ;
     RECT  61.912 2.418 62.099 54.168 ;
     RECT  62.099 2.418 62.104 54.12 ;
     RECT  61.811 55.296 62.489 56.136 ;
     RECT  62.104 26.64 63.029 54.12 ;
     RECT  63.029 38.496 63.317 54.12 ;
     RECT  63.029 26.64 63.529 37.464 ;
     RECT  63.317 38.496 63.635 52.2 ;
     RECT  63.635 38.496 63.772 43.704 ;
     RECT  63.635 44.784 64.001 52.2 ;
     RECT  62.104 2.544 64.028 25.032 ;
     RECT  63.529 26.064 64.028 37.464 ;
     RECT  64.028 2.544 64.069 37.464 ;
     RECT  63.772 38.496 64.069 43.656 ;
     RECT  62.489 55.296 64.403 56.04 ;
     RECT  64.069 2.544 64.469 43.656 ;
     RECT  64.469 14.544 64.505 43.656 ;
     RECT  64.001 45.84 64.573 52.2 ;
     RECT  63.317 53.568 64.573 54.12 ;
     RECT  64.001 44.784 64.969 44.856 ;
     RECT  64.573 45.84 64.969 54.12 ;
     RECT  64.469 2.544 64.973 13.416 ;
     RECT  64.505 14.544 65.369 18.312 ;
     RECT  64.973 3.024 65.437 13.416 ;
     RECT  65.369 14.544 65.437 17.448 ;
     RECT  64.505 19.344 65.621 43.656 ;
     RECT  65.621 37.728 65.797 43.656 ;
     RECT  64.969 44.784 65.797 54.12 ;
     RECT  65.437 3.024 65.837 17.448 ;
     RECT  65.837 3.024 65.941 16.92 ;
     RECT  64.403 55.92 66.049 56.04 ;
     RECT  65.621 19.344 66.121 36.504 ;
     RECT  66.049 55.296 66.227 56.04 ;
     RECT  66.227 55.776 66.341 56.04 ;
     RECT  66.121 19.248 66.373 36.504 ;
     RECT  66.373 18.576 66.409 36.504 ;
     RECT  66.409 18.192 66.661 36.504 ;
     RECT  65.797 37.728 66.661 54.12 ;
     RECT  66.341 55.776 66.995 55.992 ;
     RECT  66.995 55.872 67.187 55.992 ;
     RECT  65.941 2.256 67.208 16.92 ;
     RECT  66.661 18.192 67.208 54.12 ;
     RECT  67.208 2.148 67.237 54.12 ;
     RECT  67.237 2.148 67.312 54.168 ;
     RECT  67.312 2.256 67.333 54.168 ;
     RECT  67.333 2.256 67.504 54.216 ;
     RECT  67.504 3.984 67.529 22.968 ;
     RECT  67.529 3.984 67.565 21 ;
     RECT  67.187 55.968 67.621 55.992 ;
     RECT  67.504 30.24 67.717 54.216 ;
     RECT  67.717 30.24 67.997 54.696 ;
     RECT  67.997 30.24 68.033 54.12 ;
     RECT  67.621 55.968 68.173 56.04 ;
     RECT  67.504 2.256 68.249 2.28 ;
     RECT  67.565 3.984 68.321 20.712 ;
     RECT  68.033 49.584 68.429 54.12 ;
     RECT  68.173 55.248 68.435 56.04 ;
     RECT  68.429 53.472 68.681 54.12 ;
     RECT  67.504 24.672 68.749 29.064 ;
     RECT  68.749 24.336 68.773 29.064 ;
     RECT  68.033 30.24 68.773 48.552 ;
     RECT  68.677 1.104 68.785 1.128 ;
     RECT  68.321 4.176 68.857 20.712 ;
     RECT  67.529 21.984 68.857 22.968 ;
     RECT  68.773 24.336 68.861 48.552 ;
     RECT  68.785 0.144 68.957 1.128 ;
     RECT  68.857 4.176 69.001 22.968 ;
     RECT  68.681 53.472 69.077 53.928 ;
     RECT  68.861 29.664 69.109 48.552 ;
     RECT  68.429 49.584 69.109 52.44 ;
     RECT  69.109 29.664 69.113 52.44 ;
     RECT  68.435 56.016 69.113 56.04 ;
     RECT  69.001 4.176 69.181 23.016 ;
     RECT  69.181 4.176 69.217 23.064 ;
     RECT  68.861 24.336 69.217 28.488 ;
     RECT  69.113 29.952 69.257 52.44 ;
     RECT  69.257 30.384 69.293 52.44 ;
     RECT  69.217 4.176 69.401 28.488 ;
     RECT  68.749 2.304 69.445 2.904 ;
     RECT  69.293 30.384 69.509 41.4 ;
     RECT  68.957 0.096 69.533 1.128 ;
     RECT  69.445 2.208 69.533 2.904 ;
     RECT  69.533 0.096 69.613 2.904 ;
     RECT  69.401 4.176 69.613 28.2 ;
     RECT  69.293 42.768 69.653 52.44 ;
     RECT  69.613 0.096 69.779 28.2 ;
     RECT  69.779 1.152 69.797 28.2 ;
     RECT  69.077 53.472 69.797 53.496 ;
     RECT  69.797 1.68 69.833 28.2 ;
     RECT  69.833 1.68 69.941 13.512 ;
     RECT  69.941 13.488 70.013 13.512 ;
     RECT  69.833 14.496 70.085 28.2 ;
     RECT  69.509 30.384 70.193 41.208 ;
     RECT  69.941 1.68 70.301 12.408 ;
     RECT  70.301 1.68 70.451 12.36 ;
     RECT  70.193 30.384 70.621 35.256 ;
     RECT  69.653 42.768 70.645 43.656 ;
     RECT  69.653 44.928 70.645 52.44 ;
     RECT  70.193 36.576 70.693 41.208 ;
     RECT  70.085 14.496 70.733 23.064 ;
     RECT  70.693 36.576 70.769 41.544 ;
     RECT  69.779 0.096 70.805 0.168 ;
     RECT  70.451 1.728 70.841 12.36 ;
     RECT  70.733 14.496 70.913 14.568 ;
     RECT  70.805 0.144 70.949 0.168 ;
     RECT  70.645 42.768 70.981 52.44 ;
     RECT  70.085 24.336 71.125 28.2 ;
     RECT  70.769 38.208 71.125 41.544 ;
     RECT  70.981 42.768 71.125 53.016 ;
     RECT  71.125 24.336 71.161 28.248 ;
     RECT  70.621 30.144 71.197 35.256 ;
     RECT  70.769 36.576 71.197 37.08 ;
     RECT  70.733 16.032 71.228 23.064 ;
     RECT  71.161 24.336 71.228 29.064 ;
     RECT  70.841 1.728 71.237 12.312 ;
     RECT  71.125 38.208 71.237 53.016 ;
     RECT  71.237 2.736 71.273 12.312 ;
     RECT  71.228 16.032 71.273 29.064 ;
     RECT  71.237 38.256 71.273 45.96 ;
     RECT  71.273 3.648 71.345 12.312 ;
     RECT  71.273 16.032 71.345 28.44 ;
     RECT  71.197 30.144 71.345 37.08 ;
     RECT  71.345 30.288 71.453 37.08 ;
     RECT  71.345 5.376 71.561 12.312 ;
     RECT  70.913 14.544 71.597 14.568 ;
     RECT  71.237 47.184 71.629 53.016 ;
     RECT  71.237 1.728 71.633 1.752 ;
     RECT  71.561 6 71.881 12.312 ;
     RECT  71.881 6 71.989 12.552 ;
     RECT  71.629 47.184 72.241 53.544 ;
     RECT  71.453 30.384 72.313 37.08 ;
     RECT  71.273 38.256 72.313 42.024 ;
     RECT  71.345 16.032 72.421 17.976 ;
     RECT  71.989 6 72.469 13.08 ;
     RECT  72.097 14.688 72.469 14.712 ;
     RECT  72.241 47.088 72.601 53.544 ;
     RECT  71.345 3.648 72.608 3.672 ;
     RECT  72.469 6 72.608 13.656 ;
     RECT  72.469 14.688 72.608 14.904 ;
     RECT  72.421 15.984 72.608 17.976 ;
     RECT  71.345 18.96 72.608 28.44 ;
     RECT  72.313 30.384 72.608 42.024 ;
     RECT  71.273 43.008 72.608 45.96 ;
     RECT  72.601 47.04 72.608 53.544 ;
     RECT  72.608 2.148 72.712 54.012 ;
     RECT  72.712 2.418 72.904 53.742 ;
     RECT  72.904 21.504 72.965 28.488 ;
     RECT  72.904 29.616 72.965 32.856 ;
     RECT  72.965 23.328 73.001 28.488 ;
     RECT  72.904 47.04 73.073 50.904 ;
     RECT  72.904 5.328 73.289 12.312 ;
     RECT  72.904 43.632 73.325 46.056 ;
     RECT  73.001 23.376 73.541 28.44 ;
     RECT  72.965 29.616 73.757 32.76 ;
     RECT  72.904 52.416 73.757 53.016 ;
     RECT  73.541 25.536 74.009 28.44 ;
     RECT  73.325 43.92 74.009 46.056 ;
     RECT  73.289 5.328 74.041 5.496 ;
     RECT  73.289 6.48 74.113 12.312 ;
     RECT  72.904 13.632 74.113 13.656 ;
     RECT  73.073 50.592 74.113 50.904 ;
     RECT  73.757 52.416 74.113 52.44 ;
     RECT  73.757 29.616 74.153 32.52 ;
     RECT  72.904 3.408 74.185 4.248 ;
     RECT  74.041 5.232 74.185 5.496 ;
     RECT  74.185 3.408 74.189 5.496 ;
     RECT  74.189 3.648 74.257 5.496 ;
     RECT  74.113 6.48 74.257 13.656 ;
     RECT  74.009 43.92 74.293 44.424 ;
     RECT  74.009 25.728 74.297 28.44 ;
     RECT  74.293 43.632 74.329 44.424 ;
     RECT  74.009 45.504 74.369 46.056 ;
     RECT  72.904 33.888 74.389 42.168 ;
     RECT  74.329 43.344 74.389 44.424 ;
     RECT  72.904 15.264 74.401 20.424 ;
     RECT  72.965 21.504 74.401 22.2 ;
     RECT  74.389 33.888 74.441 44.424 ;
     RECT  74.441 37.92 74.476 44.424 ;
     RECT  74.401 15.264 74.617 22.2 ;
     RECT  73.541 23.376 74.617 24.072 ;
     RECT  73.073 47.04 74.617 49.608 ;
     RECT  74.113 50.592 74.617 52.44 ;
     RECT  74.441 33.888 74.661 36.504 ;
     RECT  74.297 28.416 74.729 28.44 ;
     RECT  74.476 37.92 74.765 42.12 ;
     RECT  74.617 14.688 74.945 24.072 ;
     RECT  74.257 3.648 74.963 13.656 ;
     RECT  74.945 14.688 75.004 22.776 ;
     RECT  75.004 14.688 75.053 19.848 ;
     RECT  75.004 21.216 75.053 22.776 ;
     RECT  74.476 43.392 75.089 44.424 ;
     RECT  74.369 45.552 75.116 46.056 ;
     RECT  74.617 47.04 75.116 52.44 ;
     RECT  75.053 14.688 75.125 19.8 ;
     RECT  75.116 45.552 75.203 52.44 ;
     RECT  74.153 29.952 75.205 32.52 ;
     RECT  74.661 33.744 75.205 36.504 ;
     RECT  74.963 4.08 75.26 13.656 ;
     RECT  75.125 14.688 75.26 14.904 ;
     RECT  75.205 29.952 75.297 36.504 ;
     RECT  75.26 4.08 75.347 14.904 ;
     RECT  74.297 25.728 75.373 26.808 ;
     RECT  75.373 25.728 75.5 27.336 ;
     RECT  75.089 43.872 75.517 44.424 ;
     RECT  75.203 45.552 75.517 46.104 ;
     RECT  75.5 25.152 75.587 27.336 ;
     RECT  75.053 21.504 75.629 22.776 ;
     RECT  75.297 33.024 75.629 36.504 ;
     RECT  75.297 29.952 75.637 31.56 ;
     RECT  75.203 47.328 75.661 52.44 ;
     RECT  75.481 53.712 75.661 53.736 ;
     RECT  75.587 25.824 75.697 27.336 ;
     RECT  75.637 28.464 75.697 31.56 ;
     RECT  75.629 21.744 75.701 22.776 ;
     RECT  74.765 37.968 75.769 42.12 ;
     RECT  75.347 4.08 75.773 13.656 ;
     RECT  75.697 25.824 75.773 31.56 ;
     RECT  75.773 26.64 75.809 31.56 ;
     RECT  75.809 26.784 75.845 31.56 ;
     RECT  75.629 36.48 75.845 36.504 ;
     RECT  74.945 24.048 75.949 24.072 ;
     RECT  75.769 37.872 75.949 42.12 ;
     RECT  75.553 54.72 75.985 54.744 ;
     RECT  75.701 21.744 75.989 22.296 ;
     RECT  75.949 23.376 75.989 24.072 ;
     RECT  75.661 47.328 76.021 53.736 ;
     RECT  75.985 54.72 76.021 54.792 ;
     RECT  75.347 14.688 76.093 14.904 ;
     RECT  75.125 16.032 76.093 19.8 ;
     RECT  75.949 37.872 76.093 42.888 ;
     RECT  76.021 47.328 76.124 54.792 ;
     RECT  76.093 37.728 76.133 42.888 ;
     RECT  76.133 37.728 76.165 42.12 ;
     RECT  76.093 14.688 76.273 19.8 ;
     RECT  75.773 4.08 76.309 13.128 ;
     RECT  76.124 47.328 76.357 55.32 ;
     RECT  76.309 3.936 76.421 13.128 ;
     RECT  76.357 47.328 76.493 56.04 ;
     RECT  75.845 26.784 76.529 29.592 ;
     RECT  75.517 43.872 76.597 46.104 ;
     RECT  75.629 33.024 76.669 35.256 ;
     RECT  76.529 26.784 76.837 27.864 ;
     RECT  76.273 14.688 76.849 20.616 ;
     RECT  75.989 21.744 76.849 21.768 ;
     RECT  76.837 26.4 76.849 27.864 ;
     RECT  76.849 14.688 76.889 21.768 ;
     RECT  76.889 16.272 76.997 21.768 ;
     RECT  76.597 43.248 77.101 46.104 ;
     RECT  76.493 47.328 77.101 55.32 ;
     RECT  75.845 30.576 77.137 31.56 ;
     RECT  76.669 32.976 77.137 35.256 ;
     RECT  76.421 11.76 77.173 13.128 ;
     RECT  76.849 26.208 77.317 27.864 ;
     RECT  77.137 30.576 77.461 35.256 ;
     RECT  77.101 43.248 77.501 55.32 ;
     RECT  76.237 24.432 77.533 24.456 ;
     RECT  77.317 25.488 77.533 27.864 ;
     RECT  76.529 29.088 77.533 29.592 ;
     RECT  77.461 30.576 77.533 35.496 ;
     RECT  77.533 24.432 77.569 27.864 ;
     RECT  77.501 55.2 77.753 55.32 ;
     RECT  76.421 3.936 77.785 10.44 ;
     RECT  77.173 11.76 77.785 13.656 ;
     RECT  77.753 55.248 77.845 55.32 ;
     RECT  77.533 29.088 77.965 35.496 ;
     RECT  76.165 36.816 77.965 42.12 ;
     RECT  77.845 55.248 77.969 55.992 ;
     RECT  76.889 14.688 78.001 15.24 ;
     RECT  76.997 16.272 78.001 18.168 ;
     RECT  77.785 3.312 78.008 13.656 ;
     RECT  78.001 14.688 78.008 18.168 ;
     RECT  76.997 19.248 78.008 21.768 ;
     RECT  75.989 23.376 78.008 23.4 ;
     RECT  77.569 24.432 78.008 27.912 ;
     RECT  77.965 29.088 78.008 42.12 ;
     RECT  77.501 43.248 78.008 54.12 ;
     RECT  78.008 2.148 78.112 54.12 ;
     RECT  77.969 55.872 78.181 55.992 ;
     RECT  78.181 55.872 78.227 56.04 ;
     RECT  78.112 2.418 78.304 54.12 ;
     RECT  78.304 47.856 78.365 49.224 ;
     RECT  78.304 15.408 78.401 20.424 ;
     RECT  78.304 28.944 78.401 29.88 ;
     RECT  78.304 11.952 78.419 12.024 ;
     RECT  78.304 13.056 78.419 13.896 ;
     RECT  78.401 15.408 78.419 20.04 ;
     RECT  78.304 39.936 78.419 43.032 ;
     RECT  78.227 56.016 78.419 56.04 ;
     RECT  78.304 22.752 78.437 22.776 ;
     RECT  78.304 46.272 78.437 46.824 ;
     RECT  78.365 48.384 78.437 49.224 ;
     RECT  78.419 15.408 78.46 16.344 ;
     RECT  78.304 44.448 78.467 45.288 ;
     RECT  78.419 13.056 78.473 13.08 ;
     RECT  78.46 16.32 78.473 16.344 ;
     RECT  78.304 24.48 78.473 27.672 ;
     RECT  78.419 17.616 78.508 20.04 ;
     RECT  78.304 33.264 78.509 33.288 ;
     RECT  78.304 38.352 78.509 38.376 ;
     RECT  78.473 25.2 78.515 27.672 ;
     RECT  78.304 30.864 78.528 32.04 ;
     RECT  78.508 17.616 78.545 17.736 ;
     RECT  78.304 50.64 78.545 54.12 ;
     RECT  78.304 3.312 78.581 10.968 ;
     RECT  78.515 25.2 78.581 25.848 ;
     RECT  78.515 27.504 78.581 27.672 ;
     RECT  78.419 39.936 78.581 42.504 ;
     RECT  78.467 44.448 78.581 45.24 ;
     RECT  78.437 46.8 78.581 46.824 ;
     RECT  78.581 25.536 78.617 25.848 ;
     RECT  78.304 34.464 78.617 34.488 ;
     RECT  78.545 50.64 78.617 50.664 ;
     RECT  78.545 51.648 78.617 53.64 ;
     RECT  78.419 12 78.653 12.024 ;
     RECT  78.581 27.504 78.653 27.528 ;
     RECT  78.617 51.792 78.653 53.304 ;
     RECT  78.508 18.72 78.659 20.04 ;
     RECT  78.617 25.776 78.689 25.848 ;
     RECT  78.581 39.936 78.689 41.496 ;
     RECT  78.401 29.856 78.725 29.88 ;
     RECT  78.528 30.864 78.725 31.704 ;
     RECT  78.581 42.48 78.725 42.504 ;
     RECT  78.581 3.312 78.761 10.152 ;
     RECT  78.689 25.776 78.761 25.8 ;
     RECT  78.304 36.816 78.761 36.84 ;
     RECT  78.689 39.936 78.761 39.96 ;
     RECT  78.437 48.384 78.761 49.176 ;
     RECT  78.659 19.536 78.833 19.656 ;
     RECT  78.761 48.384 78.833 48.408 ;
     RECT  78.304 35.472 78.869 35.496 ;
     RECT  78.581 44.448 78.869 44.904 ;
     RECT  78.653 51.792 78.869 53.016 ;
     RECT  78.761 3.312 78.905 4.248 ;
     RECT  78.725 30.864 78.905 30.888 ;
     RECT  78.869 44.448 78.905 44.472 ;
     RECT  78.869 51.792 78.941 51.816 ;
     RECT  78.761 5.472 78.977 9.816 ;
     RECT  78.869 52.992 79.013 53.016 ;
     RECT  78.545 17.616 79.193 17.64 ;
     RECT  78.977 6.048 79.337 9.384 ;
     RECT  79.337 6.672 79.733 9.384 ;
     RECT  78.905 3.84 80.341 4.248 ;
     RECT  80.305 5.52 80.341 5.544 ;
     RECT  79.733 6.96 80.341 9.384 ;
     RECT  80.341 3.792 80.881 5.544 ;
     RECT  80.881 3.792 80.953 5.928 ;
     RECT  80.341 6.96 80.953 9.864 ;
     RECT  80.953 3.792 82.044 9.864 ;
    LAYER M5 ;
     RECT  51.408 0.016 54.408 0.037 ;
     RECT  51.408 0.037 54.504 0.179 ;
     RECT  68.88 0.016 70.92 1.139 ;
     RECT  51.408 0.179 54.408 1.907 ;
     RECT  51.408 1.907 52.776 2.137 ;
     RECT  2.4 2.137 2.52 2.151 ;
     RECT  7.8 2.137 7.92 2.151 ;
     RECT  13.2 2.137 13.32 2.151 ;
     RECT  18.6 2.137 18.72 2.151 ;
     RECT  24 2.137 24.12 2.151 ;
     RECT  29.4 2.137 29.52 2.151 ;
     RECT  34.8 2.137 34.92 2.151 ;
     RECT  40.2 2.137 40.32 2.151 ;
     RECT  45.6 2.137 45.72 2.151 ;
     RECT  56.4 2.137 56.52 2.151 ;
     RECT  61.8 2.137 61.92 2.151 ;
     RECT  67.2 2.137 67.32 2.151 ;
     RECT  72.6 2.137 72.72 2.151 ;
     RECT  78 2.137 78.12 2.151 ;
     RECT  69.456 1.139 70.92 2.243 ;
     RECT  29.4 2.151 29.712 2.245 ;
     RECT  34.8 2.151 35.112 2.245 ;
     RECT  45.6 2.151 45.912 2.245 ;
     RECT  70.224 2.243 70.92 2.291 ;
     RECT  51 2.137 52.776 2.387 ;
     RECT  53.904 1.907 54.408 2.531 ;
     RECT  29.28 2.245 29.712 2.677 ;
     RECT  51 2.387 51.312 2.725 ;
     RECT  13.2 2.151 13.512 2.869 ;
     RECT  52.464 2.387 52.776 2.963 ;
     RECT  29.28 2.677 29.976 3.109 ;
     RECT  29.28 3.109 30.936 3.157 ;
     RECT  27.456 2.773 27.48 3.299 ;
     RECT  29.28 3.157 31.896 3.299 ;
     RECT  61.8 2.151 62.112 3.397 ;
     RECT  16.608 3.541 16.632 3.589 ;
     RECT  50.4 2.725 51.312 3.589 ;
     RECT  13.2 2.869 14.328 3.683 ;
     RECT  50.4 3.589 52.248 3.731 ;
     RECT  40.2 2.151 40.512 3.877 ;
     RECT  47.76 3.397 47.784 3.877 ;
     RECT  31.872 3.299 31.896 3.923 ;
     RECT  7.8 2.151 8.112 3.925 ;
     RECT  18.6 2.151 18.912 3.925 ;
     RECT  36.576 2.533 36.6 4.069 ;
     RECT  45.072 2.245 45.912 4.069 ;
     RECT  53.568 3.205 53.592 4.069 ;
     RECT  54.672 3.829 54.696 4.069 ;
     RECT  43.056 2.629 43.08 4.115 ;
     RECT  53.568 4.069 54.696 4.115 ;
     RECT  61.008 3.397 62.112 4.115 ;
     RECT  29.4 3.299 30.84 4.307 ;
     RECT  34.8 2.245 35.208 4.405 ;
     RECT  39.552 3.877 40.512 4.405 ;
     RECT  14.784 4.117 14.808 4.499 ;
     RECT  34.8 4.405 35.256 4.501 ;
     RECT  47.76 3.877 47.832 4.547 ;
     RECT  39.552 4.405 40.632 4.597 ;
     RECT  39.552 4.597 40.872 4.643 ;
     RECT  36.576 4.069 37.032 4.645 ;
     RECT  18.6 3.925 19.896 4.693 ;
     RECT  18.6 4.693 19.992 4.739 ;
     RECT  22.416 2.629 22.44 4.931 ;
     RECT  36.48 4.645 37.032 4.981 ;
     RECT  61.584 4.115 62.112 5.029 ;
     RECT  36.48 4.981 37.08 5.123 ;
     RECT  40.2 4.643 40.872 5.123 ;
     RECT  7.68 3.925 8.112 5.125 ;
     RECT  45.072 4.069 46.728 5.125 ;
     RECT  47.808 4.547 47.832 5.125 ;
     RECT  67.2 2.151 67.512 5.125 ;
     RECT  16.608 3.589 17.448 5.171 ;
     RECT  47.808 5.125 48.024 5.171 ;
     RECT  34.8 4.501 35.304 5.173 ;
     RECT  36.48 5.123 36.504 5.173 ;
     RECT  67.2 5.125 67.608 5.173 ;
     RECT  34.8 5.173 36.504 5.315 ;
     RECT  59.616 3.301 59.64 5.317 ;
     RECT  45.024 5.125 46.728 5.363 ;
     RECT  29.4 4.307 29.976 5.365 ;
     RECT  45.024 5.363 45.912 5.507 ;
     RECT  59.616 5.317 60.312 5.555 ;
     RECT  61.584 5.029 62.616 5.555 ;
     RECT  11.424 3.685 11.448 5.747 ;
     RECT  17.232 5.171 17.448 5.747 ;
     RECT  19.968 4.739 19.992 5.747 ;
     RECT  50.4 3.731 51.312 5.795 ;
     RECT  49.056 5.701 49.08 5.987 ;
     RECT  24 2.151 24.312 6.037 ;
     RECT  25.536 4.501 25.56 6.037 ;
     RECT  29.4 5.365 30.216 6.323 ;
     RECT  59.616 5.555 59.64 6.371 ;
     RECT  56.4 2.151 56.712 6.373 ;
     RECT  24 6.037 25.56 6.419 ;
     RECT  34.8 5.315 36.024 6.469 ;
     RECT  61.584 5.555 62.112 6.563 ;
     RECT  72.6 2.151 72.912 6.613 ;
     RECT  56.4 6.373 57.672 6.707 ;
     RECT  56.4 6.707 57.576 6.709 ;
     RECT  51 5.795 51.312 6.757 ;
     RECT  34.8 6.469 36.504 6.853 ;
     RECT  67.2 5.173 67.704 6.949 ;
     RECT  29.4 6.323 29.712 6.997 ;
     RECT  34.8 6.853 36.792 7.139 ;
     RECT  7.392 5.125 8.112 7.189 ;
     RECT  45.504 5.507 45.912 7.237 ;
     RECT  2.4 2.151 2.712 7.381 ;
     RECT  18.6 4.739 18.912 7.381 ;
     RECT  40.2 5.123 40.512 7.381 ;
     RECT  34.8 7.139 35.88 7.427 ;
     RECT  65.664 3.829 65.688 7.429 ;
     RECT  10.416 6.805 10.44 7.475 ;
     RECT  29.28 6.997 29.712 7.525 ;
     RECT  24 6.419 24.408 7.571 ;
     RECT  50.88 6.757 51.312 7.621 ;
     RECT  78 2.151 78.312 7.669 ;
     RECT  22.08 6.805 22.104 7.763 ;
     RECT  50.88 7.621 51.528 7.763 ;
     RECT  50.88 7.763 51.312 7.765 ;
     RECT  44.88 7.237 45.912 7.811 ;
     RECT  26.688 6.277 26.712 7.859 ;
     RECT  61.68 6.563 62.112 7.861 ;
     RECT  67.2 6.949 68.136 7.861 ;
     RECT  12.144 6.901 12.168 7.907 ;
     RECT  37.056 7.621 37.08 7.907 ;
     RECT  48 5.171 48.024 7.909 ;
     RECT  29.088 7.525 29.712 7.957 ;
     RECT  15.888 7.189 15.912 8.003 ;
     RECT  78 7.669 78.648 8.051 ;
     RECT  31.776 6.709 31.8 8.147 ;
     RECT  6.288 7.189 6.312 8.197 ;
     RECT  7.344 7.189 8.112 8.293 ;
     RECT  17.232 5.747 17.256 8.341 ;
     RECT  18.384 7.381 18.912 8.341 ;
     RECT  17.232 8.341 18.912 8.387 ;
     RECT  48 7.909 48.216 8.437 ;
     RECT  69.504 7.957 69.528 8.437 ;
     RECT  27.312 8.389 27.336 8.531 ;
     RECT  74.928 3.637 74.952 8.533 ;
     RECT  48 8.437 49.032 8.579 ;
     RECT  55.44 6.709 57.576 8.579 ;
     RECT  74.688 8.533 74.952 8.579 ;
     RECT  40.2 7.381 40.968 8.581 ;
     RECT  33.6 7.381 33.624 8.771 ;
     RECT  50.4 7.765 51.312 8.821 ;
     RECT  48 8.579 48.216 8.869 ;
     RECT  59.568 6.709 59.592 8.869 ;
     RECT  47.904 8.869 48.216 8.915 ;
     RECT  13.2 3.683 13.512 8.917 ;
     RECT  53.568 4.115 54.168 8.917 ;
     RECT  55.44 8.579 57 8.917 ;
     RECT  65.424 7.429 65.688 8.917 ;
     RECT  59.424 8.869 59.592 8.963 ;
     RECT  61.536 7.861 62.112 8.963 ;
     RECT  67.2 7.861 68.424 8.963 ;
     RECT  7.344 8.293 8.52 9.011 ;
     RECT  2.4 7.381 2.904 9.013 ;
     RECT  4.032 8.485 4.056 9.013 ;
     RECT  43.872 8.869 43.896 9.013 ;
     RECT  50.4 8.821 52.152 9.013 ;
     RECT  63.696 7.813 63.72 9.059 ;
     RECT  40.2 8.581 41.016 9.061 ;
     RECT  5.568 8.197 6.312 9.155 ;
     RECT  25.536 6.419 25.56 9.157 ;
     RECT  45.504 7.811 45.912 9.157 ;
     RECT  25.536 9.157 25.656 9.203 ;
     RECT  61.68 8.963 62.112 9.203 ;
     RECT  53.568 8.917 57 9.347 ;
     RECT  69.504 8.437 70.152 9.395 ;
     RECT  47.904 8.915 48.024 9.443 ;
     RECT  43.44 9.013 43.896 9.637 ;
     RECT  47.904 9.443 47.928 9.683 ;
     RECT  40.2 9.061 41.688 9.685 ;
     RECT  28.512 7.957 29.712 9.731 ;
     RECT  45.504 9.157 46.008 9.731 ;
     RECT  50.016 9.013 52.152 9.731 ;
     RECT  5.568 9.155 6.264 9.779 ;
     RECT  16.08 9.589 16.104 9.925 ;
     RECT  56.4 9.347 57 9.925 ;
     RECT  38.592 8.869 38.616 9.971 ;
     RECT  5.616 9.779 6.264 10.019 ;
     RECT  2.4 9.013 4.056 10.067 ;
     RECT  16.08 9.925 16.392 10.069 ;
     RECT  34.8 7.427 35.304 10.069 ;
     RECT  74.688 8.579 74.712 10.069 ;
     RECT  29.088 9.731 29.712 10.115 ;
     RECT  61.8 9.203 62.112 10.165 ;
     RECT  50.016 9.731 51.312 10.213 ;
     RECT  40.2 9.685 42.072 10.307 ;
     RECT  10.224 7.957 10.248 10.309 ;
     RECT  10.224 10.309 10.488 10.355 ;
     RECT  34.368 10.069 35.304 10.355 ;
     RECT  65.136 8.917 65.688 10.355 ;
     RECT  29.136 10.115 29.712 10.357 ;
     RECT  31.008 9.925 31.032 10.357 ;
     RECT  2.4 10.067 3.768 10.403 ;
     RECT  70.128 9.395 70.152 10.451 ;
     RECT  73.92 10.069 74.712 10.453 ;
     RECT  49.92 10.213 51.312 10.501 ;
     RECT  53.568 9.347 54.744 10.595 ;
     RECT  76.8 6.229 76.824 10.597 ;
     RECT  49.44 10.501 51.312 10.643 ;
     RECT  65.664 10.355 65.688 10.643 ;
     RECT  68.64 10.309 68.664 10.645 ;
     RECT  73.92 10.453 74.856 10.645 ;
     RECT  76.272 10.597 76.824 10.645 ;
     RECT  24 7.571 24.312 10.741 ;
     RECT  56.4 9.925 57.72 10.789 ;
     RECT  29.136 10.357 31.032 10.837 ;
     RECT  32.304 9.493 32.328 10.837 ;
     RECT  59.424 8.963 59.448 10.883 ;
     RECT  23.376 10.741 24.312 10.933 ;
     RECT  25.632 9.203 25.656 10.933 ;
     RECT  17.616 8.387 18.912 10.981 ;
     RECT  53.568 10.595 54.696 11.077 ;
     RECT  61.8 10.165 62.232 11.077 ;
     RECT  29.136 10.837 32.328 11.123 ;
     RECT  53.04 11.077 54.696 11.123 ;
     RECT  23.376 10.933 25.656 11.171 ;
     RECT  40.2 10.307 41.88 11.171 ;
     RECT  43.44 9.637 44.088 11.171 ;
     RECT  17.616 10.981 19.56 11.173 ;
     RECT  20.64 9.541 20.664 11.173 ;
     RECT  53.04 11.123 54.168 11.219 ;
     RECT  56.304 10.789 57.72 11.221 ;
     RECT  5.616 10.019 6.072 11.269 ;
     RECT  7.344 9.011 8.424 11.269 ;
     RECT  37.008 9.637 37.032 11.317 ;
     RECT  38.928 9.973 38.952 11.317 ;
     RECT  49.728 10.643 51.312 11.363 ;
     RECT  61.392 11.077 62.232 11.363 ;
     RECT  37.008 11.317 37.128 11.365 ;
     RECT  50.16 11.363 51.312 11.459 ;
     RECT  73.92 10.645 76.824 11.507 ;
     RECT  36.384 11.365 37.128 11.509 ;
     RECT  43.776 11.171 44.088 11.603 ;
     RECT  56.304 11.221 57.912 11.651 ;
     RECT  13.2 8.917 13.608 11.653 ;
     RECT  15.984 10.069 16.392 11.653 ;
     RECT  17.616 11.173 20.664 11.699 ;
     RECT  74.832 11.507 76.824 11.699 ;
     RECT  61.8 11.363 62.232 11.795 ;
     RECT  68.64 10.645 68.952 11.845 ;
     RECT  71.904 6.613 72.912 11.891 ;
     RECT  2.4 10.403 2.712 11.941 ;
     RECT  3.744 10.403 3.768 11.941 ;
     RECT  12.288 11.653 13.608 11.941 ;
     RECT  36.384 11.509 37.896 11.941 ;
     RECT  38.928 11.317 39.144 11.941 ;
     RECT  48.144 11.317 48.168 11.941 ;
     RECT  50.4 11.459 51.312 11.941 ;
     RECT  78 8.051 78.312 11.941 ;
     RECT  68.592 11.845 68.952 11.987 ;
     RECT  18.048 11.699 20.664 12.035 ;
     RECT  74.832 11.699 75.48 12.035 ;
     RECT  15.984 11.653 16.488 12.037 ;
     RECT  20.256 12.035 20.664 12.085 ;
     RECT  34.368 10.355 35.256 12.085 ;
     RECT  36.384 11.941 39.144 12.085 ;
     RECT  5.616 11.269 8.424 12.179 ;
     RECT  34.368 12.085 39.144 12.181 ;
     RECT  40.2 11.171 41.256 12.181 ;
     RECT  34.368 12.181 42.168 12.227 ;
     RECT  75.408 12.035 75.48 12.227 ;
     RECT  10.464 10.355 10.488 12.275 ;
     RECT  50.4 11.941 51.528 12.275 ;
     RECT  12.288 11.941 13.8 12.277 ;
     RECT  34.368 12.227 39 12.371 ;
     RECT  20.256 12.085 20.952 12.421 ;
     RECT  27.024 9.781 27.048 12.421 ;
     RECT  12.288 12.277 14.088 12.467 ;
     RECT  18.048 12.035 19.032 12.467 ;
     RECT  22.272 9.637 22.296 12.469 ;
     RECT  18.336 12.467 19.032 12.515 ;
     RECT  20.256 12.421 21 12.515 ;
     RECT  12.912 12.467 14.088 12.517 ;
     RECT  15.312 12.037 16.488 12.517 ;
     RECT  29.136 11.123 32.04 12.517 ;
     RECT  68.592 11.987 68.616 12.517 ;
     RECT  12.912 12.517 16.488 12.563 ;
     RECT  20.688 12.515 21 12.563 ;
     RECT  50.832 12.275 51.528 12.659 ;
     RECT  22.176 12.469 22.296 12.757 ;
     RECT  23.376 11.171 24.312 12.803 ;
     RECT  36.288 12.371 39 12.803 ;
     RECT  56.4 11.651 57.912 12.803 ;
     RECT  21.984 12.757 22.296 12.899 ;
     RECT  26.208 12.421 27.048 12.899 ;
     RECT  48.096 11.941 48.168 12.947 ;
     RECT  48.144 12.947 48.168 12.949 ;
     RECT  49.152 12.229 49.176 12.949 ;
     RECT  14.832 12.563 16.488 12.997 ;
     RECT  45.504 9.731 45.912 12.997 ;
     RECT  2.4 11.941 3.768 13.043 ;
     RECT  3.744 13.043 3.768 13.045 ;
     RECT  5.712 12.179 8.424 13.045 ;
     RECT  61.8 11.795 62.112 13.045 ;
     RECT  65.424 11.845 65.448 13.091 ;
     RECT  72 11.891 72.912 13.091 ;
     RECT  37.872 12.803 39 13.139 ;
     RECT  60.384 11.077 60.408 13.139 ;
     RECT  75.456 12.227 75.48 13.139 ;
     RECT  48.144 12.949 49.176 13.141 ;
     RECT  36.288 12.803 36.456 13.187 ;
     RECT  45.072 12.997 45.912 13.187 ;
     RECT  37.92 13.139 39 13.235 ;
     RECT  48.144 13.141 49.32 13.237 ;
     RECT  29.136 12.517 32.616 13.283 ;
     RECT  26.208 12.899 26.952 13.331 ;
     RECT  68.496 12.517 68.616 13.331 ;
     RECT  67.2 8.963 67.512 13.333 ;
     RECT  20.688 12.563 20.952 13.475 ;
     RECT  53.184 11.219 54.168 13.477 ;
     RECT  18.336 12.515 18.912 13.523 ;
     RECT  5.712 13.045 8.568 13.571 ;
     RECT  12.912 12.563 13.8 13.621 ;
     RECT  14.832 12.997 17.256 13.621 ;
     RECT  68.88 13.333 68.904 13.669 ;
     RECT  48.144 13.237 49.56 13.763 ;
     RECT  68.88 13.669 69.096 13.763 ;
     RECT  34.368 12.371 35.256 13.813 ;
     RECT  36.288 13.187 36.408 13.813 ;
     RECT  45.6 13.187 45.912 13.813 ;
     RECT  31.776 13.283 32.616 13.859 ;
     RECT  69.072 13.763 69.096 13.859 ;
     RECT  5.712 13.571 8.424 13.907 ;
     RECT  12.912 13.621 17.256 13.909 ;
     RECT  45.6 13.813 46.776 14.051 ;
     RECT  48.144 13.763 48.456 14.051 ;
     RECT  22.176 12.899 22.296 14.101 ;
     RECT  33.072 13.957 33.096 14.101 ;
     RECT  33.072 14.101 33.192 14.147 ;
     RECT  45.6 14.051 46.488 14.195 ;
     RECT  11.952 13.909 17.256 14.197 ;
     RECT  29.136 13.283 30.744 14.197 ;
     RECT  34.368 13.813 36.408 14.197 ;
     RECT  53.136 13.477 54.168 14.197 ;
     RECT  33.168 14.147 33.192 14.243 ;
     RECT  49.536 13.763 49.56 14.243 ;
     RECT  53.136 14.197 54.552 14.243 ;
     RECT  75.312 13.621 75.336 14.339 ;
     RECT  26.928 13.331 26.952 14.341 ;
     RECT  29.088 14.197 30.744 14.341 ;
     RECT  31.776 13.859 31.944 14.341 ;
     RECT  28.752 14.341 31.944 14.387 ;
     RECT  40.08 12.227 42.168 14.435 ;
     RECT  23.52 12.803 24.312 14.437 ;
     RECT  28.752 14.387 30.84 14.483 ;
     RECT  26.784 14.341 26.952 14.533 ;
     RECT  51 12.659 51.528 14.533 ;
     RECT  11.52 14.197 17.256 14.627 ;
     RECT  20.928 13.475 20.952 14.629 ;
     RECT  22.176 14.101 22.488 14.629 ;
     RECT  37.92 13.235 38.952 14.629 ;
     RECT  34.368 14.197 36.888 14.677 ;
     RECT  37.872 14.629 38.952 14.677 ;
     RECT  10.08 14.389 10.104 14.773 ;
     RECT  11.52 14.627 15.336 14.773 ;
     RECT  56.4 12.803 56.808 14.773 ;
     RECT  57.888 12.803 57.912 14.773 ;
     RECT  22.08 14.629 22.488 14.819 ;
     RECT  23.52 14.437 24.552 14.821 ;
     RECT  23.52 14.821 24.696 14.869 ;
     RECT  28.752 14.483 30.744 14.915 ;
     RECT  34.368 14.677 38.952 14.915 ;
     RECT  40.2 14.435 42.168 14.915 ;
     RECT  72.48 13.091 72.912 14.915 ;
     RECT  26.496 14.533 26.952 14.917 ;
     RECT  16.464 14.627 17.256 15.061 ;
     RECT  18.6 13.523 18.912 15.061 ;
     RECT  22.704 14.869 24.696 15.251 ;
     RECT  56.4 14.773 57.912 15.251 ;
     RECT  72.6 14.915 72.912 15.301 ;
     RECT  5.856 13.907 8.424 15.349 ;
     RECT  44.064 11.603 44.088 15.349 ;
     RECT  22.704 15.251 24.456 15.395 ;
     RECT  57.888 15.251 57.912 15.397 ;
     RECT  23.52 15.395 24.456 15.443 ;
     RECT  26.112 14.917 26.952 15.443 ;
     RECT  57.888 15.397 58.152 15.443 ;
     RECT  16.464 15.061 18.912 15.491 ;
     RECT  10.08 14.773 15.336 15.539 ;
     RECT  31.92 14.387 31.944 15.635 ;
     RECT  34.368 14.915 35.256 15.683 ;
     RECT  59.424 15.541 59.448 15.683 ;
     RECT  50.112 14.533 51.528 15.731 ;
     RECT  5.664 15.349 8.424 15.733 ;
     RECT  3.744 13.045 4.152 15.779 ;
     RECT  20.736 14.629 20.952 15.781 ;
     RECT  53.28 14.243 54.552 15.781 ;
     RECT  61.536 13.045 62.112 15.781 ;
     RECT  45.6 14.195 46.008 15.829 ;
     RECT  17.952 15.491 18.912 15.875 ;
     RECT  61.008 15.781 62.112 15.923 ;
     RECT  40.2 14.915 40.968 15.925 ;
     RECT  42.192 14.917 42.312 15.925 ;
     RECT  26.112 15.443 26.808 15.971 ;
     RECT  53.28 15.781 55.272 15.971 ;
     RECT  37.872 14.915 38.952 15.973 ;
     RECT  40.2 15.925 42.312 15.973 ;
     RECT  4.128 15.779 4.152 16.019 ;
     RECT  5.664 15.733 8.568 16.019 ;
     RECT  10.08 15.539 10.728 16.019 ;
     RECT  16.464 15.491 16.488 16.019 ;
     RECT  37.872 15.973 42.648 16.019 ;
     RECT  72.6 15.301 73.272 16.019 ;
     RECT  50.16 15.731 51.528 16.021 ;
     RECT  11.952 15.539 15.336 16.067 ;
     RECT  11.952 16.067 11.976 16.115 ;
     RECT  39.264 16.019 42.648 16.115 ;
     RECT  36.24 14.915 36.888 16.117 ;
     RECT  37.872 16.019 38.184 16.117 ;
     RECT  50.16 16.021 51.672 16.163 ;
     RECT  39.264 16.115 42.216 16.211 ;
     RECT  10.704 16.019 10.728 16.259 ;
     RECT  36.24 16.117 38.184 16.307 ;
     RECT  45.6 15.829 46.728 16.307 ;
     RECT  68.64 16.021 68.664 16.307 ;
     RECT  34.512 15.683 35.256 16.405 ;
     RECT  36.24 16.307 36.408 16.405 ;
     RECT  58.128 15.443 58.152 16.501 ;
     RECT  26.112 15.971 26.52 16.549 ;
     RECT  29.088 14.915 30.744 16.549 ;
     RECT  48.144 14.051 48.168 16.595 ;
     RECT  29.088 16.549 31.416 16.691 ;
     RECT  33.072 16.549 33.096 16.739 ;
     RECT  53.328 15.971 55.272 16.787 ;
     RECT  44.064 15.349 44.28 16.789 ;
     RECT  45.6 16.307 46.152 16.789 ;
     RECT  39.408 16.211 42.216 16.835 ;
     RECT  44.064 16.789 46.152 16.883 ;
     RECT  18.6 15.875 18.912 16.885 ;
     RECT  56.4 15.251 56.712 16.933 ;
     RECT  44.064 16.883 46.056 16.979 ;
     RECT  6.288 16.019 8.568 17.027 ;
     RECT  67.2 13.333 67.608 17.029 ;
     RECT  74.688 16.453 74.712 17.029 ;
     RECT  37.872 16.307 38.184 17.075 ;
     RECT  23.52 15.443 24.312 17.077 ;
     RECT  25.488 16.549 26.52 17.077 ;
     RECT  61.8 15.923 62.112 17.077 ;
     RECT  13.056 16.067 15.336 17.123 ;
     RECT  64.992 16.885 65.016 17.123 ;
     RECT  68.928 16.885 68.952 17.123 ;
     RECT  34.512 16.405 36.408 17.171 ;
     RECT  41.616 16.835 42.216 17.171 ;
     RECT  58.128 16.501 59.064 17.171 ;
     RECT  15.12 17.123 15.336 17.219 ;
     RECT  20.736 15.781 21.288 17.219 ;
     RECT  22.848 17.077 26.52 17.219 ;
     RECT  53.568 16.787 55.272 17.315 ;
     RECT  6.288 17.027 8.52 17.317 ;
     RECT  5.712 17.317 8.52 17.363 ;
     RECT  29.088 16.691 31.32 17.363 ;
     RECT  5.712 17.363 8.112 17.459 ;
     RECT  34.512 17.171 36.072 17.459 ;
     RECT  74.688 17.029 75.144 17.459 ;
     RECT  25.488 17.219 26.52 17.461 ;
     RECT  23.52 17.219 24.312 17.555 ;
     RECT  37.056 17.317 37.08 17.555 ;
     RECT  13.056 17.123 13.944 17.605 ;
     RECT  78 11.941 78.408 17.605 ;
     RECT  44.064 16.979 46.008 17.651 ;
     RECT  25.488 17.461 26.808 17.843 ;
     RECT  53.568 17.315 54.792 17.843 ;
     RECT  38.064 17.075 38.184 17.891 ;
     RECT  40.08 16.835 40.512 17.891 ;
     RECT  12.528 17.605 13.944 17.939 ;
     RECT  20.736 17.219 20.76 17.939 ;
     RECT  75.12 17.459 75.144 17.939 ;
     RECT  13.056 17.939 13.944 18.035 ;
     RECT  23.616 17.555 24.312 18.035 ;
     RECT  61.056 17.077 62.112 18.035 ;
     RECT  71.28 17.029 71.304 18.037 ;
     RECT  42.192 17.171 42.216 18.133 ;
     RECT  34.8 17.459 36.072 18.181 ;
     RECT  44.064 17.651 45.912 18.181 ;
     RECT  61.8 18.035 62.112 18.181 ;
     RECT  29.088 17.363 29.832 18.227 ;
     RECT  33.024 17.365 33.048 18.227 ;
     RECT  67.2 17.029 67.848 18.227 ;
     RECT  15.312 17.219 15.336 18.275 ;
     RECT  43.776 18.181 45.912 18.275 ;
     RECT  3.696 17.077 3.72 18.419 ;
     RECT  16.368 16.501 16.392 18.419 ;
     RECT  38.112 17.891 38.184 18.419 ;
     RECT  42.192 18.133 42.408 18.419 ;
     RECT  13.2 18.035 13.944 18.467 ;
     RECT  56.4 16.933 57.048 18.467 ;
     RECT  23.664 18.035 24.312 18.469 ;
     RECT  26.112 17.843 26.808 18.515 ;
     RECT  34.8 18.181 36.456 18.563 ;
     RECT  47.424 17.413 47.448 18.611 ;
     RECT  29.088 18.227 29.712 18.707 ;
     RECT  53.568 17.843 54.552 18.707 ;
     RECT  40.2 17.891 40.512 18.709 ;
     RECT  42.192 18.419 42.216 18.709 ;
     RECT  78 17.605 78.456 18.709 ;
     RECT  23.664 18.469 24.408 18.755 ;
     RECT  5.712 17.459 5.736 18.803 ;
     RECT  40.2 18.709 42.216 18.851 ;
     RECT  67.2 18.227 67.608 18.851 ;
     RECT  70.656 18.037 71.304 18.851 ;
     RECT  38.112 18.419 38.136 18.899 ;
     RECT  72.6 16.019 72.912 18.949 ;
     RECT  50.16 16.163 51.48 18.995 ;
     RECT  18.6 16.885 19.032 19.045 ;
     RECT  70.656 18.851 70.68 19.091 ;
     RECT  50.688 18.995 51.48 19.237 ;
     RECT  18.6 19.045 19.848 19.331 ;
     RECT  34.8 18.563 36.168 19.333 ;
     RECT  61.8 18.181 63.096 19.333 ;
     RECT  61.8 19.333 63.24 19.379 ;
     RECT  50.688 19.237 52.248 19.475 ;
     RECT  24 18.755 24.408 19.477 ;
     RECT  40.2 18.851 41.304 19.477 ;
     RECT  39.552 19.477 41.304 19.619 ;
     RECT  72.6 18.949 73.512 19.621 ;
     RECT  63.216 19.379 63.24 19.669 ;
     RECT  10.8 18.133 10.824 19.811 ;
     RECT  26.112 18.515 26.136 19.811 ;
     RECT  31.296 17.363 31.32 19.811 ;
     RECT  18.6 19.331 18.912 19.813 ;
     RECT  13.2 18.467 13.512 19.909 ;
     RECT  14.496 18.757 14.52 19.909 ;
     RECT  17.616 19.813 18.912 19.909 ;
     RECT  13.2 19.909 14.52 19.955 ;
     RECT  17.184 19.909 18.912 19.955 ;
     RECT  34.224 19.333 36.168 20.003 ;
     RECT  43.776 18.275 43.8 20.003 ;
     RECT  78 18.709 78.648 20.051 ;
     RECT  53.568 18.707 53.592 20.149 ;
     RECT  38.16 19.909 38.184 20.195 ;
     RECT  50.784 19.475 52.248 20.195 ;
     RECT  2.4 13.043 2.712 20.197 ;
     RECT  56.4 18.467 56.712 20.197 ;
     RECT  40.2 19.619 41.304 20.291 ;
     RECT  50.784 20.195 51.312 20.291 ;
     RECT  76.8 11.699 76.824 20.389 ;
     RECT  78 20.051 78.312 20.389 ;
     RECT  53.52 20.149 53.592 20.435 ;
     RECT  13.2 19.955 14.28 20.579 ;
     RECT  24 19.477 25.128 20.581 ;
     RECT  24 20.581 26.04 20.723 ;
     RECT  64.896 20.581 64.92 20.723 ;
     RECT  74.928 19.621 74.952 20.819 ;
     RECT  18.48 19.955 18.912 20.915 ;
     RECT  63.216 19.669 63.288 20.965 ;
     RECT  17.184 19.955 17.208 21.013 ;
     RECT  17.088 21.013 17.208 21.059 ;
     RECT  2.4 20.197 2.856 21.155 ;
     RECT  17.088 21.059 17.112 21.155 ;
     RECT  36.144 20.003 36.168 21.155 ;
     RECT  71.712 19.621 73.512 21.155 ;
     RECT  60.432 18.805 60.456 21.205 ;
     RECT  53.52 20.435 53.544 21.251 ;
     RECT  40.2 20.291 40.632 21.347 ;
     RECT  60.432 21.205 60.648 21.443 ;
     RECT  55.152 19.477 55.176 21.493 ;
     RECT  56.4 20.197 57.432 21.493 ;
     RECT  21.984 18.181 22.008 21.637 ;
     RECT  18.6 20.915 18.912 21.685 ;
     RECT  29.4 18.707 29.712 21.733 ;
     RECT  26.64 21.493 26.808 21.779 ;
     RECT  49.344 21.637 49.368 21.779 ;
     RECT  63.216 20.965 63.48 21.779 ;
     RECT  69.792 20.869 69.816 21.779 ;
     RECT  76.8 20.389 78.312 21.779 ;
     RECT  26.784 21.779 26.808 21.923 ;
     RECT  7.104 17.459 8.112 22.165 ;
     RECT  21.36 21.637 22.008 22.165 ;
     RECT  34.224 20.003 35.112 22.211 ;
     RECT  44.976 18.275 45.912 22.309 ;
     RECT  72.6 21.155 73.512 22.309 ;
     RECT  64.704 21.397 64.728 22.355 ;
     RECT  2.4 21.155 2.712 22.645 ;
     RECT  44.976 22.309 46.104 22.739 ;
     RECT  60.384 21.829 60.408 22.787 ;
     RECT  34.464 22.211 35.112 22.789 ;
     RECT  12.144 22.165 12.168 22.835 ;
     RECT  21.36 22.165 22.728 22.883 ;
     RECT  34.464 22.789 35.304 22.979 ;
     RECT  18.6 21.685 19.848 23.075 ;
     RECT  28.848 21.733 29.712 23.125 ;
     RECT  27.36 22.165 27.384 23.171 ;
     RECT  9.6 18.709 9.624 23.269 ;
     RECT  21.984 22.883 22.728 23.315 ;
     RECT  54.144 21.781 54.168 23.315 ;
     RECT  71.664 22.309 73.512 23.315 ;
     RECT  34.464 22.979 35.112 23.363 ;
     RECT  72.6 23.315 73.512 23.365 ;
     RECT  2.4 22.645 3.432 23.555 ;
     RECT  28.464 23.125 29.712 23.555 ;
     RECT  6.864 22.165 8.112 23.795 ;
     RECT  63.216 21.779 63.24 23.795 ;
     RECT  24 20.723 25.128 23.797 ;
     RECT  24 23.797 25.56 23.843 ;
     RECT  72.6 23.365 73.896 24.083 ;
     RECT  48.336 23.173 48.36 24.371 ;
     RECT  69.552 22.981 69.576 24.371 ;
     RECT  7.104 23.795 8.112 24.469 ;
     RECT  9.6 23.269 10.536 24.469 ;
     RECT  7.104 24.469 10.536 24.515 ;
     RECT  42.672 23.029 43.512 24.515 ;
     RECT  44.976 22.739 45.912 24.517 ;
     RECT  29.4 23.555 29.712 24.613 ;
     RECT  32.544 23.797 32.568 24.659 ;
     RECT  44.88 24.517 45.912 24.659 ;
     RECT  18.6 23.075 18.912 24.709 ;
     RECT  45.6 24.659 45.912 24.709 ;
     RECT  47.088 24.661 47.112 24.709 ;
     RECT  29.4 24.613 29.832 24.757 ;
     RECT  30.816 23.413 30.84 24.757 ;
     RECT  69.648 24.661 69.672 24.803 ;
     RECT  55.152 21.493 57.432 24.851 ;
     RECT  51 20.291 51.312 24.853 ;
     RECT  45.6 24.709 47.112 24.995 ;
     RECT  24 23.843 24.408 24.997 ;
     RECT  25.536 23.843 25.56 24.997 ;
     RECT  40.2 21.347 40.512 24.997 ;
     RECT  2.4 23.555 2.712 25.045 ;
     RECT  34.704 23.363 35.112 25.093 ;
     RECT  78 21.779 78.312 25.093 ;
     RECT  39.888 24.997 40.512 25.187 ;
     RECT  75.552 24.037 75.576 25.187 ;
     RECT  43.392 24.515 43.512 25.235 ;
     RECT  21.984 23.315 22.008 25.285 ;
     RECT  67.2 18.851 67.512 25.333 ;
     RECT  14.784 25.381 14.808 25.429 ;
     RECT  2.4 25.045 2.856 25.475 ;
     RECT  27.888 24.133 27.912 25.475 ;
     RECT  78 25.093 78.408 25.475 ;
     RECT  34.56 25.093 35.112 25.523 ;
     RECT  14.592 25.429 14.808 25.571 ;
     RECT  34.704 25.523 35.112 25.571 ;
     RECT  29.4 24.757 30.84 25.667 ;
     RECT  17.232 22.405 17.256 25.715 ;
     RECT  18.6 24.709 19.08 25.715 ;
     RECT  29.4 25.667 29.976 25.717 ;
     RECT  45.6 24.995 46.152 25.763 ;
     RECT  44.592 25.669 44.616 25.859 ;
     RECT  7.104 24.515 9.624 26.003 ;
     RECT  45.6 25.763 45.912 26.101 ;
     RECT  61.8 19.379 62.112 26.197 ;
     RECT  14.592 25.571 14.616 26.243 ;
     RECT  24 24.997 25.56 26.243 ;
     RECT  29.088 25.717 29.976 26.243 ;
     RECT  65.952 25.285 65.976 26.243 ;
     RECT  67.2 25.333 68.424 26.243 ;
     RECT  71.28 23.701 71.304 26.243 ;
     RECT  7.392 26.003 9.624 26.291 ;
     RECT  45.504 26.101 45.912 26.339 ;
     RECT  76.8 21.779 76.824 26.389 ;
     RECT  37.056 26.293 37.08 26.435 ;
     RECT  72.6 24.083 73.512 26.483 ;
     RECT  25.536 26.243 25.56 26.531 ;
     RECT  33.6 25.669 33.624 26.533 ;
     RECT  33.168 26.533 33.624 26.675 ;
     RECT  4.416 25.381 4.44 26.723 ;
     RECT  64.08 24.469 64.104 26.771 ;
     RECT  50.064 24.853 51.312 26.773 ;
     RECT  78 25.475 78.312 26.773 ;
     RECT  61.008 26.197 62.112 26.819 ;
     RECT  34.8 25.571 35.112 26.821 ;
     RECT  49.824 26.773 51.312 26.821 ;
     RECT  43.488 25.235 43.512 26.867 ;
     RECT  21.024 25.285 22.008 27.059 ;
     RECT  72.6 26.483 72.912 27.061 ;
     RECT  55.296 24.851 57.432 27.299 ;
     RECT  7.8 26.291 9.624 27.347 ;
     RECT  29.4 26.243 29.976 27.395 ;
     RECT  33.6 26.675 33.624 27.395 ;
     RECT  78 26.773 78.504 27.539 ;
     RECT  29.4 27.395 29.928 27.541 ;
     RECT  52.992 26.101 53.016 27.635 ;
     RECT  72 27.061 72.912 27.635 ;
     RECT  26.928 27.109 26.952 27.637 ;
     RECT  29.28 27.541 29.928 27.683 ;
     RECT  13.2 20.579 13.512 27.685 ;
     RECT  26.88 27.637 26.952 27.685 ;
     RECT  76.8 26.389 76.872 27.875 ;
     RECT  49.248 26.821 51.312 27.973 ;
     RECT  34.656 26.821 35.112 28.117 ;
     RECT  31.104 26.677 31.128 28.211 ;
     RECT  33.504 28.069 33.528 28.259 ;
     RECT  61.8 26.819 62.112 28.405 ;
     RECT  21.888 27.059 22.008 28.453 ;
     RECT  45.6 26.339 45.912 28.453 ;
     RECT  48.816 27.973 51.312 28.453 ;
     RECT  21.888 28.453 22.056 28.499 ;
     RECT  34.656 28.117 35.304 28.547 ;
     RECT  24 26.243 24.312 28.597 ;
     RECT  29.4 27.683 29.928 28.597 ;
     RECT  61.8 28.405 62.616 28.739 ;
     RECT  42.24 26.725 42.264 28.885 ;
     RECT  47.904 28.453 51.312 28.885 ;
     RECT  55.68 27.299 57.432 28.981 ;
     RECT  59.04 17.171 59.064 28.981 ;
     RECT  34.656 28.547 35.112 29.027 ;
     RECT  7.8 27.347 8.112 29.029 ;
     RECT  40.2 25.187 40.512 29.077 ;
     RECT  42.192 28.885 42.264 29.123 ;
     RECT  29.4 28.597 30.024 29.171 ;
     RECT  26.496 27.685 26.952 29.219 ;
     RECT  39.888 29.077 40.512 29.315 ;
     RECT  21.936 28.499 22.056 29.509 ;
     RECT  55.68 28.981 59.064 29.651 ;
     RECT  60.288 28.693 60.312 29.699 ;
     RECT  44.352 28.453 44.376 29.747 ;
     RECT  7.8 29.029 8.376 29.795 ;
     RECT  47.808 28.885 51.312 29.797 ;
     RECT  13.2 27.685 13.752 29.845 ;
     RECT  13.104 29.845 13.752 29.891 ;
     RECT  75.648 29.029 75.672 29.987 ;
     RECT  13.104 29.891 13.512 30.037 ;
     RECT  68.784 29.365 68.808 30.275 ;
     RECT  6.24 29.077 6.264 30.323 ;
     RECT  47.28 29.797 51.312 30.421 ;
     RECT  36.864 29.509 36.888 30.467 ;
     RECT  55.68 29.651 57.624 30.467 ;
     RECT  34.8 29.027 35.112 30.517 ;
     RECT  70.8 30.181 70.824 30.565 ;
     RECT  29.4 29.171 29.928 30.613 ;
     RECT  40.2 29.315 40.512 30.661 ;
     RECT  34.8 30.517 35.208 30.707 ;
     RECT  47.04 30.421 51.312 30.707 ;
     RECT  45.504 28.453 45.912 30.757 ;
     RECT  61.8 28.739 62.112 30.757 ;
     RECT  21.936 29.509 22.2 30.805 ;
     RECT  76.8 27.875 76.824 30.805 ;
     RECT  3.984 29.749 4.008 30.851 ;
     RECT  26.928 29.219 26.952 30.899 ;
     RECT  34.8 30.707 35.112 30.949 ;
     RECT  10.8 29.077 10.824 31.091 ;
     RECT  7.8 29.795 8.112 31.093 ;
     RECT  24 28.597 24.456 31.139 ;
     RECT  18.6 25.715 18.912 31.237 ;
     RECT  40.2 30.661 41.016 31.285 ;
     RECT  70.704 30.565 70.824 31.331 ;
     RECT  47.904 30.707 51.312 31.379 ;
     RECT  52.848 30.757 52.872 31.379 ;
     RECT  2.4 25.475 2.712 31.525 ;
     RECT  78 27.539 78.312 31.525 ;
     RECT  76.8 30.805 76.92 31.571 ;
     RECT  12.624 30.037 13.512 31.619 ;
     RECT  42.192 29.123 42.216 31.619 ;
     RECT  40.2 31.285 41.112 31.717 ;
     RECT  45.504 30.757 46.152 31.907 ;
     RECT  34.032 30.949 35.112 31.955 ;
     RECT  25.536 30.037 25.56 31.957 ;
     RECT  55.68 30.467 57.432 31.957 ;
     RECT  45.6 31.907 46.152 32.005 ;
     RECT  43.152 31.669 43.176 32.051 ;
     RECT  78 31.525 78.456 32.051 ;
     RECT  45.6 32.005 46.68 32.147 ;
     RECT  32.496 32.101 32.52 32.149 ;
     RECT  61.248 30.757 62.112 32.197 ;
     RECT  2.4 31.525 3.192 32.339 ;
     RECT  61.104 32.197 62.112 32.339 ;
     RECT  6.864 31.093 8.112 32.341 ;
     RECT  21.936 30.805 22.92 32.341 ;
     RECT  31.536 32.149 32.52 32.387 ;
     RECT  21.408 32.341 22.92 32.435 ;
     RECT  51 31.379 51.312 32.437 ;
     RECT  32.496 32.387 32.52 32.483 ;
     RECT  55.248 31.957 57.432 32.485 ;
     RECT  67.2 26.243 67.512 32.485 ;
     RECT  6.816 32.341 8.112 32.677 ;
     RECT  39.36 31.717 41.112 32.677 ;
     RECT  6 32.677 8.112 32.773 ;
     RECT  18.6 31.237 19.512 32.773 ;
     RECT  25.536 31.957 25.896 32.867 ;
     RECT  39.36 32.677 41.304 32.867 ;
     RECT  45.6 32.147 46.44 32.869 ;
     RECT  34.8 31.955 35.112 32.917 ;
     RECT  55.2 32.485 57.432 32.963 ;
     RECT  12.672 31.619 13.512 32.965 ;
     RECT  34.8 32.917 35.304 33.013 ;
     RECT  70.704 31.331 70.728 33.013 ;
     RECT  28.08 32.437 28.104 33.061 ;
     RECT  27.36 33.061 28.104 33.107 ;
     RECT  67.2 32.485 68.424 33.155 ;
     RECT  69.984 33.013 70.728 33.203 ;
     RECT  12.528 32.965 13.512 33.397 ;
     RECT  18.6 32.773 19.752 33.445 ;
     RECT  9.6 27.347 9.624 33.589 ;
     RECT  61.8 32.339 62.112 33.589 ;
     RECT  39.36 32.867 40.512 33.635 ;
     RECT  34.464 33.013 35.304 33.637 ;
     RECT  36.528 32.341 36.552 33.637 ;
     RECT  12.528 33.397 14.136 33.683 ;
     RECT  75.216 32.485 75.24 33.733 ;
     RECT  74.688 33.733 75.24 33.779 ;
     RECT  6 32.773 8.232 33.827 ;
     RECT  34.464 33.637 36.552 33.827 ;
     RECT  44.016 33.541 44.04 33.829 ;
     RECT  45.456 32.869 46.44 33.829 ;
     RECT  34.464 33.827 36.12 33.875 ;
     RECT  34.704 33.875 36.12 33.971 ;
     RECT  44.016 33.829 46.44 34.115 ;
     RECT  17.616 33.445 19.752 34.117 ;
     RECT  12.672 33.683 14.136 34.163 ;
     RECT  17.136 34.117 19.752 34.163 ;
     RECT  2.4 32.339 2.712 34.165 ;
     RECT  70.704 33.203 70.728 34.213 ;
     RECT  21.408 32.435 21.96 34.259 ;
     RECT  44.016 34.115 44.04 34.259 ;
     RECT  47.904 31.379 49.272 34.259 ;
     RECT  2.4 34.165 2.904 34.307 ;
     RECT  50.88 32.437 51.312 34.309 ;
     RECT  61.8 33.589 62.952 34.355 ;
     RECT  45.6 34.115 46.44 34.405 ;
     RECT  50.112 34.309 51.312 34.451 ;
     RECT  9.6 33.589 9.864 34.501 ;
     RECT  32.4 34.405 32.424 34.547 ;
     RECT  45.6 34.405 46.872 34.547 ;
     RECT  27.36 33.107 27.384 34.597 ;
     RECT  61.8 34.355 62.112 34.645 ;
     RECT  6 33.827 8.112 34.741 ;
     RECT  9.6 34.501 10.824 34.741 ;
     RECT  40.2 33.635 40.512 34.741 ;
     RECT  5.664 34.741 8.112 34.787 ;
     RECT  29.136 30.613 29.928 34.835 ;
     RECT  45.6 34.547 46.44 34.883 ;
     RECT  74.688 33.779 74.712 34.931 ;
     RECT  70.704 34.213 71.448 34.979 ;
     RECT  34.704 33.971 36.072 35.123 ;
     RECT  71.184 34.979 71.448 35.171 ;
     RECT  55.248 32.963 57.432 35.221 ;
     RECT  7.8 34.787 8.112 35.317 ;
     RECT  5.664 34.787 6.024 35.363 ;
     RECT  17.136 34.163 17.16 35.363 ;
     RECT  27.36 34.597 27.528 35.363 ;
     RECT  27.408 35.363 27.528 35.413 ;
     RECT  55.248 35.221 57.864 35.461 ;
     RECT  59.04 29.651 59.064 35.461 ;
     RECT  64.416 30.757 64.44 35.509 ;
     RECT  9.6 34.741 10.872 35.699 ;
     RECT  72.6 27.635 72.912 35.701 ;
     RECT  10.8 35.699 10.872 35.747 ;
     RECT  55.248 35.461 59.064 35.843 ;
     RECT  12.672 34.163 13.512 35.845 ;
     RECT  34.704 35.123 35.88 35.845 ;
     RECT  10.848 35.747 10.872 35.939 ;
     RECT  39.552 34.741 40.512 35.941 ;
     RECT  55.248 35.843 57.864 35.941 ;
     RECT  31.296 35.845 31.32 35.987 ;
     RECT  7.8 35.317 8.376 36.275 ;
     RECT  61.056 34.645 62.112 36.275 ;
     RECT  64.416 35.509 64.632 36.323 ;
     RECT  34.464 35.845 35.88 36.371 ;
     RECT  16.272 35.605 16.296 36.373 ;
     RECT  39.552 35.941 40.92 36.373 ;
     RECT  27.408 35.413 27.72 36.467 ;
     RECT  44.304 36.325 44.328 36.467 ;
     RECT  42 35.557 42.024 36.469 ;
     RECT  22.992 35.269 23.016 36.515 ;
     RECT  39.456 36.373 40.92 36.515 ;
     RECT  65.664 35.413 65.688 36.515 ;
     RECT  67.2 33.155 67.512 36.517 ;
     RECT  27.696 36.467 27.72 36.661 ;
     RECT  45.6 34.883 46.008 36.661 ;
     RECT  30.768 36.757 30.792 36.949 ;
     RECT  37.008 36.469 37.032 36.949 ;
     RECT  67.2 36.517 67.608 36.949 ;
     RECT  71.184 35.171 71.208 36.949 ;
     RECT  36.864 36.949 37.032 36.995 ;
     RECT  66.72 36.949 67.608 36.995 ;
     RECT  12.672 35.845 13.608 36.997 ;
     RECT  39.456 36.515 40.512 36.997 ;
     RECT  54.528 35.941 57.864 36.997 ;
     RECT  59.04 35.843 59.064 36.997 ;
     RECT  30.768 36.949 31.08 37.043 ;
     RECT  29.136 34.835 29.712 37.045 ;
     RECT  54.528 36.997 59.064 37.091 ;
     RECT  29.088 37.045 29.712 37.093 ;
     RECT  16.272 36.373 17.208 37.139 ;
     RECT  12.672 36.997 14.088 37.283 ;
     RECT  38.64 36.997 40.512 37.283 ;
     RECT  38.64 37.283 38.664 37.331 ;
     RECT  7.8 36.275 8.112 37.429 ;
     RECT  9.6 35.699 9.624 37.429 ;
     RECT  18.6 34.163 19.752 37.429 ;
     RECT  21.936 34.259 21.96 37.429 ;
     RECT  13.2 37.283 14.088 37.523 ;
     RECT  42 36.469 42.6 37.523 ;
     RECT  51 34.451 51.312 37.573 ;
     RECT  36.864 36.995 36.888 37.667 ;
     RECT  27.696 36.661 27.912 37.861 ;
     RECT  25.536 32.867 25.56 37.909 ;
     RECT  25.536 37.909 26.184 37.955 ;
     RECT  31.056 37.043 31.08 37.955 ;
     RECT  34.8 36.371 35.88 38.003 ;
     RECT  53.04 36.661 53.064 38.051 ;
     RECT  2.4 34.307 2.712 38.053 ;
     RECT  55.248 37.091 59.064 38.099 ;
     RECT  24 31.139 24.312 38.101 ;
     RECT  27.648 37.861 27.912 38.101 ;
     RECT  28.992 37.093 29.712 38.101 ;
     RECT  39.888 37.283 40.512 38.101 ;
     RECT  42 37.523 42.024 38.101 ;
     RECT  20.976 37.429 21.96 38.147 ;
     RECT  11.424 36.277 11.448 38.149 ;
     RECT  2.4 38.053 3 38.195 ;
     RECT  70.56 36.949 71.208 38.245 ;
     RECT  21.024 38.147 21.96 38.291 ;
     RECT  45.6 36.661 46.104 38.339 ;
     RECT  7.8 37.429 9.624 38.387 ;
     RECT  55.248 38.099 57.864 38.389 ;
     RECT  66.72 36.995 67.512 38.389 ;
     RECT  61.248 36.275 62.112 38.435 ;
     RECT  50.88 37.573 51.312 38.437 ;
     RECT  23.328 38.101 24.312 38.533 ;
     RECT  43.152 38.437 43.176 38.579 ;
     RECT  18.48 37.429 19.752 38.629 ;
     RECT  39.888 38.101 42.024 38.677 ;
     RECT  47.904 34.259 48.84 38.677 ;
     RECT  65.904 38.389 67.512 38.677 ;
     RECT  23.328 38.533 24.408 38.723 ;
     RECT  64.416 36.323 64.44 38.723 ;
     RECT  70.56 38.245 71.4 38.723 ;
     RECT  18.24 38.629 19.752 38.773 ;
     RECT  39.888 38.677 42.408 38.819 ;
     RECT  50.88 38.437 51.432 38.819 ;
     RECT  65.904 38.677 67.608 38.819 ;
     RECT  75.408 38.005 75.432 38.819 ;
     RECT  70.56 38.723 71.256 38.915 ;
     RECT  52.56 38.725 52.584 38.963 ;
     RECT  13.2 37.523 13.704 39.059 ;
     RECT  27.648 38.101 29.712 39.059 ;
     RECT  23.328 38.723 24.312 39.203 ;
     RECT  16.272 37.139 16.296 39.205 ;
     RECT  11.424 38.149 12.216 39.251 ;
     RECT  66.72 38.819 67.608 39.251 ;
     RECT  71.232 38.915 71.256 39.251 ;
     RECT  67.2 39.251 67.608 39.253 ;
     RECT  36.72 38.101 36.744 39.299 ;
     RECT  72.6 35.701 73.224 39.301 ;
     RECT  34.8 38.003 35.112 39.589 ;
     RECT  18.24 38.773 19.992 39.685 ;
     RECT  45.6 38.339 46.056 39.685 ;
     RECT  47.664 38.677 48.84 39.685 ;
     RECT  40.032 38.819 42.408 39.731 ;
     RECT  16.272 39.205 16.872 39.733 ;
     RECT  15.024 39.253 15.048 39.779 ;
     RECT  42.144 39.731 42.408 39.779 ;
     RECT  32.736 39.637 32.76 39.781 ;
     RECT  25.68 37.955 26.184 39.827 ;
     RECT  40.032 39.731 40.512 39.827 ;
     RECT  9.6 38.387 9.624 39.877 ;
     RECT  51 38.819 51.432 39.877 ;
     RECT  54.912 38.389 57.864 39.923 ;
     RECT  4.848 38.821 4.872 40.019 ;
     RECT  21.504 38.291 21.96 40.019 ;
     RECT  43.872 39.301 43.896 40.117 ;
     RECT  31.776 39.781 32.76 40.211 ;
     RECT  65.136 39.205 65.16 40.259 ;
     RECT  43.872 40.117 44.04 40.355 ;
     RECT  27.696 39.059 29.712 40.453 ;
     RECT  2.4 38.195 2.904 40.499 ;
     RECT  6 35.363 6.024 40.499 ;
     RECT  21.936 40.019 21.96 40.499 ;
     RECT  75.744 39.589 75.768 40.499 ;
     RECT  17.856 39.685 19.992 40.547 ;
     RECT  51 39.877 51.912 40.547 ;
     RECT  72.48 39.301 73.224 40.547 ;
     RECT  9.168 39.877 9.624 40.549 ;
     RECT  34.8 39.589 35.832 40.595 ;
     RECT  42.144 39.779 42.168 40.595 ;
     RECT  43.872 40.355 43.896 40.595 ;
     RECT  67.2 39.253 67.8 40.595 ;
     RECT  24 39.203 24.312 40.597 ;
     RECT  53.424 39.637 53.448 40.643 ;
     RECT  24 40.597 24.408 40.741 ;
     RECT  45.6 39.685 48.84 40.787 ;
     RECT  24 40.741 25.128 40.883 ;
     RECT  45.6 40.787 46.824 41.027 ;
     RECT  34.8 40.595 35.112 41.029 ;
     RECT  45.6 41.027 46.728 41.075 ;
     RECT  55.68 39.923 57.864 41.269 ;
     RECT  52.848 41.221 53.064 41.411 ;
     RECT  9.168 40.549 9.864 41.413 ;
     RECT  40.2 39.827 40.512 41.461 ;
     RECT  59.04 38.099 59.064 41.509 ;
     RECT  53.04 41.411 53.064 41.603 ;
     RECT  39.984 41.461 40.512 41.605 ;
     RECT  51 40.547 51.432 41.605 ;
     RECT  16.032 39.733 16.872 41.651 ;
     RECT  26.16 39.827 26.184 41.651 ;
     RECT  27.36 40.453 29.712 41.651 ;
     RECT  59.04 41.509 59.4 41.651 ;
     RECT  39.984 41.605 40.632 41.699 ;
     RECT  9.12 41.413 9.864 41.701 ;
     RECT  72.6 40.547 73.224 41.749 ;
     RECT  33.648 41.557 33.672 41.845 ;
     RECT  34.656 41.029 35.112 41.845 ;
     RECT  40.2 41.699 40.632 41.891 ;
     RECT  21.12 41.797 21.144 41.987 ;
     RECT  76.8 31.571 76.824 41.989 ;
     RECT  78 32.051 78.312 41.989 ;
     RECT  33.648 41.845 35.112 42.179 ;
     RECT  45.6 41.075 45.912 42.181 ;
     RECT  33.648 42.179 33.672 42.227 ;
     RECT  68.64 41.413 68.664 42.227 ;
     RECT  7.8 38.387 8.112 42.229 ;
     RECT  9.12 41.701 10.728 42.229 ;
     RECT  59.376 41.651 59.4 42.469 ;
     RECT  5.808 41.173 5.832 42.517 ;
     RECT  55.296 41.269 57.864 42.563 ;
     RECT  5.472 42.517 6.552 42.709 ;
     RECT  7.8 42.229 10.824 42.709 ;
     RECT  12.192 39.251 12.216 42.709 ;
     RECT  13.2 39.059 13.512 42.709 ;
     RECT  27.696 41.651 29.712 42.709 ;
     RECT  31.872 41.605 31.896 42.755 ;
     RECT  59.376 42.469 59.832 42.803 ;
     RECT  51 41.605 51.672 42.805 ;
     RECT  76.032 41.989 76.824 42.899 ;
     RECT  63.168 42.757 63.192 42.947 ;
     RECT  21.12 42.949 21.144 42.997 ;
     RECT  78 41.989 78.408 43.043 ;
     RECT  34.704 42.179 35.112 43.045 ;
     RECT  45.6 42.181 46.008 43.093 ;
     RECT  21.12 42.997 21.24 43.139 ;
     RECT  2.4 40.499 2.712 43.141 ;
     RECT  45.024 43.093 46.008 43.141 ;
     RECT  34.704 43.045 35.4 43.187 ;
     RECT  44.16 43.141 46.008 43.235 ;
     RECT  47.904 40.787 48.84 43.237 ;
     RECT  51 42.805 52.632 43.283 ;
     RECT  67.2 40.595 67.608 43.285 ;
     RECT  16.848 41.651 16.872 43.331 ;
     RECT  34.704 43.187 35.256 43.331 ;
     RECT  44.16 43.235 45.912 43.331 ;
     RECT  59.808 42.803 59.832 43.333 ;
     RECT  12.192 42.709 13.512 43.379 ;
     RECT  59.808 43.333 60.408 43.379 ;
     RECT  74.4 42.757 74.424 43.379 ;
     RECT  13.2 43.379 13.512 43.669 ;
     RECT  32.496 43.285 32.52 43.765 ;
     RECT  5.28 42.709 10.824 43.813 ;
     RECT  67.2 43.285 67.8 43.861 ;
     RECT  32.496 43.765 33.192 43.907 ;
     RECT  5.28 43.813 10.92 43.955 ;
     RECT  27.6 42.709 29.712 43.955 ;
     RECT  72.384 41.749 73.224 43.955 ;
     RECT  32.496 43.907 33.096 44.003 ;
     RECT  60.384 43.379 60.408 44.099 ;
     RECT  44.16 43.331 44.328 44.245 ;
     RECT  70.656 42.997 70.68 44.339 ;
     RECT  13.2 43.669 13.944 44.387 ;
     RECT  16.56 43.861 16.584 44.389 ;
     RECT  51 43.283 52.104 44.435 ;
     RECT  76.608 42.899 76.824 44.437 ;
     RECT  32.496 44.003 32.76 44.483 ;
     RECT  66.672 43.861 67.8 44.483 ;
     RECT  21.216 43.139 21.24 44.531 ;
     RECT  22.8 43.861 22.824 44.627 ;
     RECT  5.472 43.955 10.92 44.629 ;
     RECT  12.192 43.379 12.216 44.629 ;
     RECT  44.016 44.245 44.328 44.629 ;
     RECT  45.6 43.331 45.912 44.629 ;
     RECT  17.856 40.547 19.848 44.675 ;
     RECT  5.472 44.629 12.216 44.725 ;
     RECT  13.2 44.387 13.512 44.725 ;
     RECT  15.12 43.045 15.144 44.725 ;
     RECT  44.016 44.629 45.912 44.869 ;
     RECT  76.608 44.437 76.968 44.869 ;
     RECT  78 43.043 78.312 44.869 ;
     RECT  40.2 41.891 40.512 44.917 ;
     RECT  43.248 44.869 46.008 44.917 ;
     RECT  27.6 43.955 27.624 44.965 ;
     RECT  14.64 44.725 15.144 45.011 ;
     RECT  76.608 44.869 78.312 45.013 ;
     RECT  43.056 44.917 46.008 45.059 ;
     RECT  32.736 44.483 32.76 45.155 ;
     RECT  59.232 44.101 59.256 45.155 ;
     RECT  76.608 45.013 78.456 45.155 ;
     RECT  44.16 45.059 46.008 45.157 ;
     RECT  15.12 45.011 15.144 45.203 ;
     RECT  29.04 43.955 29.712 45.205 ;
     RECT  39.888 44.917 40.512 45.253 ;
     RECT  78 45.155 78.456 45.299 ;
     RECT  27.456 44.965 27.624 45.301 ;
     RECT  5.472 44.725 13.512 45.397 ;
     RECT  61.8 38.435 62.112 45.493 ;
     RECT  63.6 43.189 63.72 45.493 ;
     RECT  27.456 45.301 28.008 45.539 ;
     RECT  55.68 42.563 57.864 45.541 ;
     RECT  61.8 45.493 63.72 45.541 ;
     RECT  44.16 45.157 46.344 45.587 ;
     RECT  2.4 43.141 3.144 45.635 ;
     RECT  60.24 44.965 60.264 45.635 ;
     RECT  72.384 43.955 72.912 45.635 ;
     RECT  5.424 45.397 13.512 45.637 ;
     RECT  39.888 45.253 40.872 45.685 ;
     RECT  70.128 45.013 70.152 45.685 ;
     RECT  34.8 43.331 35.256 45.731 ;
     RECT  72.48 45.635 72.912 45.731 ;
     RECT  67.2 44.483 67.8 45.733 ;
     RECT  25.776 44.725 25.8 45.781 ;
     RECT  16.464 44.389 16.584 45.829 ;
     RECT  29.04 45.205 29.928 45.923 ;
     RECT  61.8 45.541 63.816 46.067 ;
     RECT  51 44.435 51.912 46.069 ;
     RECT  67.008 45.733 67.8 46.069 ;
     RECT  54.576 45.973 54.6 46.115 ;
     RECT  16.416 45.829 16.584 46.117 ;
     RECT  31.248 44.917 31.272 46.163 ;
     RECT  47.904 43.237 49.608 46.163 ;
     RECT  15.648 46.117 16.584 46.211 ;
     RECT  44.16 45.587 46.056 46.211 ;
     RECT  48.816 46.163 49.608 46.211 ;
     RECT  29.136 45.923 29.928 46.213 ;
     RECT  5.04 45.637 13.512 46.259 ;
     RECT  18.6 44.675 19.848 46.309 ;
     RECT  39.456 45.685 40.872 46.309 ;
     RECT  18.6 46.309 20.472 46.405 ;
     RECT  51 46.069 51.96 46.453 ;
     RECT  61.8 46.067 62.616 46.453 ;
     RECT  14.64 46.357 14.664 46.499 ;
     RECT  22.848 44.965 22.872 46.499 ;
     RECT  39.456 46.309 41.208 46.499 ;
     RECT  12.528 46.259 13.512 46.549 ;
     RECT  70.08 45.685 70.152 46.549 ;
     RECT  50.112 46.453 51.96 46.595 ;
     RECT  61.584 46.453 62.616 46.595 ;
     RECT  15.648 46.211 16.44 46.643 ;
     RECT  50.688 46.595 51.96 46.643 ;
     RECT  61.584 46.595 62.52 46.643 ;
     RECT  5.04 46.259 11.064 46.787 ;
     RECT  15.648 46.643 16.392 46.787 ;
     RECT  29.136 46.213 30.504 46.787 ;
     RECT  42.72 46.309 42.744 46.787 ;
     RECT  60.288 45.733 60.312 46.787 ;
     RECT  64.992 45.541 65.016 46.787 ;
     RECT  68.976 43.285 69 46.787 ;
     RECT  45.168 46.211 46.056 46.883 ;
     RECT  34.8 45.731 35.208 46.885 ;
     RECT  45.6 46.883 46.056 46.933 ;
     RECT  55.68 45.541 57.912 47.029 ;
     RECT  25.776 45.781 26.424 47.075 ;
     RECT  63.6 46.067 63.816 47.075 ;
     RECT  53.04 47.077 53.064 47.219 ;
     RECT  34.8 46.885 35.688 47.221 ;
     RECT  54.288 46.213 54.312 47.221 ;
     RECT  55.68 47.029 58.008 47.221 ;
     RECT  61.584 46.643 62.112 47.315 ;
     RECT  44.16 46.211 44.184 47.317 ;
     RECT  6.768 46.787 11.064 47.363 ;
     RECT  18.6 46.405 21 47.363 ;
     RECT  75.168 46.645 75.192 47.363 ;
     RECT  54.288 47.221 58.008 47.459 ;
     RECT  43.344 47.317 44.184 47.507 ;
     RECT  34.8 47.221 35.88 47.603 ;
     RECT  45.6 46.933 46.104 47.651 ;
     RECT  34.8 47.603 35.688 47.699 ;
     RECT  40.2 46.499 41.208 47.699 ;
     RECT  66.672 46.069 67.8 47.699 ;
     RECT  3.936 47.125 3.96 47.701 ;
     RECT  5.04 46.787 5.496 47.701 ;
     RECT  3.936 47.701 5.496 47.749 ;
     RECT  6.768 47.363 6.792 47.749 ;
     RECT  40.2 47.699 40.512 47.749 ;
     RECT  29.136 46.787 30.264 47.845 ;
     RECT  39.36 47.749 40.512 47.845 ;
     RECT  72.6 45.731 72.912 47.845 ;
     RECT  24 40.883 24.312 47.893 ;
     RECT  12.528 46.549 13.608 47.939 ;
     RECT  51 46.643 51.96 47.989 ;
     RECT  23.904 47.893 24.312 48.035 ;
     RECT  2.4 45.635 2.712 48.229 ;
     RECT  3.936 47.749 6.792 48.229 ;
     RECT  7.8 47.363 11.064 48.229 ;
     RECT  26.4 47.075 26.424 48.325 ;
     RECT  27.456 45.539 27.48 48.325 ;
     RECT  22.608 47.605 22.632 48.371 ;
     RECT  12.528 47.939 13.512 48.419 ;
     RECT  26.4 48.325 27.48 48.421 ;
     RECT  66.672 47.699 67.608 48.421 ;
     RECT  39.264 47.845 40.512 48.467 ;
     RECT  26.352 48.421 27.48 48.469 ;
     RECT  50.88 47.989 51.96 48.515 ;
     RECT  66.144 48.421 67.608 48.515 ;
     RECT  18.6 47.363 20.472 48.565 ;
     RECT  18.6 48.565 20.52 48.659 ;
     RECT  26.352 48.469 27.96 48.659 ;
     RECT  71.808 47.845 72.912 48.659 ;
     RECT  45.6 47.651 46.008 48.661 ;
     RECT  48.816 46.211 48.84 48.661 ;
     RECT  34.8 47.699 35.112 48.757 ;
     RECT  7.8 48.229 11.304 48.805 ;
     RECT  39.84 48.467 40.512 48.805 ;
     RECT  43.824 47.507 44.184 48.805 ;
     RECT  45.456 48.661 46.008 48.805 ;
     RECT  70.08 46.549 70.68 48.805 ;
     RECT  43.824 48.805 46.008 48.899 ;
     RECT  29.088 47.845 30.264 48.901 ;
     RECT  69.552 48.805 70.68 48.947 ;
     RECT  28.992 48.901 30.264 48.949 ;
     RECT  51 48.515 51.96 48.949 ;
     RECT  53.04 48.853 53.064 48.949 ;
     RECT  76.608 45.155 76.824 48.949 ;
     RECT  51 48.949 53.688 48.995 ;
     RECT  61.8 47.315 62.112 48.997 ;
     RECT  39.84 48.805 41.304 49.043 ;
     RECT  52.416 48.995 53.688 49.043 ;
     RECT  59.808 47.845 59.832 49.043 ;
     RECT  70.656 48.947 70.68 49.043 ;
     RECT  61.488 48.997 62.112 49.045 ;
     RECT  47.184 48.421 47.208 49.093 ;
     RECT  24 48.035 24.312 49.141 ;
     RECT  28.992 48.949 31.224 49.141 ;
     RECT  33.072 49.045 33.096 49.187 ;
     RECT  28.464 49.141 31.224 49.189 ;
     RECT  44.16 48.899 46.008 49.235 ;
     RECT  54.72 47.459 58.008 49.285 ;
     RECT  63.792 47.075 63.816 49.285 ;
     RECT  32.784 49.189 32.808 49.331 ;
     RECT  63.36 49.285 63.816 49.331 ;
     RECT  2.4 48.229 6.792 49.333 ;
     RECT  53.664 49.043 53.688 49.379 ;
     RECT  47.184 49.093 47.304 49.381 ;
     RECT  24 49.141 25.128 49.427 ;
     RECT  39.84 49.043 40.512 49.427 ;
     RECT  28.464 49.189 31.272 49.429 ;
     RECT  44.16 49.235 44.184 49.475 ;
     RECT  61.392 49.045 62.112 49.475 ;
     RECT  1.584 49.333 6.792 49.477 ;
     RECT  7.8 48.805 11.4 49.477 ;
     RECT  12.768 48.419 13.512 49.477 ;
     RECT  45.456 49.235 46.008 49.477 ;
     RECT  47.088 49.381 47.304 49.477 ;
     RECT  42.768 48.085 42.792 49.571 ;
     RECT  54.672 49.285 58.008 49.571 ;
     RECT  28.464 49.429 31.944 49.619 ;
     RECT  69.552 48.947 69.576 49.619 ;
     RECT  37.152 45.685 37.176 49.765 ;
     RECT  18.6 48.659 18.912 49.861 ;
     RECT  20.496 48.659 20.52 49.861 ;
     RECT  45.456 49.477 47.304 49.861 ;
     RECT  48.816 48.661 49.8 49.861 ;
     RECT  26.352 48.659 27.48 49.907 ;
     RECT  36.192 49.765 37.176 49.907 ;
     RECT  66.144 48.515 67.512 49.957 ;
     RECT  55.68 49.571 58.008 50.003 ;
     RECT  45.456 49.861 49.8 50.005 ;
     RECT  12.768 49.477 13.896 50.101 ;
     RECT  66.144 49.957 67.752 50.101 ;
     RECT  54.672 49.571 54.696 50.195 ;
     RECT  31.2 49.619 31.944 50.243 ;
     RECT  26.4 49.907 27.48 50.339 ;
     RECT  45.456 50.005 49.896 50.389 ;
     RECT  31.92 50.243 31.944 50.533 ;
     RECT  18.6 49.861 20.52 50.579 ;
     RECT  34.8 48.757 35.208 50.579 ;
     RECT  65.52 50.101 67.8 50.629 ;
     RECT  17.52 50.533 17.544 50.675 ;
     RECT  31.92 50.533 32.76 50.675 ;
     RECT  37.152 49.907 37.176 50.677 ;
     RECT  63.36 49.331 63.576 50.677 ;
     RECT  76.608 48.949 76.968 50.677 ;
     RECT  24 49.427 24.936 50.723 ;
     RECT  75.792 50.677 76.968 50.723 ;
     RECT  45.216 50.389 49.896 50.771 ;
     RECT  56.4 50.003 58.008 50.771 ;
     RECT  26.4 50.339 27.288 50.819 ;
     RECT  12.768 50.101 14.472 50.965 ;
     RECT  60.384 50.389 60.408 51.109 ;
     RECT  28.464 49.619 29.712 51.203 ;
     RECT  75.792 50.723 76.872 51.299 ;
     RECT  1.584 49.477 11.4 51.347 ;
     RECT  31.92 50.675 31.944 51.347 ;
     RECT  37.152 50.677 37.752 51.347 ;
     RECT  63.312 50.677 63.576 51.347 ;
     RECT  37.152 51.347 37.176 51.541 ;
     RECT  27.12 50.819 27.288 51.635 ;
     RECT  12.672 50.965 14.472 51.827 ;
     RECT  43.92 51.397 43.944 51.829 ;
     RECT  76.8 51.299 76.872 51.875 ;
     RECT  29.4 51.203 29.712 51.877 ;
     RECT  16.368 46.787 16.392 51.923 ;
     RECT  27.12 51.635 27.144 51.923 ;
     RECT  52.416 49.043 52.44 51.923 ;
     RECT  64.896 50.629 67.8 51.923 ;
     RECT  1.584 51.347 11.304 51.971 ;
     RECT  60.384 51.109 60.504 52.115 ;
     RECT  43.92 51.829 44.04 52.163 ;
     RECT  63.312 51.347 63.384 52.163 ;
     RECT  36.528 51.541 37.176 52.211 ;
     RECT  60.384 52.115 60.408 52.213 ;
     RECT  76.848 51.875 76.872 52.261 ;
     RECT  78 45.299 78.312 52.261 ;
     RECT  76.848 52.261 78.312 52.451 ;
     RECT  1.584 51.971 4.536 52.499 ;
     RECT  24 50.723 24.312 52.549 ;
     RECT  26.448 51.925 26.76 52.549 ;
     RECT  5.52 51.971 11.304 52.741 ;
     RECT  42.144 52.693 42.168 52.883 ;
     RECT  26.352 52.549 26.76 52.933 ;
     RECT  5.52 52.741 11.544 52.981 ;
     RECT  12.912 51.827 14.472 52.981 ;
     RECT  44.016 52.163 44.04 52.981 ;
     RECT  45.216 50.771 49.656 52.981 ;
     RECT  51 48.995 51.312 52.981 ;
     RECT  29.4 51.877 29.832 53.075 ;
     RECT  75.792 51.299 75.816 53.075 ;
     RECT  24 52.549 24.408 53.269 ;
     RECT  26.352 52.933 27.144 53.269 ;
     RECT  60.048 52.213 60.408 53.365 ;
     RECT  61.488 49.475 62.112 53.365 ;
     RECT  44.016 52.981 44.232 53.413 ;
     RECT  45.216 52.981 51.96 53.413 ;
     RECT  44.016 53.413 51.96 53.555 ;
     RECT  5.52 52.981 14.472 53.557 ;
     RECT  24 53.269 25.128 53.557 ;
     RECT  26.352 53.269 27.24 53.557 ;
     RECT  44.016 53.555 49.8 53.557 ;
     RECT  63.312 52.163 63.336 53.557 ;
     RECT  65.52 51.923 67.8 53.557 ;
     RECT  77.232 52.451 78.312 53.557 ;
     RECT  37.152 52.211 37.176 53.603 ;
     RECT  63.216 53.557 68.52 53.605 ;
     RECT  76.56 53.557 78.312 53.605 ;
     RECT  20.496 50.579 20.52 53.651 ;
     RECT  57.84 50.771 57.864 53.651 ;
     RECT  32.4 52.981 32.424 53.795 ;
     RECT  1.584 52.499 4.44 53.797 ;
     RECT  5.424 53.557 14.472 53.797 ;
     RECT  24 53.557 27.336 53.989 ;
     RECT  18.6 50.579 18.912 54.009 ;
     RECT  29.4 53.075 29.712 54.009 ;
     RECT  34.8 50.579 35.112 54.009 ;
     RECT  40.2 49.427 40.512 54.009 ;
     RECT  51 53.555 51.312 54.009 ;
     RECT  56.4 50.771 56.712 54.009 ;
     RECT  72.6 48.659 72.912 54.009 ;
     RECT  18.6 54.009 18.72 54.023 ;
     RECT  24 53.989 27.528 54.023 ;
     RECT  29.4 54.009 29.52 54.023 ;
     RECT  34.8 54.009 34.92 54.023 ;
     RECT  40.2 54.009 40.32 54.023 ;
     RECT  51 54.009 51.12 54.023 ;
     RECT  56.4 54.009 56.52 54.023 ;
     RECT  72.6 54.009 72.72 54.023 ;
     RECT  63.216 53.605 69 54.037 ;
     RECT  43.824 53.557 49.8 54.085 ;
     RECT  59.088 53.365 62.112 54.085 ;
     RECT  63.12 54.037 69 54.085 ;
     RECT  76.56 53.605 78.408 54.133 ;
     RECT  76.08 54.133 78.408 54.709 ;
     RECT  1.584 53.797 14.472 55.237 ;
     RECT  75.984 54.709 78.408 56.051 ;
     RECT  1.488 55.237 14.472 56.144 ;
     RECT  24.528 54.023 27.528 56.144 ;
     RECT  43.728 54.085 49.8 56.144 ;
     RECT  59.088 54.085 69 56.144 ;
     RECT  75.984 56.051 78.216 56.144 ;
  END
END ot_hgi_coll_fj_n1s0
END LIBRARY
